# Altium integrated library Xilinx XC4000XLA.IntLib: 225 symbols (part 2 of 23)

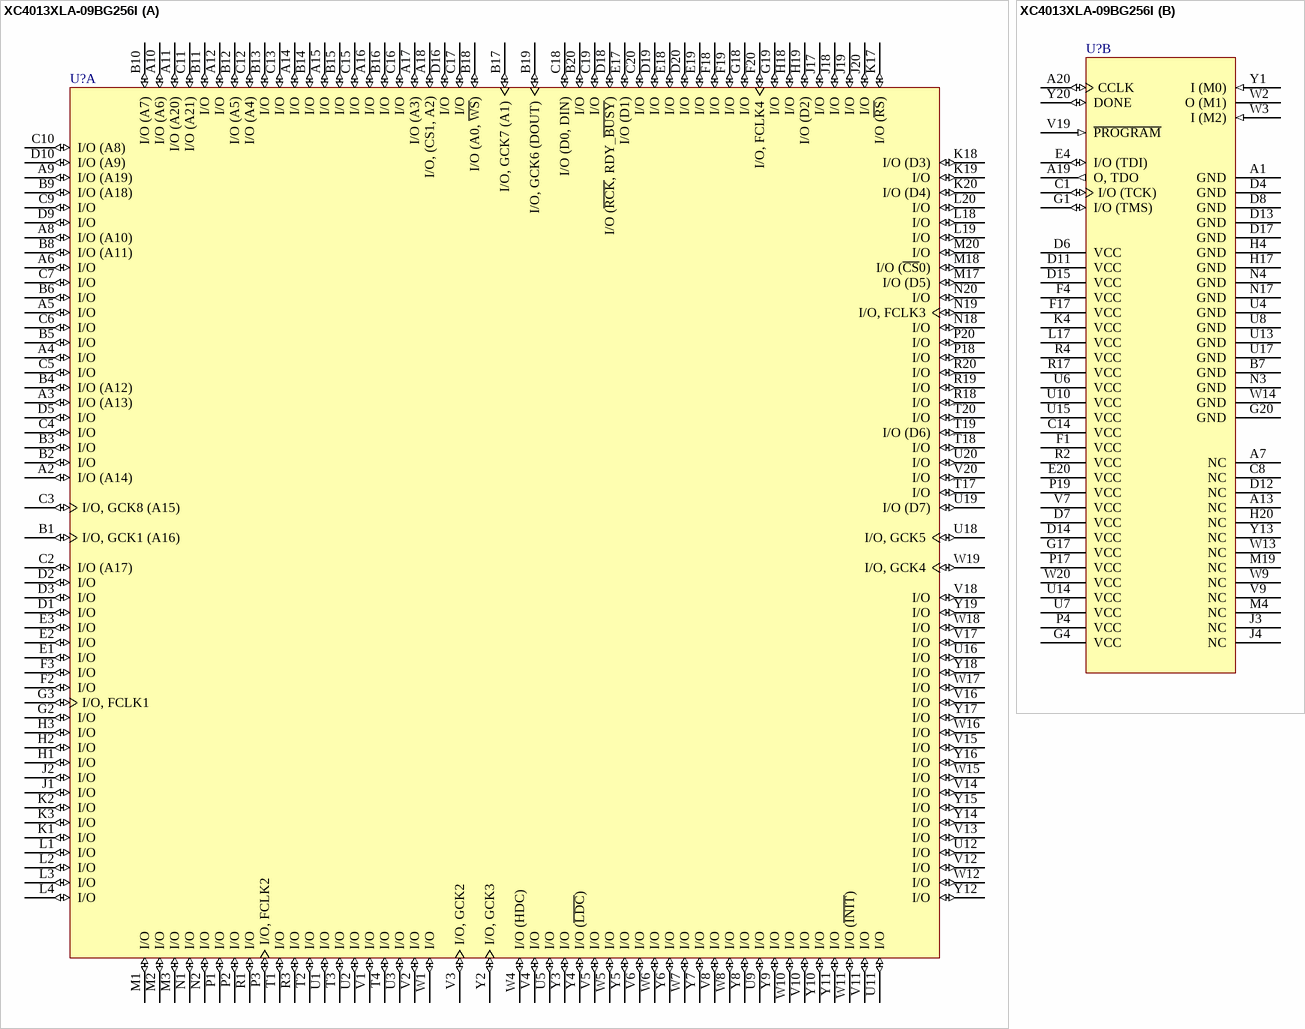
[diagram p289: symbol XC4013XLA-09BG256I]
## XC4013XLA-09BG256I
designator U?
XC4000XLA FPGA, 192 I/Os, 256-Ball BGA, Speed Grade 9, Industrial Grade
footprint BG256 (BGA, 256-Leads, Body 27x27mm, Pitch 1.27mm)
part A pins: A2 I/O (A14) (io), A3 I/O (A13) (io), A4 I/O (io), A5 I/O (io), A6 I/O (io), A8 I/O (A10) (io), A9 I/O (A19) (io), A10 I/O (A6) (io), A11 I/O (A20) (io), A12 I/O (io), A14 I/O (io), A15 I/O (io), A16 I/O (io), A17 I/O (A3) (io), A18 I/O, (CS1, A2) (io), B1 I/O, GCK1 (A16) (io), B2 I/O (io), B3 I/O (io), B4 I/O (A12) (io), B5 I/O (io), B6 I/O (io), B8 I/O (A11) (io), B9 I/O (A18) (io), B10 I/O (A7) (io), B11 I/O (io), B12 I/O (A5) (io), B13 I/O (io), B14 I/O (io), B15 I/O (io), B16 I/O (io), B17 I/O, GCK7 (A1) (io), B18 I/O (A0, ~{WS}) (io), B19 I/O, GCK6 (DOUT) (io), B20 I/O (io), C2 I/O (A17) (io), C3 I/O, GCK8 (A15) (io), C4 I/O (io), C5 I/O (io), C6 I/O (io), C7 I/O (io), C9 I/O (io), C10 I/O (A8) (io), C11 I/O (A21) (io), C12 I/O (A4) (io), C13 I/O (io), C15 I/O (io), C16 I/O (io), C17 I/O (io), C18 I/O (D0, DIN) (io), C19 I/O (io), C20 I/O (io), D1 I/O (io), D2 I/O (io), D3 I/O (io), D5 I/O (io), D9 I/O (io), D10 I/O (A9) (io), D16 I/O (io), D18 I/O (~{RCK}, RDY_~{BUSY}) (io), D19 I/O (io), D20 I/O (io), E1 I/O (io), E2 I/O (io), E3 I/O (io), E17 I/O (D1) (io), E18 I/O (io), E19 I/O (io), F2 I/O (io), F3 I/O (io), F18 I/O (io), F19 I/O (io), F20 I/O, FCLK4 (io), G2 I/O (io), G3 I/O, FCLK1 (io), G18 I/O (io), G19 I/O (io), H1 I/O (io), H2 I/O (io), H3 I/O (io), H18 I/O (io), H19 I/O (D2) (io), J1 I/O (io), J2 I/O (io), J17 I/O (io), J18 I/O (io), J19 I/O (io), J20 I/O (io), K1 I/O (io), K2 I/O (io), K3 I/O (io), K17 I/O (~{RS}) (io), K18 I/O (D3) (io), K19 I/O (io), K20 I/O (D4) (io), L1 I/O (io), L2 I/O (io), L3 I/O (io), L4 I/O (io), L18 I/O (io), L19 I/O (io), L20 I/O (io), M1 I/O (io), M2 I/O (io), M3 I/O (io), M17 I/O (D5) (io), M18 I/O (~{CS}0) (io), M20 I/O (io), N1 I/O (io), N2 I/O (io), N18 I/O (io), N19 I/O, FCLK3 (io), N20 I/O (io), P1 I/O (io), P2 I/O (io), P3 I/O, FCLK2 (io), P18 I/O (io), P20 I/O (io), R1 I/O (io), R3 I/O (io), R18 I/O (io), R19 I/O (io), R20 I/O (io), T1 I/O (io), T2 I/O (io), T3 I/O (io), T4 I/O (io), T17 I/O (io), T18 I/O (io), T19 I/O (D6) (io), T20 I/O (io), U1 I/O (io), U2 I/O (io), U3 I/O (io), U5 I/O (io), U9 I/O (io), U11 I/O (io), U12 I/O (io), U16 I/O (io), U18 I/O, GCK5 (io), U19 I/O (D7) (io), U20 I/O (io), V1 I/O (io), V2 I/O (io), V3 I/O, GCK2 (io), V4 I/O (io), V5 I/O (io), V6 I/O (io), V8 I/O (io), V10 I/O (io), V11 I/O (io), V12 I/O (io), V13 I/O (io), V14 I/O (io), V15 I/O (io), V16 I/O (io), V17 I/O (io), V18 I/O (io), V20 I/O (io), W1 I/O (io), W4 I/O (HDC) (io), W5 I/O (io), W6 I/O (io), W7 I/O (io), W8 I/O (io), W10 I/O (io), W11 I/O (~{INIT}) (io), W12 I/O (io), W15 I/O (io), W16 I/O (io), W17 I/O (io), W18 I/O (io), W19 I/O, GCK4 (io), Y2 I/O, GCK3 (io), Y3 I/O (io), Y4 I/O (~{LDC}) (io), Y5 I/O (io), Y6 I/O (io), Y7 I/O (io), Y8 I/O (io), Y9 I/O (io), Y10 I/O (io), Y11 I/O (io), Y12 I/O (io), Y14 I/O (io), Y15 I/O (io), Y16 I/O (io), Y17 I/O (io), Y18 I/O (io), Y19 I/O (io)
part B pins: A1 GND (power), A7 NC, A13 NC, A19 O, TDO (out), A20 CCLK (io), B7 GND (power), C1 I/O (TCK) (io), C8 NC, C14 VCC (power), D4 GND (power), D6 VCC (power), D7 VCC (power), D8 GND (power), D11 VCC (power), D12 NC, D13 GND (power), D14 VCC (power), D15 VCC (power), D17 GND (power), E4 I/O (TDI) (io), E20 VCC (power), F1 VCC (power), F4 VCC (power), F17 VCC (power), G1 I/O (TMS) (io), G4 VCC (power), G17 VCC (power), G20 GND (power), H4 GND (power), H17 GND (power), H20 NC, J3 NC, J4 NC, K4 VCC (power), L17 VCC (power), M4 NC, M19 NC, N3 GND (power), N4 GND (power), N17 GND (power), P4 VCC (power), P17 VCC (power), P19 VCC (power), R2 VCC (power), R4 VCC (power), R17 VCC (power), U4 GND (power), U6 VCC (power), U7 VCC (power), U8 GND (power), U10 VCC (power), U13 GND (power), U14 VCC (power), U15 VCC (power), U17 GND (power), V7 VCC (power), V9 NC, V19 ~{PROGRAM} (in), W2 O (M1), W3 I (M2) (in), W9 NC, W13 NC, W14 GND (power), W20 VCC (power), Y1 I (M0) (in), Y13 NC, Y20 DONE (io)


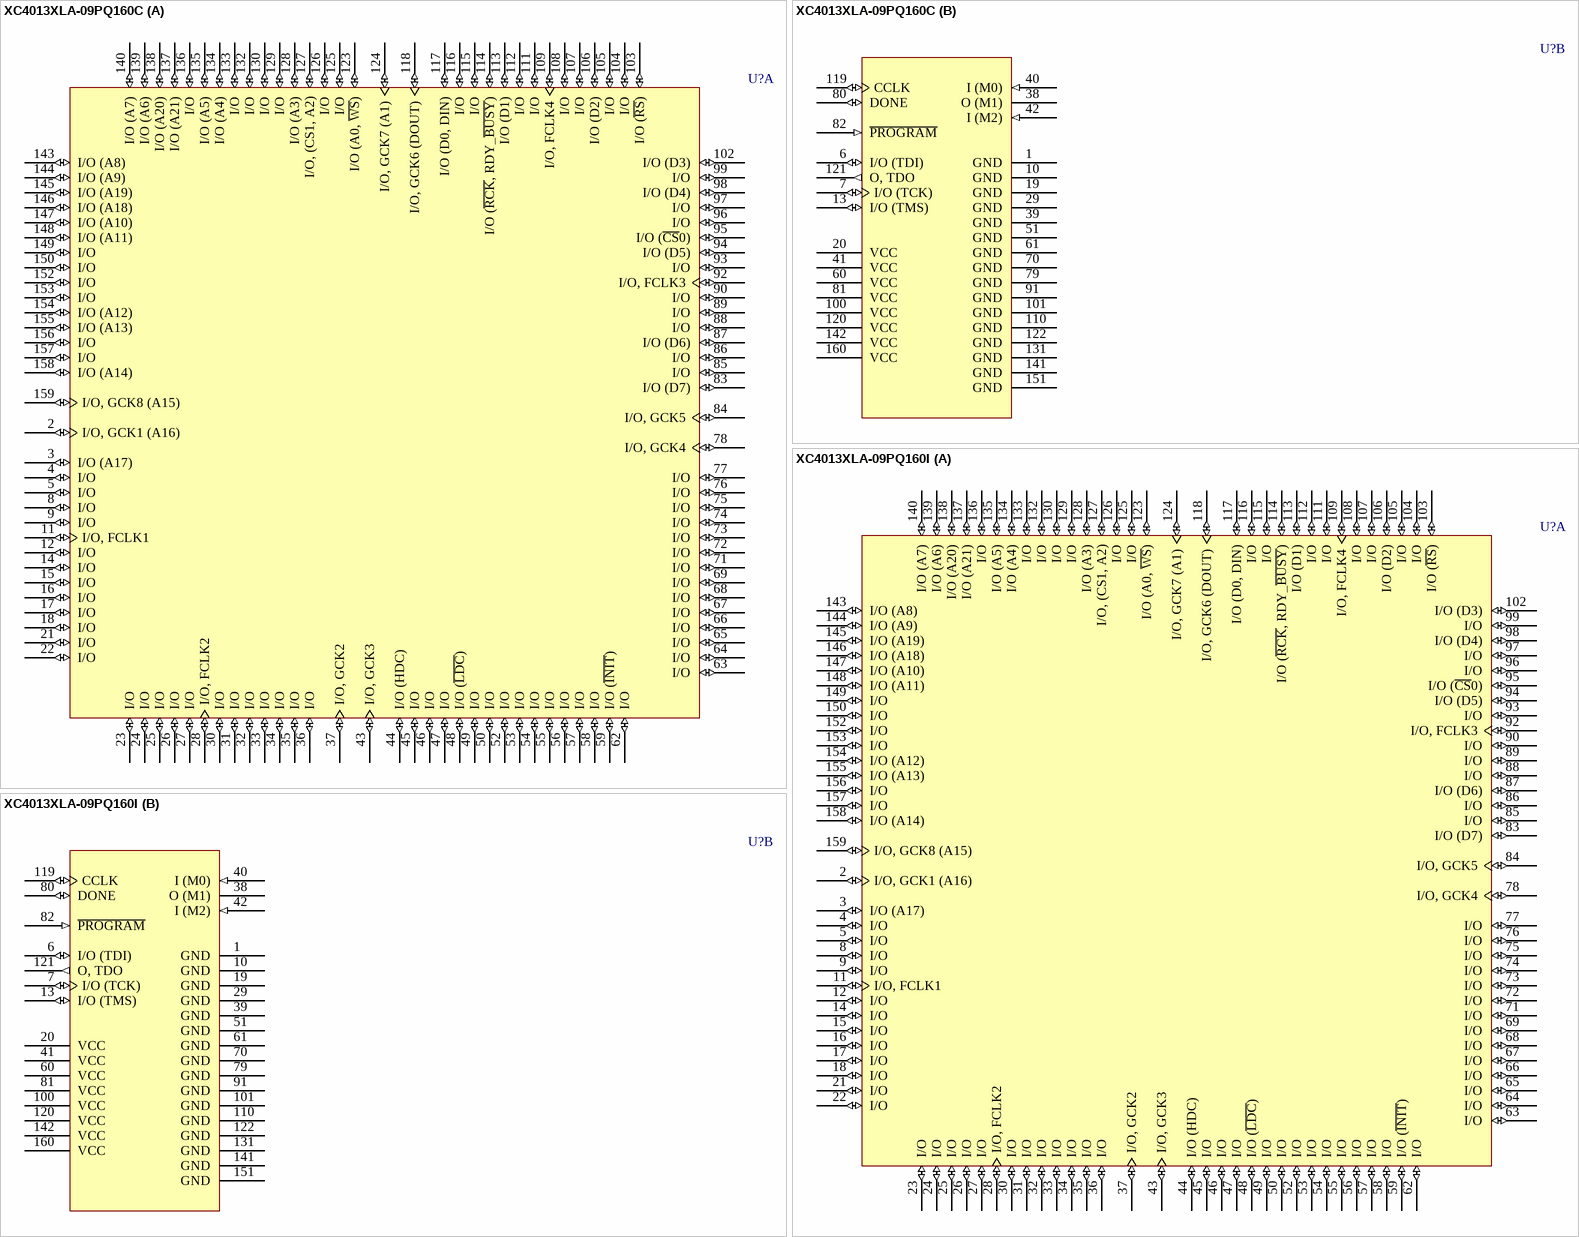
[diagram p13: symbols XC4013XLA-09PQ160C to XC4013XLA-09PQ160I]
## XC4013XLA-09PQ160C
designator U?
XC4000XLA FPGA, 129 I/Os, 160-Pin PQFP, Speed Grade 9, Commercial Grade
footprint PQ160_N (QFP, 160-Leads, Body 28x28mm, Pitch 0.65mm, IPC Medium Density)
footprint PQ160_L (QFP, 160-Leads, Body 28x28mm, Pitch 0.65mm, IPC High Density)
footprint PQ160_M (QFP, 160-Leads, Body 28x28mm, Pitch 0.65mm, IPC Low Density)
part A pins: 2 I/O, GCK1 (A16) (io), 3 I/O (A17) (io), 4 I/O (io), 5 I/O (io), 8 I/O (io), 9 I/O (io), 11 I/O, FCLK1 (io), 12 I/O (io), 14 I/O (io), 15 I/O (io), 16 I/O (io), 17 I/O (io), 18 I/O (io), 21 I/O (io), 22 I/O (io), 23 I/O (io), 24 I/O (io), 25 I/O (io), 26 I/O (io), 27 I/O (io), 28 I/O, FCLK2 (io), 30 I/O (io), 31 I/O (io), 32 I/O (io), 33 I/O (io), 34 I/O (io), 35 I/O (io), 36 I/O (io), 37 I/O, GCK2 (io), 43 I/O, GCK3 (io), 44 I/O (HDC) (io), 45 I/O (io), 46 I/O (io), 47 I/O (io), 48 I/O (~{LDC}) (io), 49 I/O (io), 50 I/O (io), 52 I/O (io), 53 I/O (io), 54 I/O (io), 55 I/O (io), 56 I/O (io), 57 I/O (io), 58 I/O (io), 59 I/O (~{INIT}) (io), 62 I/O (io), 63 I/O (io), 64 I/O (io), 65 I/O (io), 66 I/O (io), 67 I/O (io), 68 I/O (io), 69 I/O (io), 71 I/O (io), 72 I/O (io), 73 I/O (io), 74 I/O (io), 75 I/O (io), 76 I/O (io), 77 I/O (io), 78 I/O, GCK4 (io), 83 I/O (D7) (io), 84 I/O, GCK5 (io), 85 I/O (io), 86 I/O (io), 87 I/O (D6) (io), 88 I/O (io), 89 I/O (io), 90 I/O (io), 92 I/O, FCLK3 (io), 93 I/O (io), 94 I/O (D5) (io), 95 I/O (~{CS}0) (io), 96 I/O (io), 97 I/O (io), 98 I/O (D4) (io), 99 I/O (io), 102 I/O (D3) (io), 103 I/O (~{RS}) (io), 104 I/O (io), 105 I/O (io), 106 I/O (D2) (io), 107 I/O (io), 108 I/O (io), 109 I/O, FCLK4 (io), 111 I/O (io), 112 I/O (io), 113 I/O (D1) (io), 114 I/O (~{RCK}, RDY_~{BUSY}) (io), 115 I/O (io), 116 I/O (io), 117 I/O (D0, DIN) (io), 118 I/O, GCK6 (DOUT) (io), 123 I/O (A0, ~{WS}) (io), 124 I/O, GCK7 (A1) (io), 125 I/O (io), 126 I/O (io), 127 I/O, (CS1, A2) (io), 128 I/O (A3) (io), 129 I/O (io), 130 I/O (io), 132 I/O (io), 133 I/O (io), 134 I/O (A4) (io), 135 I/O (A5) (io), 136 I/O (io), 137 I/O (A21) (io), 138 I/O (A20) (io), 139 I/O (A6) (io), 140 I/O (A7) (io), 143 I/O (A8) (io), 144 I/O (A9) (io), 145 I/O (A19) (io), 146 I/O (A18) (io), 147 I/O (A10) (io), 148 I/O (A11) (io), 149 I/O (io), 150 I/O (io), 152 I/O (io), 153 I/O (io), 154 I/O (A12) (io), 155 I/O (A13) (io), 156 I/O (io), 157 I/O (io), 158 I/O (A14) (io), 159 I/O, GCK8 (A15) (io)
part B pins: 1 GND (power), 6 I/O (TDI) (io), 7 I/O (TCK) (io), 10 GND (power), 13 I/O (TMS) (io), 19 GND (power), 20 VCC (power), 29 GND (power), 38 O (M1), 39 GND (power), 40 I (M0) (in), 41 VCC (power), 42 I (M2) (in), 51 GND (power), 60 VCC (power), 61 GND (power), 70 GND (power), 79 GND (power), 80 DONE (io), 81 VCC (power), 82 ~{PROGRAM} (in), 91 GND (power), 100 VCC (power), 101 GND (power), 110 GND (power), 119 CCLK (io), 120 VCC (power), 121 O, TDO (out), 122 GND (power), 131 GND (power), 141 GND (power), 142 VCC (power), 151 GND (power), 160 VCC (power)

## XC4013XLA-09PQ160I
designator U?
XC4000XLA FPGA, 129 I/Os, 160-Pin PQFP, Speed Grade 9, Industrial Grade
footprint PQ160_N (QFP, 160-Leads, Body 28x28mm, Pitch 0.65mm, IPC Medium Density)
footprint PQ160_L (QFP, 160-Leads, Body 28x28mm, Pitch 0.65mm, IPC High Density)
footprint PQ160_M (QFP, 160-Leads, Body 28x28mm, Pitch 0.65mm, IPC Low Density)
part A pins: 2 I/O, GCK1 (A16) (io), 3 I/O (A17) (io), 4 I/O (io), 5 I/O (io), 8 I/O (io), 9 I/O (io), 11 I/O, FCLK1 (io), 12 I/O (io), 14 I/O (io), 15 I/O (io), 16 I/O (io), 17 I/O (io), 18 I/O (io), 21 I/O (io), 22 I/O (io), 23 I/O (io), 24 I/O (io), 25 I/O (io), 26 I/O (io), 27 I/O (io), 28 I/O, FCLK2 (io), 30 I/O (io), 31 I/O (io), 32 I/O (io), 33 I/O (io), 34 I/O (io), 35 I/O (io), 36 I/O (io), 37 I/O, GCK2 (io), 43 I/O, GCK3 (io), 44 I/O (HDC) (io), 45 I/O (io), 46 I/O (io), 47 I/O (io), 48 I/O (~{LDC}) (io), 49 I/O (io), 50 I/O (io), 52 I/O (io), 53 I/O (io), 54 I/O (io), 55 I/O (io), 56 I/O (io), 57 I/O (io), 58 I/O (io), 59 I/O (~{INIT}) (io), 62 I/O (io), 63 I/O (io), 64 I/O (io), 65 I/O (io), 66 I/O (io), 67 I/O (io), 68 I/O (io), 69 I/O (io), 71 I/O (io), 72 I/O (io), 73 I/O (io), 74 I/O (io), 75 I/O (io), 76 I/O (io), 77 I/O (io), 78 I/O, GCK4 (io), 83 I/O (D7) (io), 84 I/O, GCK5 (io), 85 I/O (io), 86 I/O (io), 87 I/O (D6) (io), 88 I/O (io), 89 I/O (io), 90 I/O (io), 92 I/O, FCLK3 (io), 93 I/O (io), 94 I/O (D5) (io), 95 I/O (~{CS}0) (io), 96 I/O (io), 97 I/O (io), 98 I/O (D4) (io), 99 I/O (io), 102 I/O (D3) (io), 103 I/O (~{RS}) (io), 104 I/O (io), 105 I/O (io), 106 I/O (D2) (io), 107 I/O (io), 108 I/O (io), 109 I/O, FCLK4 (io), 111 I/O (io), 112 I/O (io), 113 I/O (D1) (io), 114 I/O (~{RCK}, RDY_~{BUSY}) (io), 115 I/O (io), 116 I/O (io), 117 I/O (D0, DIN) (io), 118 I/O, GCK6 (DOUT) (io), 123 I/O (A0, ~{WS}) (io), 124 I/O, GCK7 (A1) (io), 125 I/O (io), 126 I/O (io), 127 I/O, (CS1, A2) (io), 128 I/O (A3) (io), 129 I/O (io), 130 I/O (io), 132 I/O (io), 133 I/O (io), 134 I/O (A4) (io), 135 I/O (A5) (io), 136 I/O (io), 137 I/O (A21) (io), 138 I/O (A20) (io), 139 I/O (A6) (io), 140 I/O (A7) (io), 143 I/O (A8) (io), 144 I/O (A9) (io), 145 I/O (A19) (io), 146 I/O (A18) (io), 147 I/O (A10) (io), 148 I/O (A11) (io), 149 I/O (io), 150 I/O (io), 152 I/O (io), 153 I/O (io), 154 I/O (A12) (io), 155 I/O (A13) (io), 156 I/O (io), 157 I/O (io), 158 I/O (A14) (io), 159 I/O, GCK8 (A15) (io)
part B pins: 1 GND (power), 6 I/O (TDI) (io), 7 I/O (TCK) (io), 10 GND (power), 13 I/O (TMS) (io), 19 GND (power), 20 VCC (power), 29 GND (power), 38 O (M1), 39 GND (power), 40 I (M0) (in), 41 VCC (power), 42 I (M2) (in), 51 GND (power), 60 VCC (power), 61 GND (power), 70 GND (power), 79 GND (power), 80 DONE (io), 81 VCC (power), 82 ~{PROGRAM} (in), 91 GND (power), 100 VCC (power), 101 GND (power), 110 GND (power), 119 CCLK (io), 120 VCC (power), 121 O, TDO (out), 122 GND (power), 131 GND (power), 141 GND (power), 142 VCC (power), 151 GND (power), 160 VCC (power)


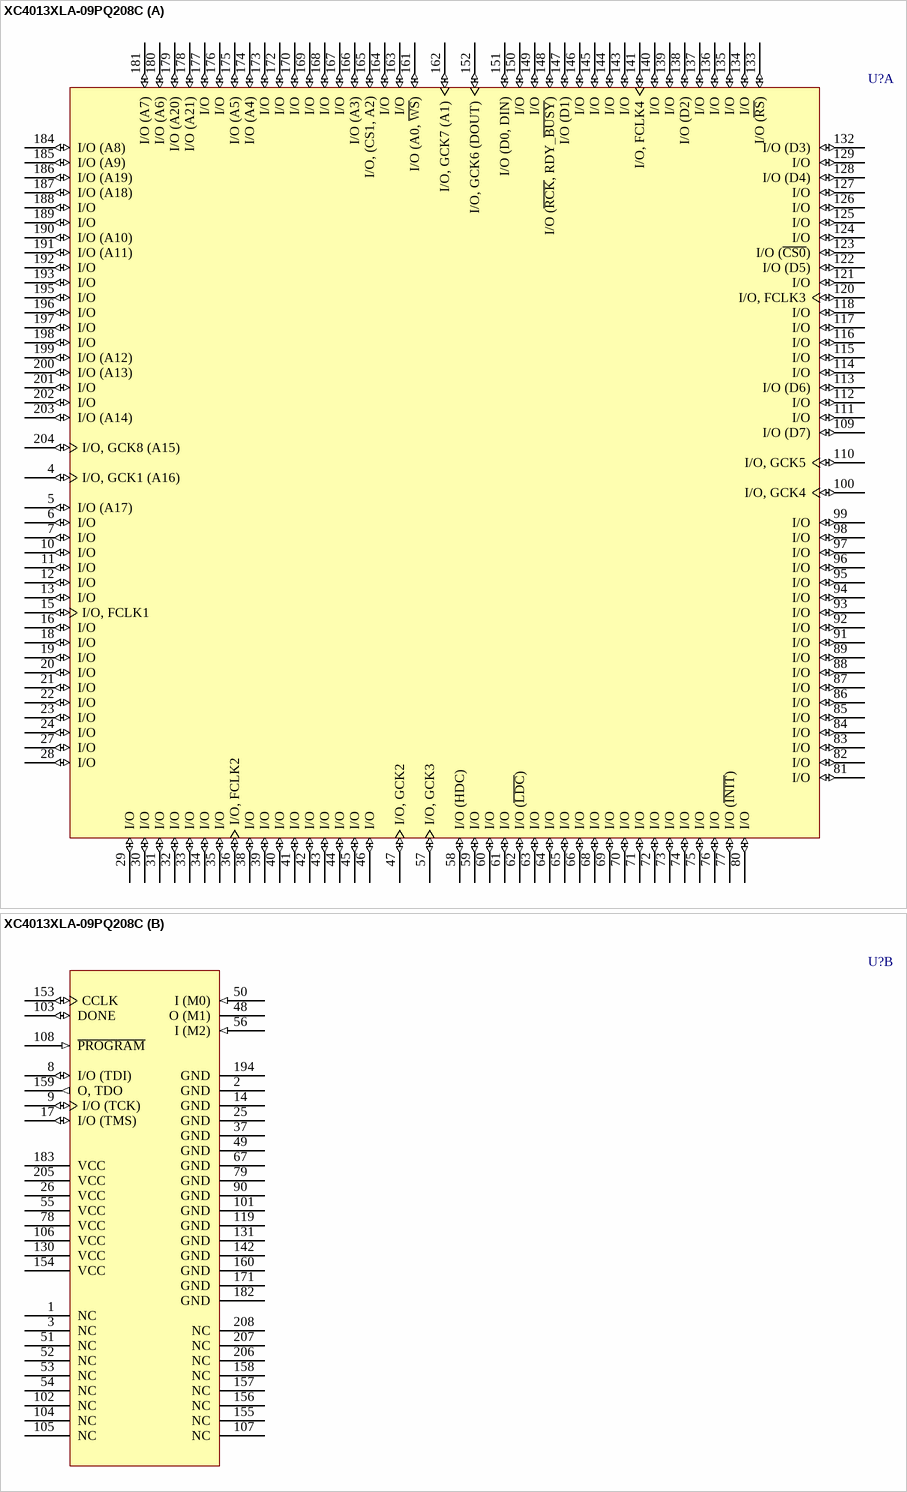
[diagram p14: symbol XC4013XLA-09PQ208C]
## XC4013XLA-09PQ208C
designator U?
XC4000XLA FPGA, 160 I/Os, 208-Pin PQFP, Speed Grade 9, Commercial Grade
footprint PQ208_N (Shrink QFP, 208-Leads, Body 28x28mm, Pitch 0.5mm, IPC Medium Density)
footprint PQ208_L (Shrink QFP, 208-Leads, Body 28x28mm, Pitch 0.5mm, IPC High Density)
footprint PQ208_M (Shrink QFP, 208-Leads, Body 28x28mm, Pitch 0.5mm, IPC Low Density)
part A pins: 4 I/O, GCK1 (A16) (io), 5 I/O (A17) (io), 6 I/O (io), 7 I/O (io), 10 I/O (io), 11 I/O (io), 12 I/O (io), 13 I/O (io), 15 I/O, FCLK1 (io), 16 I/O (io), 18 I/O (io), 19 I/O (io), 20 I/O (io), 21 I/O (io), 22 I/O (io), 23 I/O (io), 24 I/O (io), 27 I/O (io), 28 I/O (io), 29 I/O (io), 30 I/O (io), 31 I/O (io), 32 I/O (io), 33 I/O (io), 34 I/O (io), 35 I/O (io), 36 I/O, FCLK2 (io), 38 I/O (io), 39 I/O (io), 40 I/O (io), 41 I/O (io), 42 I/O (io), 43 I/O (io), 44 I/O (io), 45 I/O (io), 46 I/O (io), 47 I/O, GCK2 (io), 57 I/O, GCK3 (io), 58 I/O (HDC) (io), 59 I/O (io), 60 I/O (io), 61 I/O (io), 62 I/O (~{LDC}) (io), 63 I/O (io), 64 I/O (io), 65 I/O (io), 66 I/O (io), 68 I/O (io), 69 I/O (io), 70 I/O (io), 71 I/O (io), 72 I/O (io), 73 I/O (io), 74 I/O (io), 75 I/O (io), 76 I/O (io), 77 I/O (~{INIT}) (io), 80 I/O (io), 81 I/O (io), 82 I/O (io), 83 I/O (io), 84 I/O (io), 85 I/O (io), 86 I/O (io), 87 I/O (io), 88 I/O (io), 89 I/O (io), 91 I/O (io), 92 I/O (io), 93 I/O (io), 94 I/O (io), 95 I/O (io), 96 I/O (io), 97 I/O (io), 98 I/O (io), 99 I/O (io), 100 I/O, GCK4 (io), 109 I/O (D7) (io), 110 I/O, GCK5 (io), 111 I/O (io), 112 I/O (io), 113 I/O (D6) (io), 114 I/O (io), 115 I/O (io), 116 I/O (io), 117 I/O (io), 118 I/O (io), 120 I/O, FCLK3 (io), 121 I/O (io), 122 I/O (D5) (io), 123 I/O (~{CS0}) (io), 124 I/O (io), 125 I/O (io), 126 I/O (io), 127 I/O (io), 128 I/O (D4) (io), 129 I/O (io), 132 I/O (D3) (io), 133 I/O (~{RS}) (io), 134 I/O (io), 135 I/O (io), 136 I/O (io), 137 I/O (io), 138 I/O (D2) (io), 139 I/O (io), 140 I/O (io), 141 I/O, FCLK4 (io), 143 I/O (io), 144 I/O (io), 145 I/O (io), 146 I/O (io), 147 I/O (D1) (io), 148 I/O (~{RCK}, RDY_~{BUSY}) (io), 149 I/O (io), 150 I/O (io), 151 I/O (D0, DIN) (io), 152 I/O, GCK6 (DOUT) (io), 161 I/O (A0, ~{WS}) (io), 162 I/O, GCK7 (A1) (io), 163 I/O (io), 164 I/O (io), 165 I/O, (CS1, A2) (io), 166 I/O (A3) (io), 167 I/O (io), 168 I/O (io), 169 I/O (io), 170 I/O (io), 172 I/O (io), 173 I/O (io), 174 I/O (A4) (io), 175 I/O (A5) (io), 176 I/O (io), 177 I/O (io), 178 I/O (A21) (io), 179 I/O (A20) (io), 180 I/O (A6) (io), 181 I/O (A7) (io), 184 I/O (A8) (io), 185 I/O (A9) (io), 186 I/O (A19) (io), 187 I/O (A18) (io), 188 I/O (io), 189 I/O (io), 190 I/O (A10) (io), 191 I/O (A11) (io), 192 I/O (io), 193 I/O (io), 195 I/O (io), 196 I/O (io), 197 I/O (io), 198 I/O (io), 199 I/O (A12) (io), 200 I/O (A13) (io), 201 I/O (io), 202 I/O (io), 203 I/O (A14) (io), 204 I/O, GCK8 (A15) (io)
part B pins: 1 NC, 2 GND (power), 3 NC, 8 I/O (TDI) (io), 9 I/O (TCK) (io), 14 GND (power), 17 I/O (TMS) (io), 25 GND (power), 26 VCC (power), 37 GND (power), 48 O (M1), 49 GND (power), 50 I (M0) (in), 51 NC, 52 NC, 53 NC, 54 NC, 55 VCC (power), 56 I (M2) (in), 67 GND (power), 78 VCC (power), 79 GND (power), 90 GND (power), 101 GND (power), 102 NC, 103 DONE (io), 104 NC, 105 NC, 106 VCC (power), 107 NC, 108 ~{PROGRAM} (in), 119 GND (power), 130 VCC (power), 131 GND (power), 142 GND (power), 153 CCLK (io), 154 VCC (power), 155 NC, 156 NC, 157 NC, 158 NC, 159 O, TDO (out), 160 GND (power), 171 GND (power), 182 GND (power), 183 VCC (power), 194 GND (power), 205 VCC (power), 206 NC, 207 NC, 208 NC


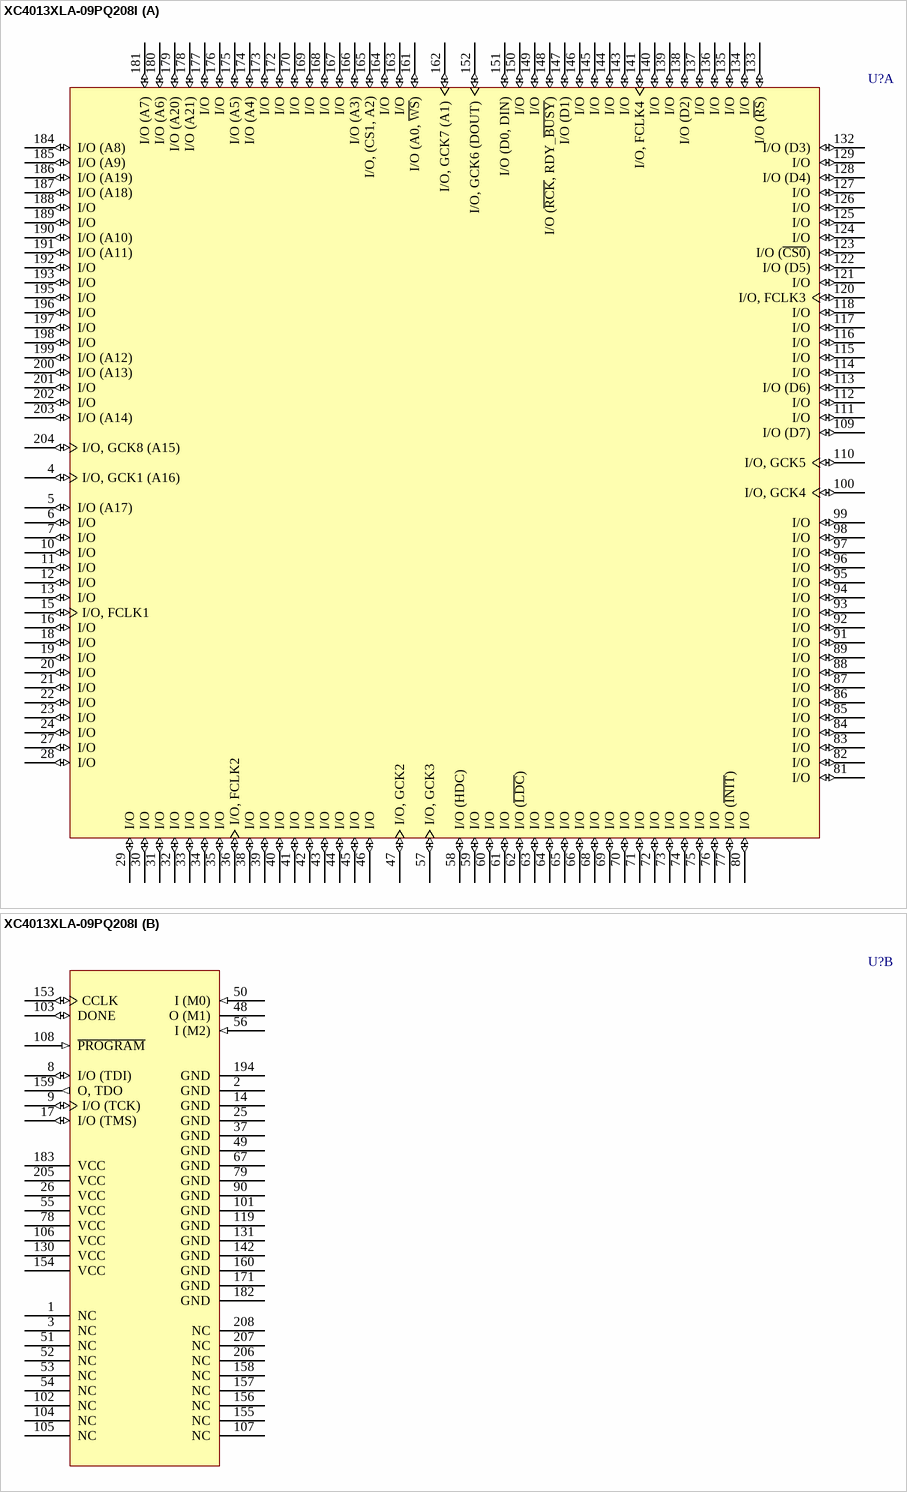
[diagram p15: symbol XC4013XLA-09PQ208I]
## XC4013XLA-09PQ208I
designator U?
XC4000XLA FPGA, 160 I/Os, 208-Pin PQFP, Speed Grade 9, Industrial Grade
footprint PQ208_N (Shrink QFP, 208-Leads, Body 28x28mm, Pitch 0.5mm, IPC Medium Density)
footprint PQ208_L (Shrink QFP, 208-Leads, Body 28x28mm, Pitch 0.5mm, IPC High Density)
footprint PQ208_M (Shrink QFP, 208-Leads, Body 28x28mm, Pitch 0.5mm, IPC Low Density)
part A pins: 4 I/O, GCK1 (A16) (io), 5 I/O (A17) (io), 6 I/O (io), 7 I/O (io), 10 I/O (io), 11 I/O (io), 12 I/O (io), 13 I/O (io), 15 I/O, FCLK1 (io), 16 I/O (io), 18 I/O (io), 19 I/O (io), 20 I/O (io), 21 I/O (io), 22 I/O (io), 23 I/O (io), 24 I/O (io), 27 I/O (io), 28 I/O (io), 29 I/O (io), 30 I/O (io), 31 I/O (io), 32 I/O (io), 33 I/O (io), 34 I/O (io), 35 I/O (io), 36 I/O, FCLK2 (io), 38 I/O (io), 39 I/O (io), 40 I/O (io), 41 I/O (io), 42 I/O (io), 43 I/O (io), 44 I/O (io), 45 I/O (io), 46 I/O (io), 47 I/O, GCK2 (io), 57 I/O, GCK3 (io), 58 I/O (HDC) (io), 59 I/O (io), 60 I/O (io), 61 I/O (io), 62 I/O (~{LDC}) (io), 63 I/O (io), 64 I/O (io), 65 I/O (io), 66 I/O (io), 68 I/O (io), 69 I/O (io), 70 I/O (io), 71 I/O (io), 72 I/O (io), 73 I/O (io), 74 I/O (io), 75 I/O (io), 76 I/O (io), 77 I/O (~{INIT}) (io), 80 I/O (io), 81 I/O (io), 82 I/O (io), 83 I/O (io), 84 I/O (io), 85 I/O (io), 86 I/O (io), 87 I/O (io), 88 I/O (io), 89 I/O (io), 91 I/O (io), 92 I/O (io), 93 I/O (io), 94 I/O (io), 95 I/O (io), 96 I/O (io), 97 I/O (io), 98 I/O (io), 99 I/O (io), 100 I/O, GCK4 (io), 109 I/O (D7) (io), 110 I/O, GCK5 (io), 111 I/O (io), 112 I/O (io), 113 I/O (D6) (io), 114 I/O (io), 115 I/O (io), 116 I/O (io), 117 I/O (io), 118 I/O (io), 120 I/O, FCLK3 (io), 121 I/O (io), 122 I/O (D5) (io), 123 I/O (~{CS0}) (io), 124 I/O (io), 125 I/O (io), 126 I/O (io), 127 I/O (io), 128 I/O (D4) (io), 129 I/O (io), 132 I/O (D3) (io), 133 I/O (~{RS}) (io), 134 I/O (io), 135 I/O (io), 136 I/O (io), 137 I/O (io), 138 I/O (D2) (io), 139 I/O (io), 140 I/O (io), 141 I/O, FCLK4 (io), 143 I/O (io), 144 I/O (io), 145 I/O (io), 146 I/O (io), 147 I/O (D1) (io), 148 I/O (~{RCK}, RDY_~{BUSY}) (io), 149 I/O (io), 150 I/O (io), 151 I/O (D0, DIN) (io), 152 I/O, GCK6 (DOUT) (io), 161 I/O (A0, ~{WS}) (io), 162 I/O, GCK7 (A1) (io), 163 I/O (io), 164 I/O (io), 165 I/O, (CS1, A2) (io), 166 I/O (A3) (io), 167 I/O (io), 168 I/O (io), 169 I/O (io), 170 I/O (io), 172 I/O (io), 173 I/O (io), 174 I/O (A4) (io), 175 I/O (A5) (io), 176 I/O (io), 177 I/O (io), 178 I/O (A21) (io), 179 I/O (A20) (io), 180 I/O (A6) (io), 181 I/O (A7) (io), 184 I/O (A8) (io), 185 I/O (A9) (io), 186 I/O (A19) (io), 187 I/O (A18) (io), 188 I/O (io), 189 I/O (io), 190 I/O (A10) (io), 191 I/O (A11) (io), 192 I/O (io), 193 I/O (io), 195 I/O (io), 196 I/O (io), 197 I/O (io), 198 I/O (io), 199 I/O (A12) (io), 200 I/O (A13) (io), 201 I/O (io), 202 I/O (io), 203 I/O (A14) (io), 204 I/O, GCK8 (A15) (io)
part B pins: 1 NC, 2 GND (power), 3 NC, 8 I/O (TDI) (io), 9 I/O (TCK) (io), 14 GND (power), 17 I/O (TMS) (io), 25 GND (power), 26 VCC (power), 37 GND (power), 48 O (M1), 49 GND (power), 50 I (M0) (in), 51 NC, 52 NC, 53 NC, 54 NC, 55 VCC (power), 56 I (M2) (in), 67 GND (power), 78 VCC (power), 79 GND (power), 90 GND (power), 101 GND (power), 102 NC, 103 DONE (io), 104 NC, 105 NC, 106 VCC (power), 107 NC, 108 ~{PROGRAM} (in), 119 GND (power), 130 VCC (power), 131 GND (power), 142 GND (power), 153 CCLK (io), 154 VCC (power), 155 NC, 156 NC, 157 NC, 158 NC, 159 O, TDO (out), 160 GND (power), 171 GND (power), 182 GND (power), 183 VCC (power), 194 GND (power), 205 VCC (power), 206 NC, 207 NC, 208 NC


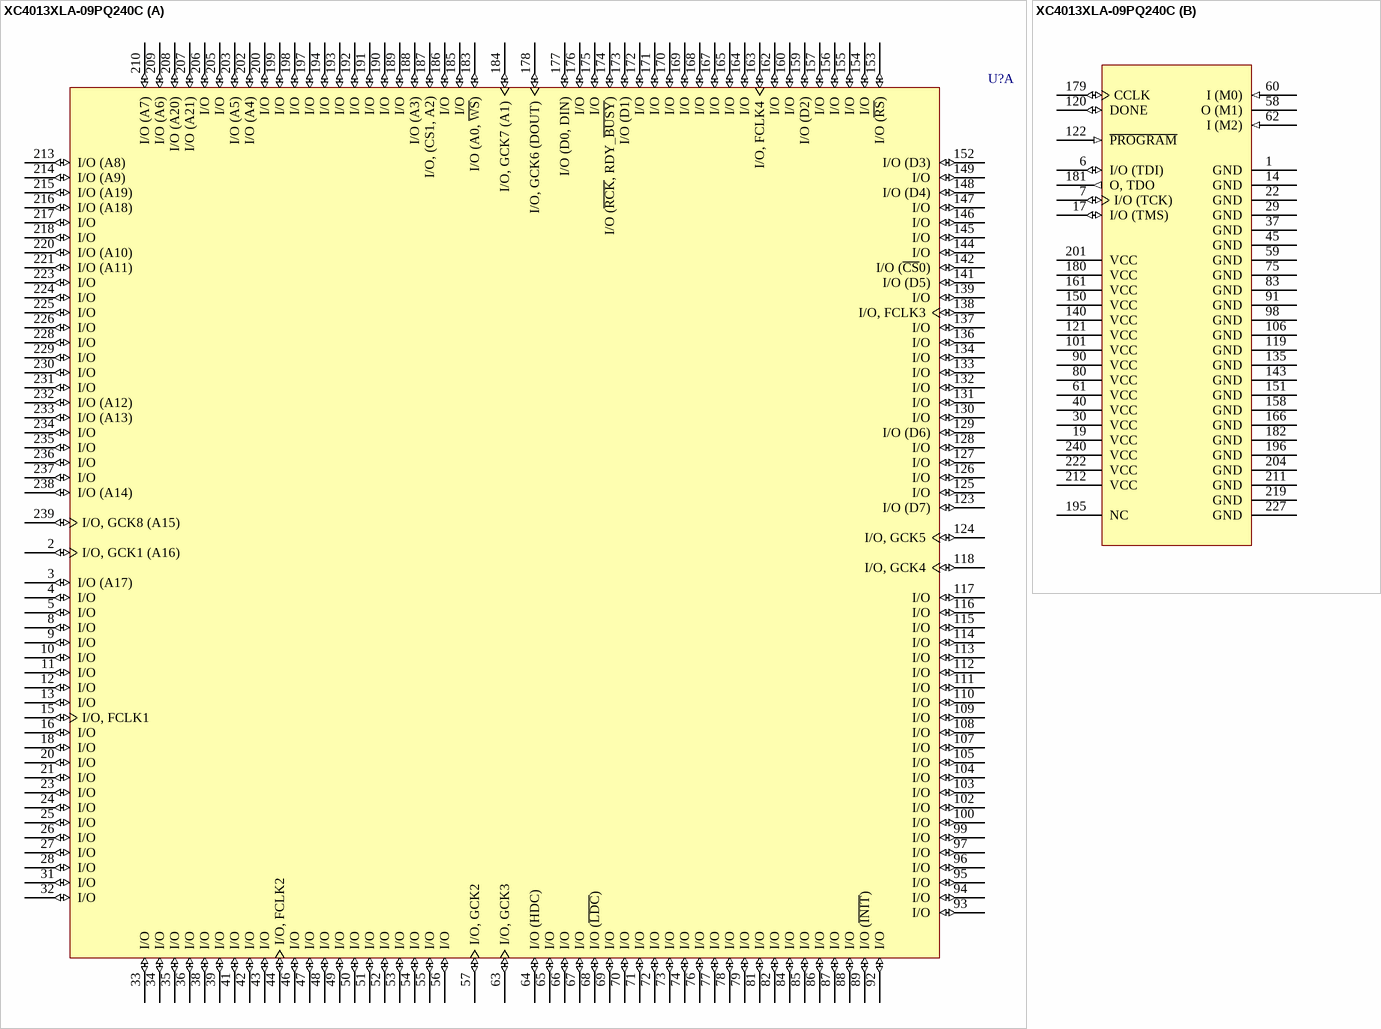
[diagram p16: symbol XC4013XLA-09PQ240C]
## XC4013XLA-09PQ240C
designator U?
XC4000XLA FPGA, 192 I/Os, 240-Pin PQFP, Speed Grade 9, Commercial Grade
footprint PQ240_N (Shrink QFP, 240-Leads, Body 32x32mm, Pitch 0.5mm, IPC Medium Density)
footprint PQ240_L (Shrink QFP, 240-Leads, Body 32x32mm, Pitch 0.5mm, IPC High Density)
footprint PQ240_M (Shrink QFP, 240-Leads, Body 32x32mm, Pitch 0.5mm, IPC Low Density)
part A pins: 2 I/O, GCK1 (A16) (io), 3 I/O (A17) (io), 4 I/O (io), 5 I/O (io), 8 I/O (io), 9 I/O (io), 10 I/O (io), 11 I/O (io), 12 I/O (io), 13 I/O (io), 15 I/O, FCLK1 (io), 16 I/O (io), 18 I/O (io), 20 I/O (io), 21 I/O (io), 23 I/O (io), 24 I/O (io), 25 I/O (io), 26 I/O (io), 27 I/O (io), 28 I/O (io), 31 I/O (io), 32 I/O (io), 33 I/O (io), 34 I/O (io), 35 I/O (io), 36 I/O (io), 38 I/O (io), 39 I/O (io), 41 I/O (io), 42 I/O (io), 43 I/O (io), 44 I/O, FCLK2 (io), 46 I/O (io), 47 I/O (io), 48 I/O (io), 49 I/O (io), 50 I/O (io), 51 I/O (io), 52 I/O (io), 53 I/O (io), 54 I/O (io), 55 I/O (io), 56 I/O (io), 57 I/O, GCK2 (io), 63 I/O, GCK3 (io), 64 I/O (HDC) (io), 65 I/O (io), 66 I/O (io), 67 I/O (io), 68 I/O (~{LDC}) (io), 69 I/O (io), 70 I/O (io), 71 I/O (io), 72 I/O (io), 73 I/O (io), 74 I/O (io), 76 I/O (io), 77 I/O (io), 78 I/O (io), 79 I/O (io), 81 I/O (io), 82 I/O (io), 84 I/O (io), 85 I/O (io), 86 I/O (io), 87 I/O (io), 88 I/O (io), 89 I/O (~{INIT}) (io), 92 I/O (io), 93 I/O (io), 94 I/O (io), 95 I/O (io), 96 I/O (io), 97 I/O (io), 99 I/O (io), 100 I/O (io), 102 I/O (io), 103 I/O (io), 104 I/O (io), 105 I/O (io), 107 I/O (io), 108 I/O (io), 109 I/O (io), 110 I/O (io), 111 I/O (io), 112 I/O (io), 113 I/O (io), 114 I/O (io), 115 I/O (io), 116 I/O (io), 117 I/O (io), 118 I/O, GCK4 (io), 123 I/O (D7) (io), 124 I/O, GCK5 (io), 125 I/O (io), 126 I/O (io), 127 I/O (io), 128 I/O (io), 129 I/O (D6) (io), 130 I/O (io), 131 I/O (io), 132 I/O (io), 133 I/O (io), 134 I/O (io), 136 I/O (io), 137 I/O (io), 138 I/O, FCLK3 (io), 139 I/O (io), 141 I/O (D5) (io), 142 I/O (~{CS}0) (io), 144 I/O (io), 145 I/O (io), 146 I/O (io), 147 I/O (io), 148 I/O (D4) (io), 149 I/O (io), 152 I/O (D3) (io), 153 I/O (~{RS}) (io), 154 I/O (io), 155 I/O (io), 156 I/O (io), 157 I/O (io), 159 I/O (D2) (io), 160 I/O (io), 162 I/O (io), 163 I/O, FCLK4 (io), 164 I/O (io), 165 I/O (io), 167 I/O (io), 168 I/O (io), 169 I/O (io), 170 I/O (io), 171 I/O (io), 172 I/O (io), 173 I/O (D1) (io), 174 I/O (~{RCK}, RDY_~{BUSY}) (io), 175 I/O (io), 176 I/O (io), 177 I/O (D0, DIN) (io), 178 I/O, GCK6 (DOUT) (io), 183 I/O (A0, ~{WS}) (io), 184 I/O, GCK7 (A1) (io), 185 I/O (io), 186 I/O (io), 187 I/O, (CS1, A2) (io), 188 I/O (A3) (io), 189 I/O (io), 190 I/O (io), 191 I/O (io), 192 I/O (io), 193 I/O (io), 194 I/O (io), 197 I/O (io), 198 I/O (io), 199 I/O (io), 200 I/O (io), 202 I/O (A4) (io), 203 I/O (A5) (io), 205 I/O (io), 206 I/O (io), 207 I/O (A21) (io), 208 I/O (A20) (io), 209 I/O (A6) (io), 210 I/O (A7) (io), 213 I/O (A8) (io), 214 I/O (A9) (io), 215 I/O (A19) (io), 216 I/O (A18) (io), 217 I/O (io), 218 I/O (io), 220 I/O (A10) (io), 221 I/O (A11) (io), 223 I/O (io), 224 I/O (io), 225 I/O (io), 226 I/O (io), 228 I/O (io), 229 I/O (io), 230 I/O (io), 231 I/O (io), 232 I/O (A12) (io), 233 I/O (A13) (io), 234 I/O (io), 235 I/O (io), 236 I/O (io), 237 I/O (io), 238 I/O (A14) (io), 239 I/O, GCK8 (A15) (io)
part B pins: 1 GND (power), 6 I/O (TDI) (io), 7 I/O (TCK) (io), 14 GND (power), 17 I/O (TMS) (io), 19 VCC (power), 22 GND (power), 29 GND (power), 30 VCC (power), 37 GND (power), 40 VCC (power), 45 GND (power), 58 O (M1), 59 GND (power), 60 I (M0) (in), 61 VCC (power), 62 I (M2) (in), 75 GND (power), 80 VCC (power), 83 GND (power), 90 VCC (power), 91 GND (power), 98 GND (power), 101 VCC (power), 106 GND (power), 119 GND (power), 120 DONE (io), 121 VCC (power), 122 ~{PROGRAM} (in), 135 GND (power), 140 VCC (power), 143 GND (power), 150 VCC (power), 151 GND (power), 158 GND (power), 161 VCC (power), 166 GND (power), 179 CCLK (io), 180 VCC (power), 181 O, TDO (out), 182 GND (power), 195 NC, 196 GND (power), 201 VCC (power), 204 GND (power), 211 GND (power), 212 VCC (power), 219 GND (power), 222 VCC (power), 227 GND (power), 240 VCC (power)


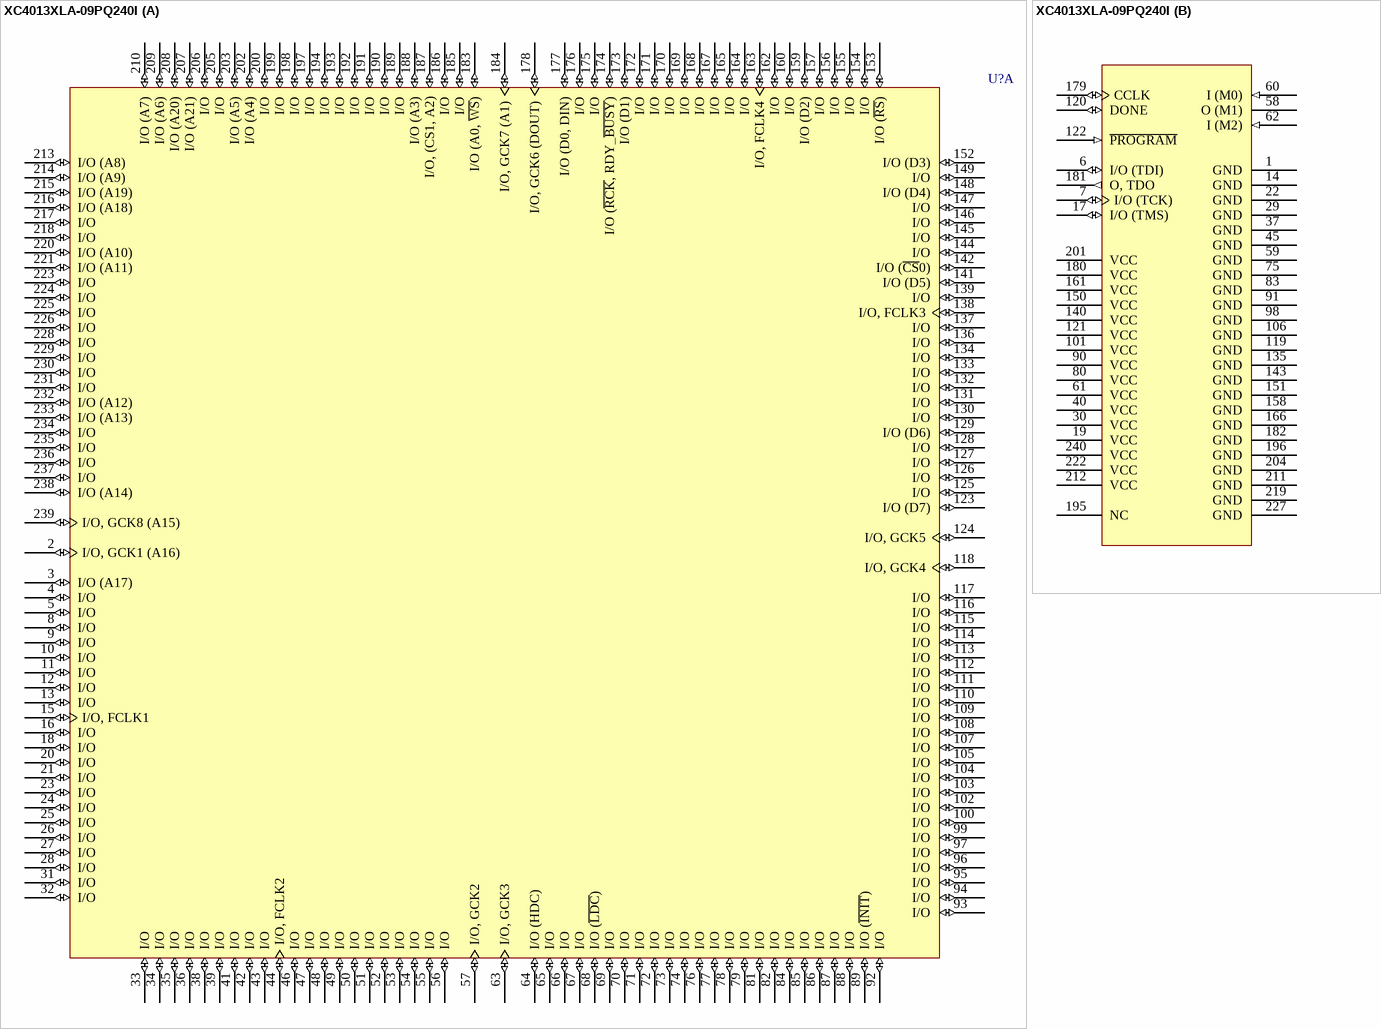
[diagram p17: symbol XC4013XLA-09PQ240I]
## XC4013XLA-09PQ240I
designator U?
XC4000XLA FPGA, 192 I/Os, 240-Pin PQFP, Speed Grade 9, Industrial Grade
footprint PQ240_N (Shrink QFP, 240-Leads, Body 32x32mm, Pitch 0.5mm, IPC Medium Density)
footprint PQ240_L (Shrink QFP, 240-Leads, Body 32x32mm, Pitch 0.5mm, IPC High Density)
footprint PQ240_M (Shrink QFP, 240-Leads, Body 32x32mm, Pitch 0.5mm, IPC Low Density)
part A pins: 2 I/O, GCK1 (A16) (io), 3 I/O (A17) (io), 4 I/O (io), 5 I/O (io), 8 I/O (io), 9 I/O (io), 10 I/O (io), 11 I/O (io), 12 I/O (io), 13 I/O (io), 15 I/O, FCLK1 (io), 16 I/O (io), 18 I/O (io), 20 I/O (io), 21 I/O (io), 23 I/O (io), 24 I/O (io), 25 I/O (io), 26 I/O (io), 27 I/O (io), 28 I/O (io), 31 I/O (io), 32 I/O (io), 33 I/O (io), 34 I/O (io), 35 I/O (io), 36 I/O (io), 38 I/O (io), 39 I/O (io), 41 I/O (io), 42 I/O (io), 43 I/O (io), 44 I/O, FCLK2 (io), 46 I/O (io), 47 I/O (io), 48 I/O (io), 49 I/O (io), 50 I/O (io), 51 I/O (io), 52 I/O (io), 53 I/O (io), 54 I/O (io), 55 I/O (io), 56 I/O (io), 57 I/O, GCK2 (io), 63 I/O, GCK3 (io), 64 I/O (HDC) (io), 65 I/O (io), 66 I/O (io), 67 I/O (io), 68 I/O (~{LDC}) (io), 69 I/O (io), 70 I/O (io), 71 I/O (io), 72 I/O (io), 73 I/O (io), 74 I/O (io), 76 I/O (io), 77 I/O (io), 78 I/O (io), 79 I/O (io), 81 I/O (io), 82 I/O (io), 84 I/O (io), 85 I/O (io), 86 I/O (io), 87 I/O (io), 88 I/O (io), 89 I/O (~{INIT}) (io), 92 I/O (io), 93 I/O (io), 94 I/O (io), 95 I/O (io), 96 I/O (io), 97 I/O (io), 99 I/O (io), 100 I/O (io), 102 I/O (io), 103 I/O (io), 104 I/O (io), 105 I/O (io), 107 I/O (io), 108 I/O (io), 109 I/O (io), 110 I/O (io), 111 I/O (io), 112 I/O (io), 113 I/O (io), 114 I/O (io), 115 I/O (io), 116 I/O (io), 117 I/O (io), 118 I/O, GCK4 (io), 123 I/O (D7) (io), 124 I/O, GCK5 (io), 125 I/O (io), 126 I/O (io), 127 I/O (io), 128 I/O (io), 129 I/O (D6) (io), 130 I/O (io), 131 I/O (io), 132 I/O (io), 133 I/O (io), 134 I/O (io), 136 I/O (io), 137 I/O (io), 138 I/O, FCLK3 (io), 139 I/O (io), 141 I/O (D5) (io), 142 I/O (~{CS}0) (io), 144 I/O (io), 145 I/O (io), 146 I/O (io), 147 I/O (io), 148 I/O (D4) (io), 149 I/O (io), 152 I/O (D3) (io), 153 I/O (~{RS}) (io), 154 I/O (io), 155 I/O (io), 156 I/O (io), 157 I/O (io), 159 I/O (D2) (io), 160 I/O (io), 162 I/O (io), 163 I/O, FCLK4 (io), 164 I/O (io), 165 I/O (io), 167 I/O (io), 168 I/O (io), 169 I/O (io), 170 I/O (io), 171 I/O (io), 172 I/O (io), 173 I/O (D1) (io), 174 I/O (~{RCK}, RDY_~{BUSY}) (io), 175 I/O (io), 176 I/O (io), 177 I/O (D0, DIN) (io), 178 I/O, GCK6 (DOUT) (io), 183 I/O (A0, ~{WS}) (io), 184 I/O, GCK7 (A1) (io), 185 I/O (io), 186 I/O (io), 187 I/O, (CS1, A2) (io), 188 I/O (A3) (io), 189 I/O (io), 190 I/O (io), 191 I/O (io), 192 I/O (io), 193 I/O (io), 194 I/O (io), 197 I/O (io), 198 I/O (io), 199 I/O (io), 200 I/O (io), 202 I/O (A4) (io), 203 I/O (A5) (io), 205 I/O (io), 206 I/O (io), 207 I/O (A21) (io), 208 I/O (A20) (io), 209 I/O (A6) (io), 210 I/O (A7) (io), 213 I/O (A8) (io), 214 I/O (A9) (io), 215 I/O (A19) (io), 216 I/O (A18) (io), 217 I/O (io), 218 I/O (io), 220 I/O (A10) (io), 221 I/O (A11) (io), 223 I/O (io), 224 I/O (io), 225 I/O (io), 226 I/O (io), 228 I/O (io), 229 I/O (io), 230 I/O (io), 231 I/O (io), 232 I/O (A12) (io), 233 I/O (A13) (io), 234 I/O (io), 235 I/O (io), 236 I/O (io), 237 I/O (io), 238 I/O (A14) (io), 239 I/O, GCK8 (A15) (io)
part B pins: 1 GND (power), 6 I/O (TDI) (io), 7 I/O (TCK) (io), 14 GND (power), 17 I/O (TMS) (io), 19 VCC (power), 22 GND (power), 29 GND (power), 30 VCC (power), 37 GND (power), 40 VCC (power), 45 GND (power), 58 O (M1), 59 GND (power), 60 I (M0) (in), 61 VCC (power), 62 I (M2) (in), 75 GND (power), 80 VCC (power), 83 GND (power), 90 VCC (power), 91 GND (power), 98 GND (power), 101 VCC (power), 106 GND (power), 119 GND (power), 120 DONE (io), 121 VCC (power), 122 ~{PROGRAM} (in), 135 GND (power), 140 VCC (power), 143 GND (power), 150 VCC (power), 151 GND (power), 158 GND (power), 161 VCC (power), 166 GND (power), 179 CCLK (io), 180 VCC (power), 181 O, TDO (out), 182 GND (power), 195 NC, 196 GND (power), 201 VCC (power), 204 GND (power), 211 GND (power), 212 VCC (power), 219 GND (power), 222 VCC (power), 227 GND (power), 240 VCC (power)


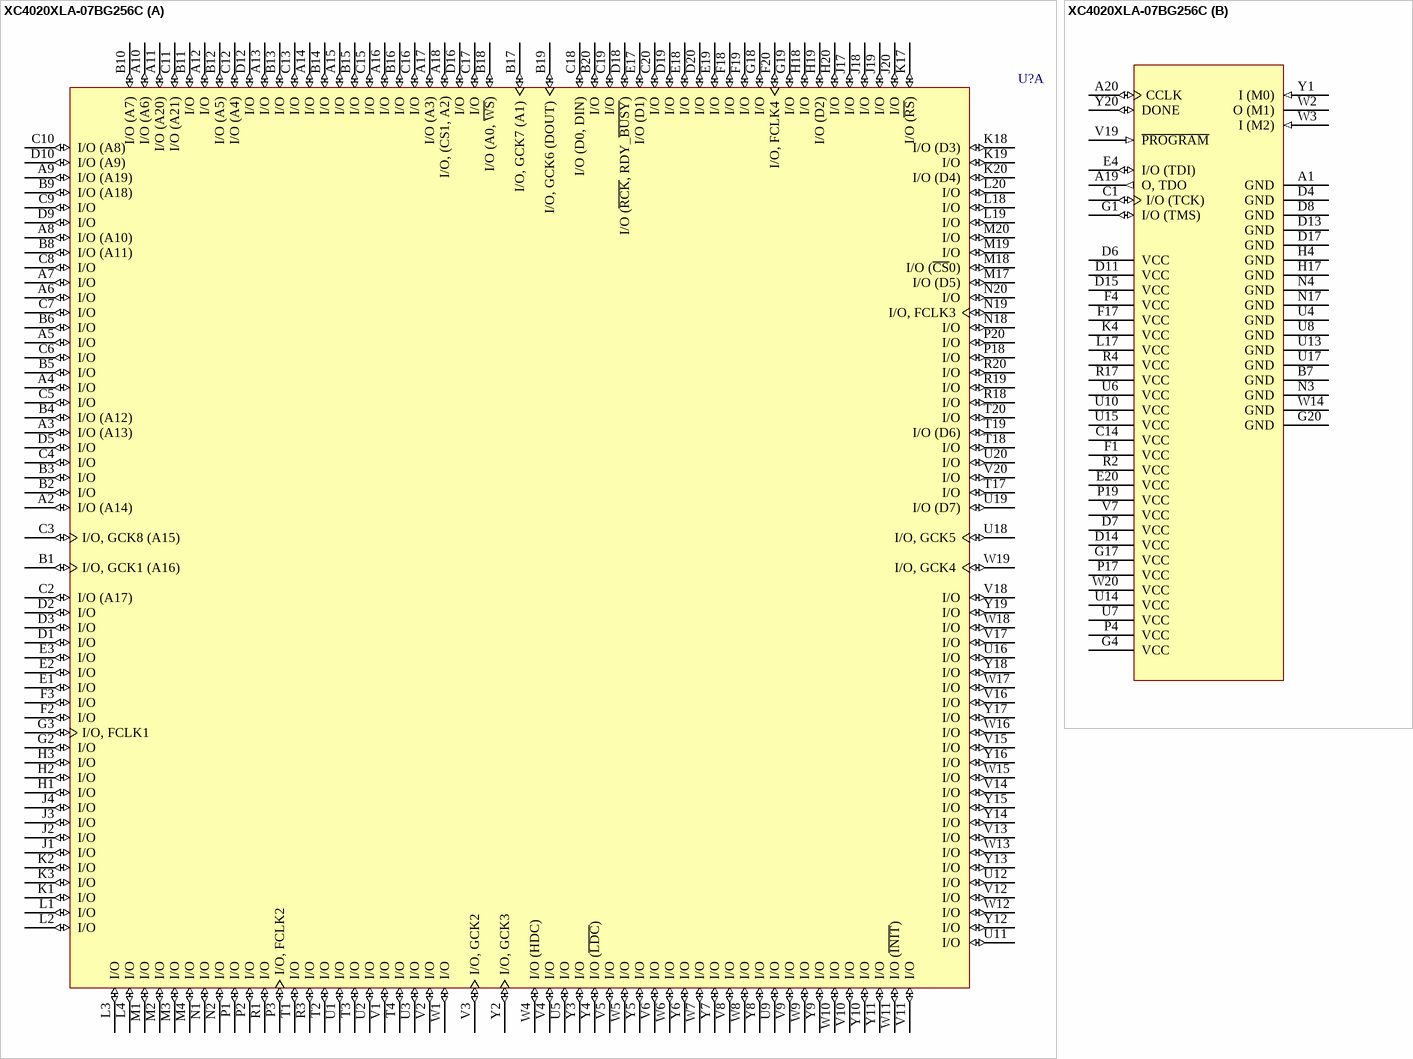
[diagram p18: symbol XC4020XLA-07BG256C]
## XC4020XLA-07BG256C
designator U?
XC4000XLA FPGA, 205 I/Os, 256-Ball BGA, Speed Grade 7, Commercial Grade
footprint BG256 (BGA, 256-Leads, Body 27x27mm, Pitch 1.27mm)
part A pins: A2 I/O (A14) (io), A3 I/O (A13) (io), A4 I/O (io), A5 I/O (io), A6 I/O (io), A7 I/O (io), A8 I/O (A10) (io), A9 I/O (A19) (io), A10 I/O (A6) (io), A11 I/O (A20) (io), A12 I/O (io), A13 I/O (io), A14 I/O (io), A15 I/O (io), A16 I/O (io), A17 I/O (A3) (io), A18 I/O, (CS1, A2) (io), B1 I/O, GCK1 (A16) (io), B2 I/O (io), B3 I/O (io), B4 I/O (A12) (io), B5 I/O (io), B6 I/O (io), B8 I/O (A11) (io), B9 I/O (A18) (io), B10 I/O (A7) (io), B11 I/O (io), B12 I/O (A5) (io), B13 I/O (io), B14 I/O (io), B15 I/O (io), B16 I/O (io), B17 I/O, GCK7 (A1) (io), B18 I/O (A0, ~{WS}) (io), B19 I/O, GCK6 (DOUT) (io), B20 I/O (io), C2 I/O (A17) (io), C3 I/O, GCK8 (A15) (io), C4 I/O (io), C5 I/O (io), C6 I/O (io), C7 I/O (io), C8 I/O (io), C9 I/O (io), C10 I/O (A8) (io), C11 I/O (A21) (io), C12 I/O (A4) (io), C13 I/O (io), C15 I/O (io), C16 I/O (io), C17 I/O (io), C18 I/O (D0, DIN) (io), C19 I/O (io), C20 I/O (io), D1 I/O (io), D2 I/O (io), D3 I/O (io), D5 I/O (io), D9 I/O (io), D10 I/O (A9) (io), D12 I/O (io), D16 I/O (io), D18 I/O (~{RCK}, RDY_~{BUSY}) (io), D19 I/O (io), D20 I/O (io), E1 I/O (io), E2 I/O (io), E3 I/O (io), E17 I/O (D1) (io), E18 I/O (io), E19 I/O (io), F2 I/O (io), F3 I/O (io), F18 I/O (io), F19 I/O (io), F20 I/O, FCLK4 (io), G2 I/O (io), G3 I/O, FCLK1 (io), G18 I/O (io), G19 I/O (io), H1 I/O (io), H2 I/O (io), H3 I/O (io), H18 I/O (io), H19 I/O (D2) (io), H20 I/O (io), J1 I/O (io), J2 I/O (io), J3 I/O (io), J4 I/O (io), J17 I/O (io), J18 I/O (io), J19 I/O (io), J20 I/O (io), K1 I/O (io), K2 I/O (io), K3 I/O (io), K17 I/O (~{RS}) (io), K18 I/O (D3) (io), K19 I/O (io), K20 I/O (D4) (io), L1 I/O (io), L2 I/O (io), L3 I/O (io), L4 I/O (io), L18 I/O (io), L19 I/O (io), L20 I/O (io), M1 I/O (io), M2 I/O (io), M3 I/O (io), M4 I/O (io), M17 I/O (D5) (io), M18 I/O (~{CS}0) (io), M19 I/O (io), M20 I/O (io), N1 I/O (io), N2 I/O (io), N18 I/O (io), N19 I/O, FCLK3 (io), N20 I/O (io), P1 I/O (io), P2 I/O (io), P3 I/O, FCLK2 (io), P18 I/O (io), P20 I/O (io), R1 I/O (io), R3 I/O (io), R18 I/O (io), R19 I/O (io), R20 I/O (io), T1 I/O (io), T2 I/O (io), T3 I/O (io), T4 I/O (io), T17 I/O (io), T18 I/O (io), T19 I/O (D6) (io), T20 I/O (io), U1 I/O (io), U2 I/O (io), U3 I/O (io), U5 I/O (io), U9 I/O (io), U11 I/O (io), U12 I/O (io), U16 I/O (io), U18 I/O, GCK5 (io), U19 I/O (D7) (io), U20 I/O (io), V1 I/O (io), V2 I/O (io), V3 I/O, GCK2 (io), V4 I/O (io), V5 I/O (io), V6 I/O (io), V8 I/O (io), V9 I/O (io), V10 I/O (io), V11 I/O (io), V12 I/O (io), V13 I/O (io), V14 I/O (io), V15 I/O (io), V16 I/O (io), V17 I/O (io), V18 I/O (io), V20 I/O (io), W1 I/O (io), W4 I/O (HDC) (io), W5 I/O (io), W6 I/O (io), W7 I/O (io), W8 I/O (io), W9 I/O (io), W10 I/O (io), W11 I/O (~{INIT}) (io), W12 I/O (io), W13 I/O (io), W15 I/O (io), W16 I/O (io), W17 I/O (io), W18 I/O (io), W19 I/O, GCK4 (io), Y2 I/O, GCK3 (io), Y3 I/O (io), Y4 I/O (~{LDC}) (io), Y5 I/O (io), Y6 I/O (io), Y7 I/O (io), Y8 I/O (io), Y9 I/O (io), Y10 I/O (io), Y11 I/O (io), Y12 I/O (io), Y13 I/O (io), Y14 I/O (io), Y15 I/O (io), Y16 I/O (io), Y17 I/O (io), Y18 I/O (io), Y19 I/O (io)
part B pins: A1 GND (power), A19 O, TDO (out), A20 CCLK (io), B7 GND (power), C1 I/O (TCK) (io), C14 VCC (power), D4 GND (power), D6 VCC (power), D7 VCC (power), D8 GND (power), D11 VCC (power), D13 GND (power), D14 VCC (power), D15 VCC (power), D17 GND (power), E4 I/O (TDI) (io), E20 VCC (power), F1 VCC (power), F4 VCC (power), F17 VCC (power), G1 I/O (TMS) (io), G4 VCC (power), G17 VCC (power), G20 GND (power), H4 GND (power), H17 GND (power), K4 VCC (power), L17 VCC (power), N3 GND (power), N4 GND (power), N17 GND (power), P4 VCC (power), P17 VCC (power), P19 VCC (power), R2 VCC (power), R4 VCC (power), R17 VCC (power), U4 GND (power), U6 VCC (power), U7 VCC (power), U8 GND (power), U10 VCC (power), U13 GND (power), U14 VCC (power), U15 VCC (power), U17 GND (power), V7 VCC (power), V19 ~{PROGRAM} (in), W2 O (M1), W3 I (M2) (in), W14 GND (power), W20 VCC (power), Y1 I (M0) (in), Y20 DONE (io)


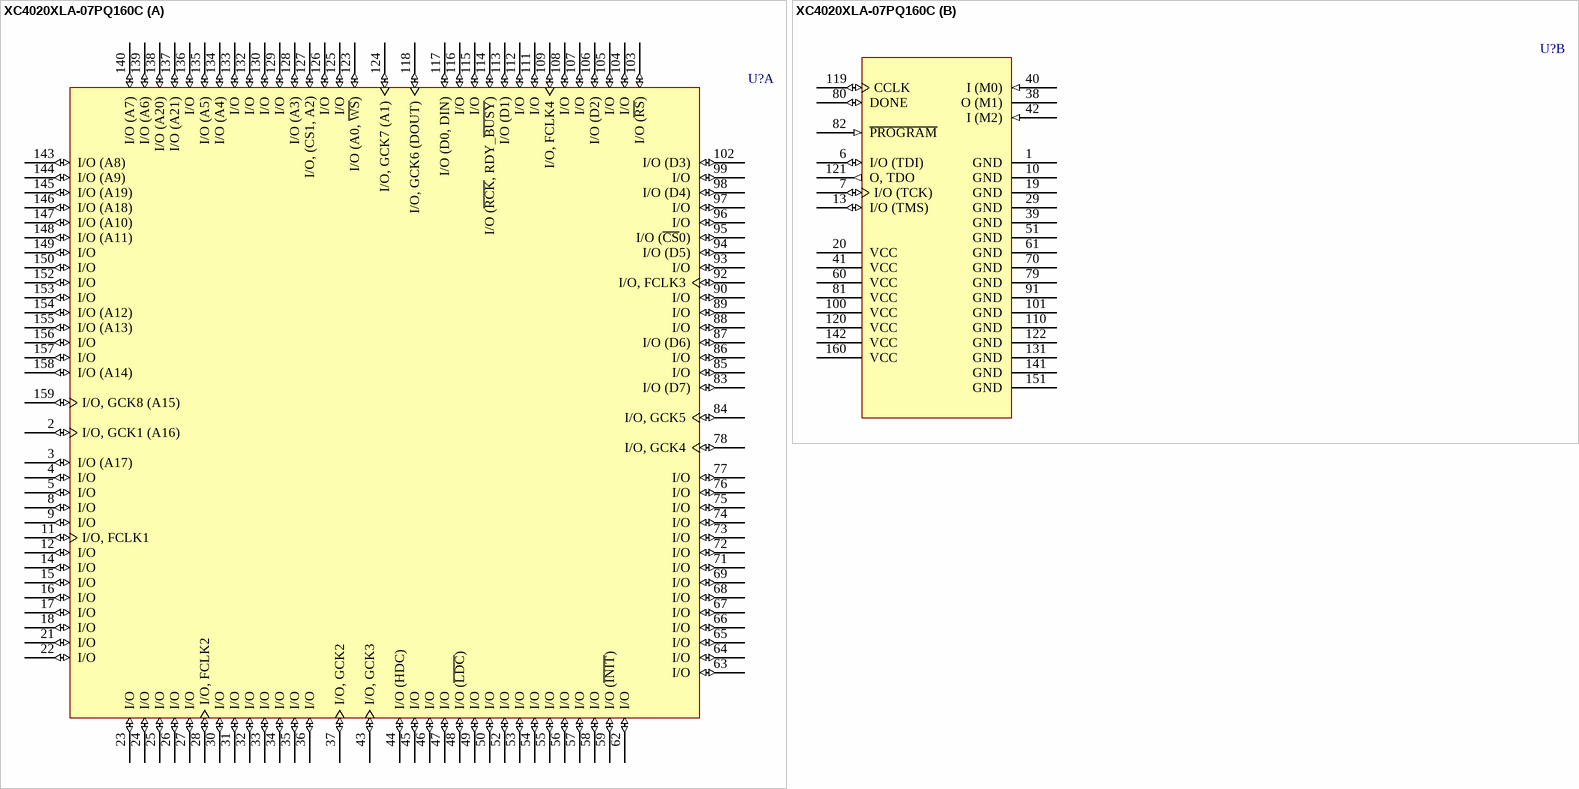
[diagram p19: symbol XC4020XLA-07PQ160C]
## XC4020XLA-07PQ160C
designator U?
XC4000XLA FPGA, 129 I/Os, 160-Pin PQFP, Speed Grade 7, Commercial Grade
footprint PQ160_N (QFP, 160-Leads, Body 28x28mm, Pitch 0.65mm, IPC Medium Density)
footprint PQ160_L (QFP, 160-Leads, Body 28x28mm, Pitch 0.65mm, IPC High Density)
footprint PQ160_M (QFP, 160-Leads, Body 28x28mm, Pitch 0.65mm, IPC Low Density)
part A pins: 2 I/O, GCK1 (A16) (io), 3 I/O (A17) (io), 4 I/O (io), 5 I/O (io), 8 I/O (io), 9 I/O (io), 11 I/O, FCLK1 (io), 12 I/O (io), 14 I/O (io), 15 I/O (io), 16 I/O (io), 17 I/O (io), 18 I/O (io), 21 I/O (io), 22 I/O (io), 23 I/O (io), 24 I/O (io), 25 I/O (io), 26 I/O (io), 27 I/O (io), 28 I/O, FCLK2 (io), 30 I/O (io), 31 I/O (io), 32 I/O (io), 33 I/O (io), 34 I/O (io), 35 I/O (io), 36 I/O (io), 37 I/O, GCK2 (io), 43 I/O, GCK3 (io), 44 I/O (HDC) (io), 45 I/O (io), 46 I/O (io), 47 I/O (io), 48 I/O (~{LDC}) (io), 49 I/O (io), 50 I/O (io), 52 I/O (io), 53 I/O (io), 54 I/O (io), 55 I/O (io), 56 I/O (io), 57 I/O (io), 58 I/O (io), 59 I/O (~{INIT}) (io), 62 I/O (io), 63 I/O (io), 64 I/O (io), 65 I/O (io), 66 I/O (io), 67 I/O (io), 68 I/O (io), 69 I/O (io), 71 I/O (io), 72 I/O (io), 73 I/O (io), 74 I/O (io), 75 I/O (io), 76 I/O (io), 77 I/O (io), 78 I/O, GCK4 (io), 83 I/O (D7) (io), 84 I/O, GCK5 (io), 85 I/O (io), 86 I/O (io), 87 I/O (D6) (io), 88 I/O (io), 89 I/O (io), 90 I/O (io), 92 I/O, FCLK3 (io), 93 I/O (io), 94 I/O (D5) (io), 95 I/O (~{CS}0) (io), 96 I/O (io), 97 I/O (io), 98 I/O (D4) (io), 99 I/O (io), 102 I/O (D3) (io), 103 I/O (~{RS}) (io), 104 I/O (io), 105 I/O (io), 106 I/O (D2) (io), 107 I/O (io), 108 I/O (io), 109 I/O, FCLK4 (io), 111 I/O (io), 112 I/O (io), 113 I/O (D1) (io), 114 I/O (~{RCK}, RDY_~{BUSY}) (io), 115 I/O (io), 116 I/O (io), 117 I/O (D0, DIN) (io), 118 I/O, GCK6 (DOUT) (io), 123 I/O (A0, ~{WS}) (io), 124 I/O, GCK7 (A1) (io), 125 I/O (io), 126 I/O (io), 127 I/O, (CS1, A2) (io), 128 I/O (A3) (io), 129 I/O (io), 130 I/O (io), 132 I/O (io), 133 I/O (io), 134 I/O (A4) (io), 135 I/O (A5) (io), 136 I/O (io), 137 I/O (A21) (io), 138 I/O (A20) (io), 139 I/O (A6) (io), 140 I/O (A7) (io), 143 I/O (A8) (io), 144 I/O (A9) (io), 145 I/O (A19) (io), 146 I/O (A18) (io), 147 I/O (A10) (io), 148 I/O (A11) (io), 149 I/O (io), 150 I/O (io), 152 I/O (io), 153 I/O (io), 154 I/O (A12) (io), 155 I/O (A13) (io), 156 I/O (io), 157 I/O (io), 158 I/O (A14) (io), 159 I/O, GCK8 (A15) (io)
part B pins: 1 GND (power), 6 I/O (TDI) (io), 7 I/O (TCK) (io), 10 GND (power), 13 I/O (TMS) (io), 19 GND (power), 20 VCC (power), 29 GND (power), 38 O (M1), 39 GND (power), 40 I (M0) (in), 41 VCC (power), 42 I (M2) (in), 51 GND (power), 60 VCC (power), 61 GND (power), 70 GND (power), 79 GND (power), 80 DONE (io), 81 VCC (power), 82 ~{PROGRAM} (in), 91 GND (power), 100 VCC (power), 101 GND (power), 110 GND (power), 119 CCLK (io), 120 VCC (power), 121 O, TDO (out), 122 GND (power), 131 GND (power), 141 GND (power), 142 VCC (power), 151 GND (power), 160 VCC (power)


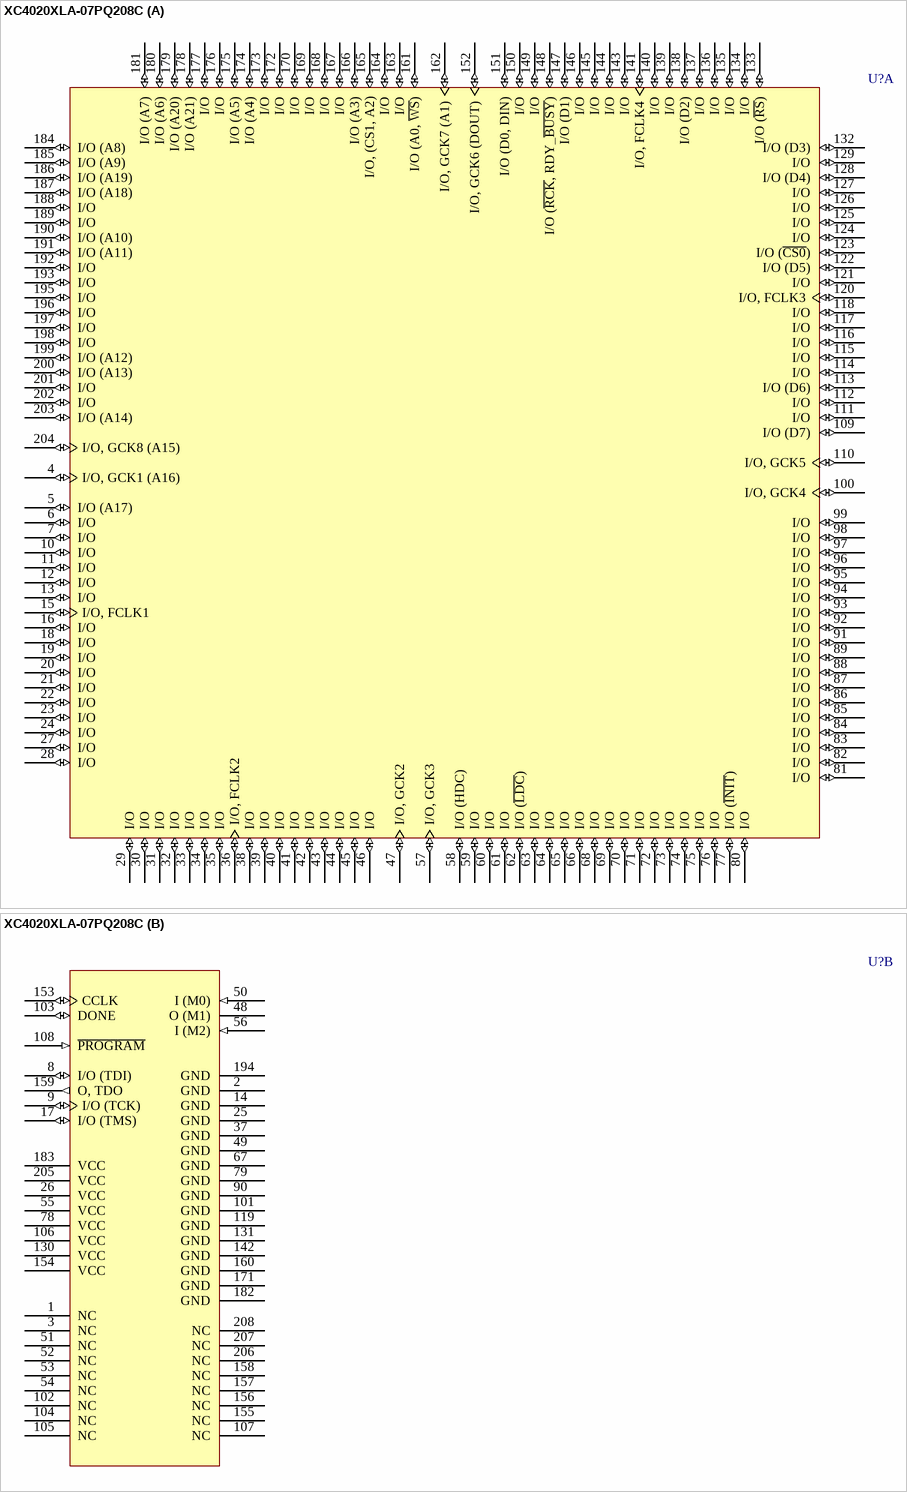
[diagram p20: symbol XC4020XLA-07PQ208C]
## XC4020XLA-07PQ208C
designator U?
XC4000XLA FPGA, 160 I/Os, 208-Pin PQFP, Speed Grade 7, Commercial Grade
footprint PQ208_N (Shrink QFP, 208-Leads, Body 28x28mm, Pitch 0.5mm, IPC Medium Density)
footprint PQ208_L (Shrink QFP, 208-Leads, Body 28x28mm, Pitch 0.5mm, IPC High Density)
footprint PQ208_M (Shrink QFP, 208-Leads, Body 28x28mm, Pitch 0.5mm, IPC Low Density)
part A pins: 4 I/O, GCK1 (A16) (io), 5 I/O (A17) (io), 6 I/O (io), 7 I/O (io), 10 I/O (io), 11 I/O (io), 12 I/O (io), 13 I/O (io), 15 I/O, FCLK1 (io), 16 I/O (io), 18 I/O (io), 19 I/O (io), 20 I/O (io), 21 I/O (io), 22 I/O (io), 23 I/O (io), 24 I/O (io), 27 I/O (io), 28 I/O (io), 29 I/O (io), 30 I/O (io), 31 I/O (io), 32 I/O (io), 33 I/O (io), 34 I/O (io), 35 I/O (io), 36 I/O, FCLK2 (io), 38 I/O (io), 39 I/O (io), 40 I/O (io), 41 I/O (io), 42 I/O (io), 43 I/O (io), 44 I/O (io), 45 I/O (io), 46 I/O (io), 47 I/O, GCK2 (io), 57 I/O, GCK3 (io), 58 I/O (HDC) (io), 59 I/O (io), 60 I/O (io), 61 I/O (io), 62 I/O (~{LDC}) (io), 63 I/O (io), 64 I/O (io), 65 I/O (io), 66 I/O (io), 68 I/O (io), 69 I/O (io), 70 I/O (io), 71 I/O (io), 72 I/O (io), 73 I/O (io), 74 I/O (io), 75 I/O (io), 76 I/O (io), 77 I/O (~{INIT}) (io), 80 I/O (io), 81 I/O (io), 82 I/O (io), 83 I/O (io), 84 I/O (io), 85 I/O (io), 86 I/O (io), 87 I/O (io), 88 I/O (io), 89 I/O (io), 91 I/O (io), 92 I/O (io), 93 I/O (io), 94 I/O (io), 95 I/O (io), 96 I/O (io), 97 I/O (io), 98 I/O (io), 99 I/O (io), 100 I/O, GCK4 (io), 109 I/O (D7) (io), 110 I/O, GCK5 (io), 111 I/O (io), 112 I/O (io), 113 I/O (D6) (io), 114 I/O (io), 115 I/O (io), 116 I/O (io), 117 I/O (io), 118 I/O (io), 120 I/O, FCLK3 (io), 121 I/O (io), 122 I/O (D5) (io), 123 I/O (~{CS0}) (io), 124 I/O (io), 125 I/O (io), 126 I/O (io), 127 I/O (io), 128 I/O (D4) (io), 129 I/O (io), 132 I/O (D3) (io), 133 I/O (~{RS}) (io), 134 I/O (io), 135 I/O (io), 136 I/O (io), 137 I/O (io), 138 I/O (D2) (io), 139 I/O (io), 140 I/O (io), 141 I/O, FCLK4 (io), 143 I/O (io), 144 I/O (io), 145 I/O (io), 146 I/O (io), 147 I/O (D1) (io), 148 I/O (~{RCK}, RDY_~{BUSY}) (io), 149 I/O (io), 150 I/O (io), 151 I/O (D0, DIN) (io), 152 I/O, GCK6 (DOUT) (io), 161 I/O (A0, ~{WS}) (io), 162 I/O, GCK7 (A1) (io), 163 I/O (io), 164 I/O (io), 165 I/O, (CS1, A2) (io), 166 I/O (A3) (io), 167 I/O (io), 168 I/O (io), 169 I/O (io), 170 I/O (io), 172 I/O (io), 173 I/O (io), 174 I/O (A4) (io), 175 I/O (A5) (io), 176 I/O (io), 177 I/O (io), 178 I/O (A21) (io), 179 I/O (A20) (io), 180 I/O (A6) (io), 181 I/O (A7) (io), 184 I/O (A8) (io), 185 I/O (A9) (io), 186 I/O (A19) (io), 187 I/O (A18) (io), 188 I/O (io), 189 I/O (io), 190 I/O (A10) (io), 191 I/O (A11) (io), 192 I/O (io), 193 I/O (io), 195 I/O (io), 196 I/O (io), 197 I/O (io), 198 I/O (io), 199 I/O (A12) (io), 200 I/O (A13) (io), 201 I/O (io), 202 I/O (io), 203 I/O (A14) (io), 204 I/O, GCK8 (A15) (io)
part B pins: 1 NC, 2 GND (power), 3 NC, 8 I/O (TDI) (io), 9 I/O (TCK) (io), 14 GND (power), 17 I/O (TMS) (io), 25 GND (power), 26 VCC (power), 37 GND (power), 48 O (M1), 49 GND (power), 50 I (M0) (in), 51 NC, 52 NC, 53 NC, 54 NC, 55 VCC (power), 56 I (M2) (in), 67 GND (power), 78 VCC (power), 79 GND (power), 90 GND (power), 101 GND (power), 102 NC, 103 DONE (io), 104 NC, 105 NC, 106 VCC (power), 107 NC, 108 ~{PROGRAM} (in), 119 GND (power), 130 VCC (power), 131 GND (power), 142 GND (power), 153 CCLK (io), 154 VCC (power), 155 NC, 156 NC, 157 NC, 158 NC, 159 O, TDO (out), 160 GND (power), 171 GND (power), 182 GND (power), 183 VCC (power), 194 GND (power), 205 VCC (power), 206 NC, 207 NC, 208 NC


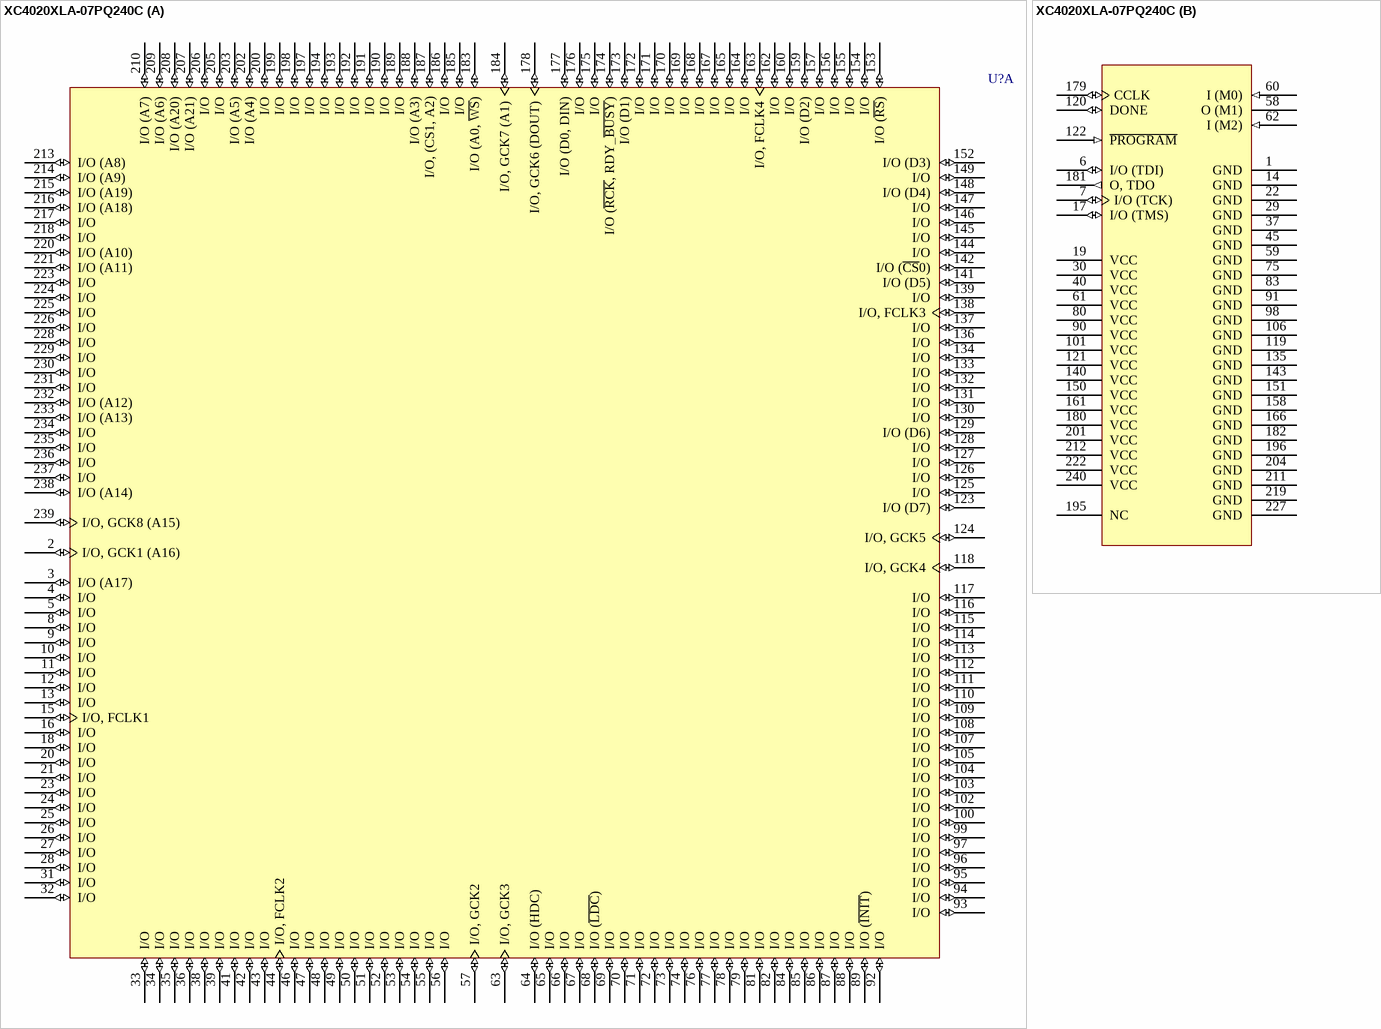
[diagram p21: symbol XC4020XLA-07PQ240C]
## XC4020XLA-07PQ240C
designator U?
XC4000XLA FPGA, 193 I/Os, 240-Pin PQFP, Speed Grade 7, Commercial Grade
footprint PQ240_N (Shrink QFP, 240-Leads, Body 32x32mm, Pitch 0.5mm, IPC Medium Density)
footprint PQ240_L (Shrink QFP, 240-Leads, Body 32x32mm, Pitch 0.5mm, IPC High Density)
footprint PQ240_M (Shrink QFP, 240-Leads, Body 32x32mm, Pitch 0.5mm, IPC Low Density)
part A pins: 2 I/O, GCK1 (A16) (io), 3 I/O (A17) (io), 4 I/O (io), 5 I/O (io), 8 I/O (io), 9 I/O (io), 10 I/O (io), 11 I/O (io), 12 I/O (io), 13 I/O (io), 15 I/O, FCLK1 (io), 16 I/O (io), 18 I/O (io), 20 I/O (io), 21 I/O (io), 23 I/O (io), 24 I/O (io), 25 I/O (io), 26 I/O (io), 27 I/O (io), 28 I/O (io), 31 I/O (io), 32 I/O (io), 33 I/O (io), 34 I/O (io), 35 I/O (io), 36 I/O (io), 38 I/O (io), 39 I/O (io), 41 I/O (io), 42 I/O (io), 43 I/O (io), 44 I/O, FCLK2 (io), 46 I/O (io), 47 I/O (io), 48 I/O (io), 49 I/O (io), 50 I/O (io), 51 I/O (io), 52 I/O (io), 53 I/O (io), 54 I/O (io), 55 I/O (io), 56 I/O (io), 57 I/O, GCK2 (io), 63 I/O, GCK3 (io), 64 I/O (HDC) (io), 65 I/O (io), 66 I/O (io), 67 I/O (io), 68 I/O (~{LDC}) (io), 69 I/O (io), 70 I/O (io), 71 I/O (io), 72 I/O (io), 73 I/O (io), 74 I/O (io), 76 I/O (io), 77 I/O (io), 78 I/O (io), 79 I/O (io), 81 I/O (io), 82 I/O (io), 84 I/O (io), 85 I/O (io), 86 I/O (io), 87 I/O (io), 88 I/O (io), 89 I/O (~{INIT}) (io), 92 I/O (io), 93 I/O (io), 94 I/O (io), 95 I/O (io), 96 I/O (io), 97 I/O (io), 99 I/O (io), 100 I/O (io), 102 I/O (io), 103 I/O (io), 104 I/O (io), 105 I/O (io), 107 I/O (io), 108 I/O (io), 109 I/O (io), 110 I/O (io), 111 I/O (io), 112 I/O (io), 113 I/O (io), 114 I/O (io), 115 I/O (io), 116 I/O (io), 117 I/O (io), 118 I/O, GCK4 (io), 123 I/O (D7) (io), 124 I/O, GCK5 (io), 125 I/O (io), 126 I/O (io), 127 I/O (io), 128 I/O (io), 129 I/O (D6) (io), 130 I/O (io), 131 I/O (io), 132 I/O (io), 133 I/O (io), 134 I/O (io), 136 I/O (io), 137 I/O (io), 138 I/O, FCLK3 (io), 139 I/O (io), 141 I/O (D5) (io), 142 I/O (~{CS}0) (io), 144 I/O (io), 145 I/O (io), 146 I/O (io), 147 I/O (io), 148 I/O (D4) (io), 149 I/O (io), 152 I/O (D3) (io), 153 I/O (~{RS}) (io), 154 I/O (io), 155 I/O (io), 156 I/O (io), 157 I/O (io), 159 I/O (D2) (io), 160 I/O (io), 162 I/O (io), 163 I/O, FCLK4 (io), 164 I/O (io), 165 I/O (io), 167 I/O (io), 168 I/O (io), 169 I/O (io), 170 I/O (io), 171 I/O (io), 172 I/O (io), 173 I/O (D1) (io), 174 I/O (~{RCK}, RDY_~{BUSY}) (io), 175 I/O (io), 176 I/O (io), 177 I/O (D0, DIN) (io), 178 I/O, GCK6 (DOUT) (io), 183 I/O (A0, ~{WS}) (io), 184 I/O, GCK7 (A1) (io), 185 I/O (io), 186 I/O (io), 187 I/O, (CS1, A2) (io), 188 I/O (A3) (io), 189 I/O (io), 190 I/O (io), 191 I/O (io), 192 I/O (io), 193 I/O (io), 194 I/O (io), 197 I/O (io), 198 I/O (io), 199 I/O (io), 200 I/O (io), 202 I/O (A4) (io), 203 I/O (A5) (io), 205 I/O (io), 206 I/O (io), 207 I/O (A21) (io), 208 I/O (A20) (io), 209 I/O (A6) (io), 210 I/O (A7) (io), 213 I/O (A8) (io), 214 I/O (A9) (io), 215 I/O (A19) (io), 216 I/O (A18) (io), 217 I/O (io), 218 I/O (io), 220 I/O (A10) (io), 221 I/O (A11) (io), 223 I/O (io), 224 I/O (io), 225 I/O (io), 226 I/O (io), 228 I/O (io), 229 I/O (io), 230 I/O (io), 231 I/O (io), 232 I/O (A12) (io), 233 I/O (A13) (io), 234 I/O (io), 235 I/O (io), 236 I/O (io), 237 I/O (io), 238 I/O (A14) (io), 239 I/O, GCK8 (A15) (io)
part B pins: 1 GND (power), 6 I/O (TDI) (io), 7 I/O (TCK) (io), 14 GND (power), 17 I/O (TMS) (io), 19 VCC (power), 22 GND (power), 29 GND (power), 30 VCC (power), 37 GND (power), 40 VCC (power), 45 GND (power), 58 O (M1), 59 GND (power), 60 I (M0) (in), 61 VCC (power), 62 I (M2) (in), 75 GND (power), 80 VCC (power), 83 GND (power), 90 VCC (power), 91 GND (power), 98 GND (power), 101 VCC (power), 106 GND (power), 119 GND (power), 120 DONE (io), 121 VCC (power), 122 ~{PROGRAM} (in), 135 GND (power), 140 VCC (power), 143 GND (power), 150 VCC (power), 151 GND (power), 158 GND (power), 161 VCC (power), 166 GND (power), 179 CCLK (io), 180 VCC (power), 181 O, TDO (out), 182 GND (power), 195 NC, 196 GND (power), 201 VCC (power), 204 GND (power), 211 GND (power), 212 VCC (power), 219 GND (power), 222 VCC (power), 227 GND (power), 240 VCC (power)


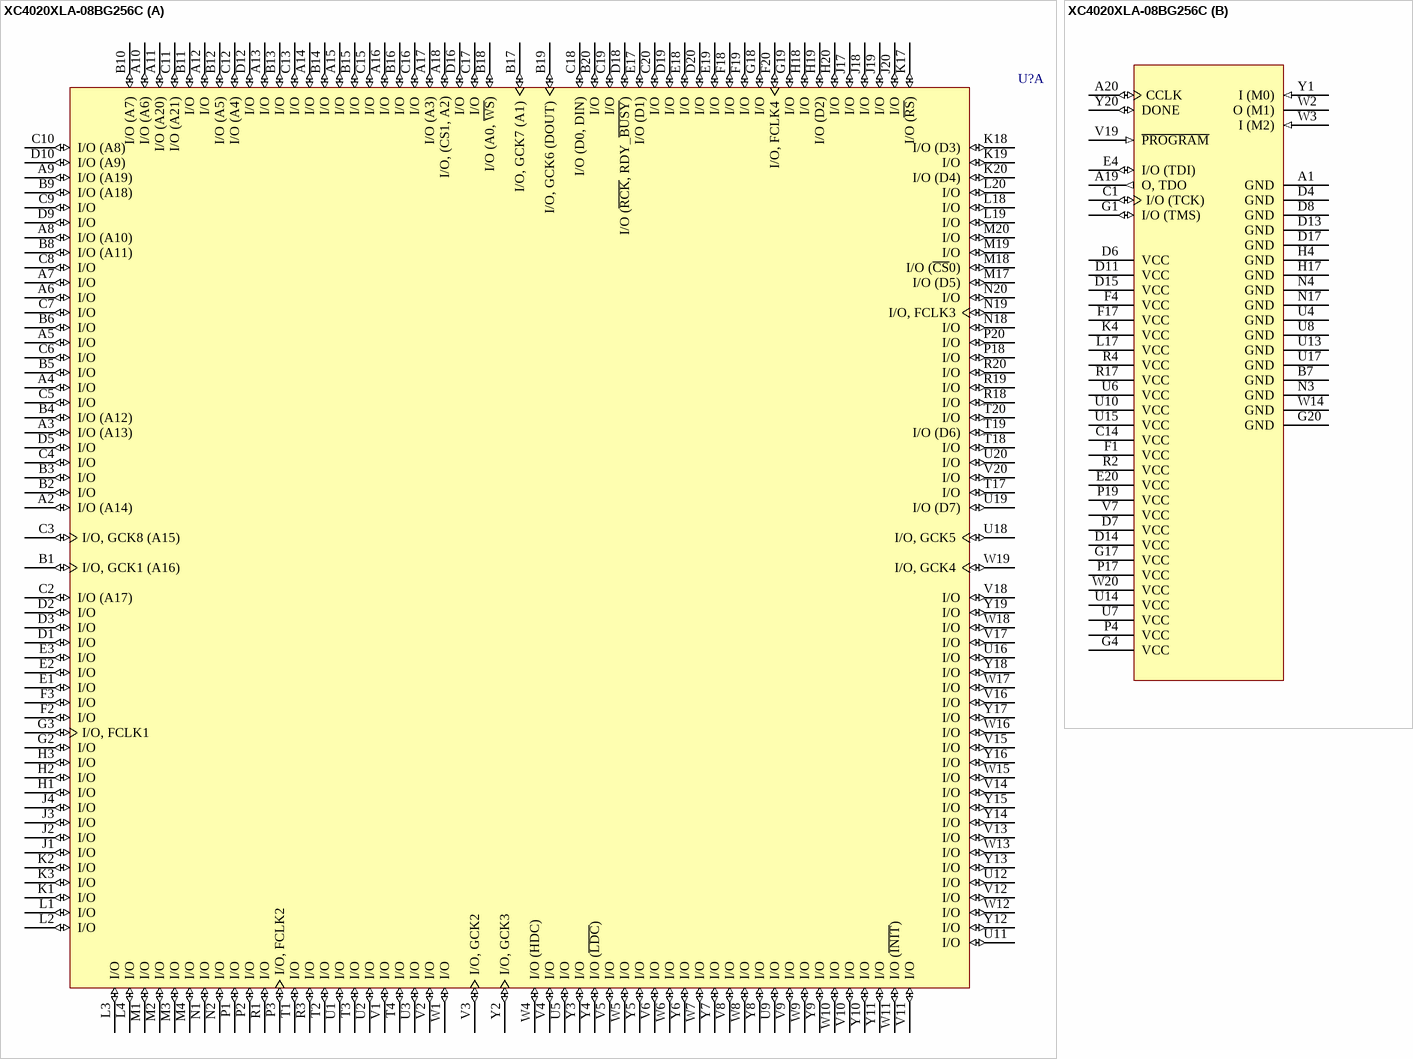
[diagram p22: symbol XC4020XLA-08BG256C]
## XC4020XLA-08BG256C
designator U?
XC4000XLA FPGA, 205 I/Os, 256-Ball BGA, Speed Grade 8, Commercial Grade
footprint BG256 (BGA, 256-Leads, Body 27x27mm, Pitch 1.27mm)
part A pins: A2 I/O (A14) (io), A3 I/O (A13) (io), A4 I/O (io), A5 I/O (io), A6 I/O (io), A7 I/O (io), A8 I/O (A10) (io), A9 I/O (A19) (io), A10 I/O (A6) (io), A11 I/O (A20) (io), A12 I/O (io), A13 I/O (io), A14 I/O (io), A15 I/O (io), A16 I/O (io), A17 I/O (A3) (io), A18 I/O, (CS1, A2) (io), B1 I/O, GCK1 (A16) (io), B2 I/O (io), B3 I/O (io), B4 I/O (A12) (io), B5 I/O (io), B6 I/O (io), B8 I/O (A11) (io), B9 I/O (A18) (io), B10 I/O (A7) (io), B11 I/O (io), B12 I/O (A5) (io), B13 I/O (io), B14 I/O (io), B15 I/O (io), B16 I/O (io), B17 I/O, GCK7 (A1) (io), B18 I/O (A0, ~{WS}) (io), B19 I/O, GCK6 (DOUT) (io), B20 I/O (io), C2 I/O (A17) (io), C3 I/O, GCK8 (A15) (io), C4 I/O (io), C5 I/O (io), C6 I/O (io), C7 I/O (io), C8 I/O (io), C9 I/O (io), C10 I/O (A8) (io), C11 I/O (A21) (io), C12 I/O (A4) (io), C13 I/O (io), C15 I/O (io), C16 I/O (io), C17 I/O (io), C18 I/O (D0, DIN) (io), C19 I/O (io), C20 I/O (io), D1 I/O (io), D2 I/O (io), D3 I/O (io), D5 I/O (io), D9 I/O (io), D10 I/O (A9) (io), D12 I/O (io), D16 I/O (io), D18 I/O (~{RCK}, RDY_~{BUSY}) (io), D19 I/O (io), D20 I/O (io), E1 I/O (io), E2 I/O (io), E3 I/O (io), E17 I/O (D1) (io), E18 I/O (io), E19 I/O (io), F2 I/O (io), F3 I/O (io), F18 I/O (io), F19 I/O (io), F20 I/O, FCLK4 (io), G2 I/O (io), G3 I/O, FCLK1 (io), G18 I/O (io), G19 I/O (io), H1 I/O (io), H2 I/O (io), H3 I/O (io), H18 I/O (io), H19 I/O (D2) (io), H20 I/O (io), J1 I/O (io), J2 I/O (io), J3 I/O (io), J4 I/O (io), J17 I/O (io), J18 I/O (io), J19 I/O (io), J20 I/O (io), K1 I/O (io), K2 I/O (io), K3 I/O (io), K17 I/O (~{RS}) (io), K18 I/O (D3) (io), K19 I/O (io), K20 I/O (D4) (io), L1 I/O (io), L2 I/O (io), L3 I/O (io), L4 I/O (io), L18 I/O (io), L19 I/O (io), L20 I/O (io), M1 I/O (io), M2 I/O (io), M3 I/O (io), M4 I/O (io), M17 I/O (D5) (io), M18 I/O (~{CS}0) (io), M19 I/O (io), M20 I/O (io), N1 I/O (io), N2 I/O (io), N18 I/O (io), N19 I/O, FCLK3 (io), N20 I/O (io), P1 I/O (io), P2 I/O (io), P3 I/O, FCLK2 (io), P18 I/O (io), P20 I/O (io), R1 I/O (io), R3 I/O (io), R18 I/O (io), R19 I/O (io), R20 I/O (io), T1 I/O (io), T2 I/O (io), T3 I/O (io), T4 I/O (io), T17 I/O (io), T18 I/O (io), T19 I/O (D6) (io), T20 I/O (io), U1 I/O (io), U2 I/O (io), U3 I/O (io), U5 I/O (io), U9 I/O (io), U11 I/O (io), U12 I/O (io), U16 I/O (io), U18 I/O, GCK5 (io), U19 I/O (D7) (io), U20 I/O (io), V1 I/O (io), V2 I/O (io), V3 I/O, GCK2 (io), V4 I/O (io), V5 I/O (io), V6 I/O (io), V8 I/O (io), V9 I/O (io), V10 I/O (io), V11 I/O (io), V12 I/O (io), V13 I/O (io), V14 I/O (io), V15 I/O (io), V16 I/O (io), V17 I/O (io), V18 I/O (io), V20 I/O (io), W1 I/O (io), W4 I/O (HDC) (io), W5 I/O (io), W6 I/O (io), W7 I/O (io), W8 I/O (io), W9 I/O (io), W10 I/O (io), W11 I/O (~{INIT}) (io), W12 I/O (io), W13 I/O (io), W15 I/O (io), W16 I/O (io), W17 I/O (io), W18 I/O (io), W19 I/O, GCK4 (io), Y2 I/O, GCK3 (io), Y3 I/O (io), Y4 I/O (~{LDC}) (io), Y5 I/O (io), Y6 I/O (io), Y7 I/O (io), Y8 I/O (io), Y9 I/O (io), Y10 I/O (io), Y11 I/O (io), Y12 I/O (io), Y13 I/O (io), Y14 I/O (io), Y15 I/O (io), Y16 I/O (io), Y17 I/O (io), Y18 I/O (io), Y19 I/O (io)
part B pins: A1 GND (power), A19 O, TDO (out), A20 CCLK (io), B7 GND (power), C1 I/O (TCK) (io), C14 VCC (power), D4 GND (power), D6 VCC (power), D7 VCC (power), D8 GND (power), D11 VCC (power), D13 GND (power), D14 VCC (power), D15 VCC (power), D17 GND (power), E4 I/O (TDI) (io), E20 VCC (power), F1 VCC (power), F4 VCC (power), F17 VCC (power), G1 I/O (TMS) (io), G4 VCC (power), G17 VCC (power), G20 GND (power), H4 GND (power), H17 GND (power), K4 VCC (power), L17 VCC (power), N3 GND (power), N4 GND (power), N17 GND (power), P4 VCC (power), P17 VCC (power), P19 VCC (power), R2 VCC (power), R4 VCC (power), R17 VCC (power), U4 GND (power), U6 VCC (power), U7 VCC (power), U8 GND (power), U10 VCC (power), U13 GND (power), U14 VCC (power), U15 VCC (power), U17 GND (power), V7 VCC (power), V19 ~{PROGRAM} (in), W2 O (M1), W3 I (M2) (in), W14 GND (power), W20 VCC (power), Y1 I (M0) (in), Y20 DONE (io)


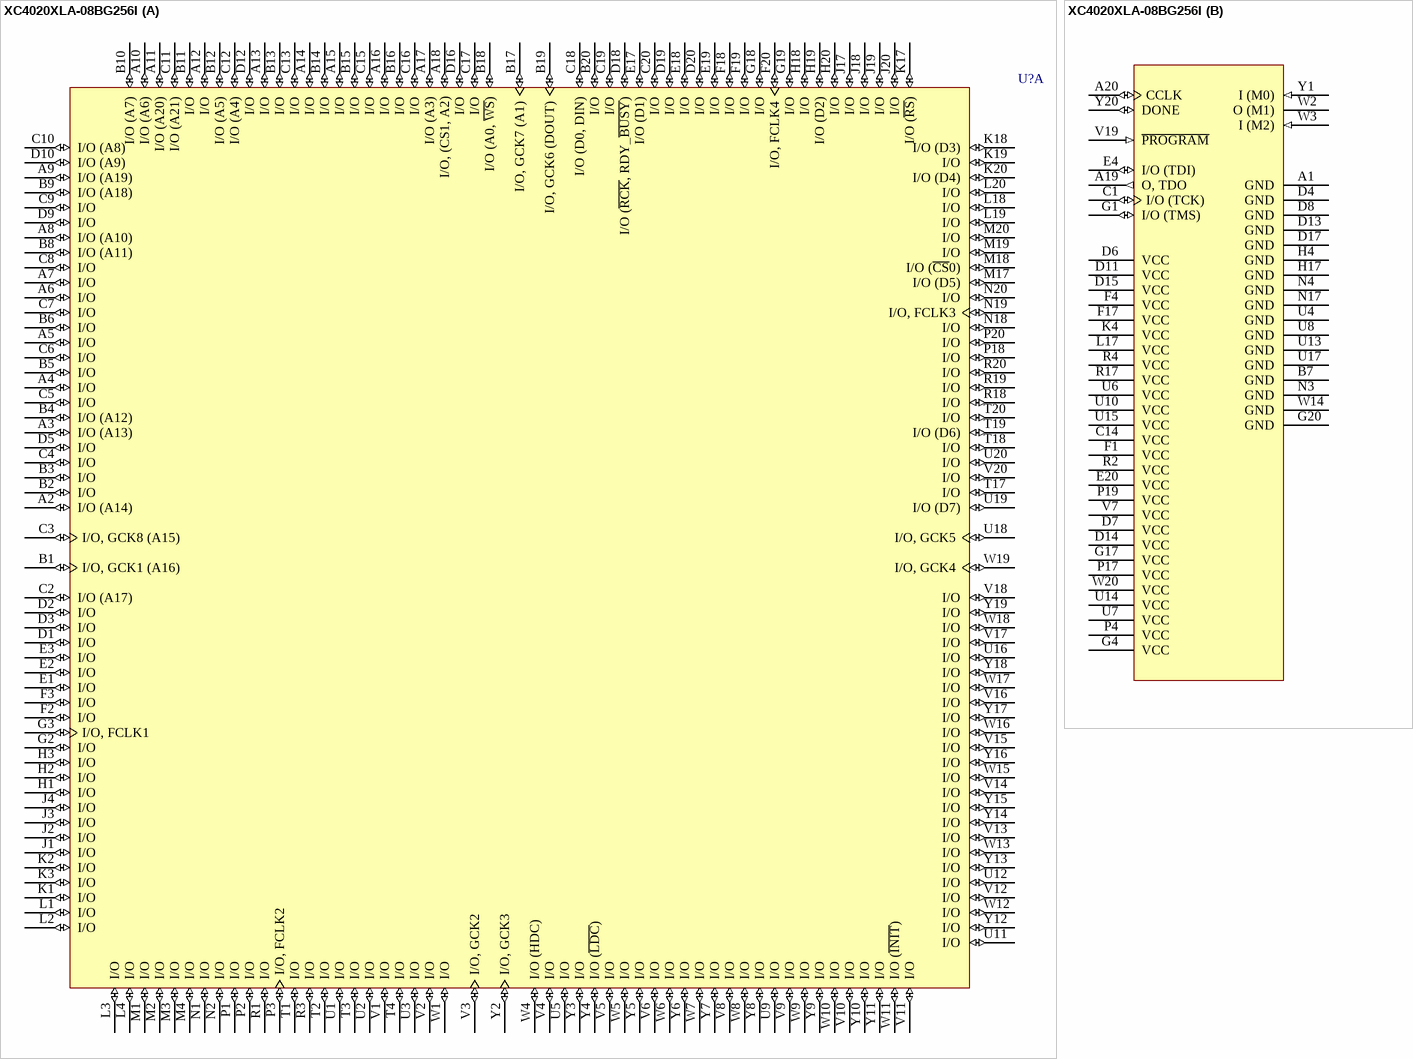
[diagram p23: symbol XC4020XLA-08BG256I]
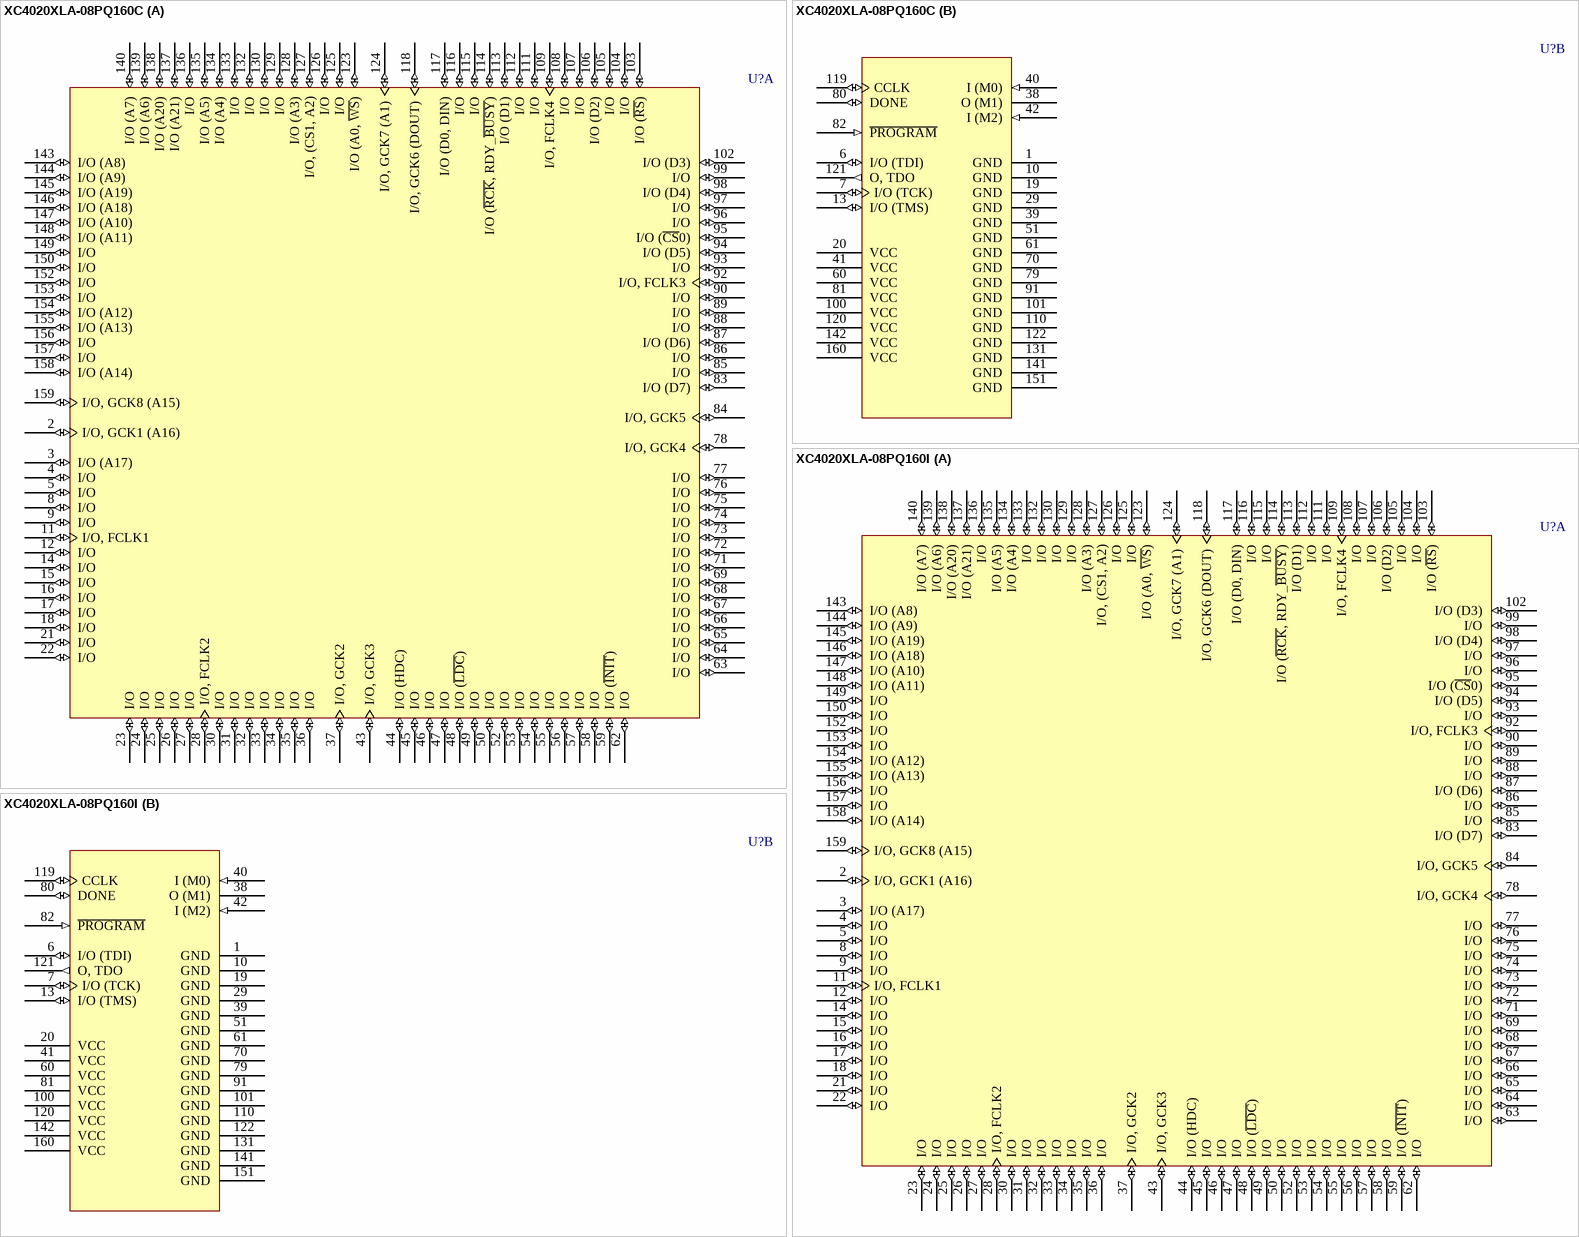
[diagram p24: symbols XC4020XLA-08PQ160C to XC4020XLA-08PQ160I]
## XC4020XLA-08BG256I
designator U?
XC4000XLA FPGA, 205 I/Os, 256-Ball BGA, Speed Grade 8, Industrial Grade
footprint BG256 (BGA, 256-Leads, Body 27x27mm, Pitch 1.27mm)
part A pins: A2 I/O (A14) (io), A3 I/O (A13) (io), A4 I/O (io), A5 I/O (io), A6 I/O (io), A7 I/O (io), A8 I/O (A10) (io), A9 I/O (A19) (io), A10 I/O (A6) (io), A11 I/O (A20) (io), A12 I/O (io), A13 I/O (io), A14 I/O (io), A15 I/O (io), A16 I/O (io), A17 I/O (A3) (io), A18 I/O, (CS1, A2) (io), B1 I/O, GCK1 (A16) (io), B2 I/O (io), B3 I/O (io), B4 I/O (A12) (io), B5 I/O (io), B6 I/O (io), B8 I/O (A11) (io), B9 I/O (A18) (io), B10 I/O (A7) (io), B11 I/O (io), B12 I/O (A5) (io), B13 I/O (io), B14 I/O (io), B15 I/O (io), B16 I/O (io), B17 I/O, GCK7 (A1) (io), B18 I/O (A0, ~{WS}) (io), B19 I/O, GCK6 (DOUT) (io), B20 I/O (io), C2 I/O (A17) (io), C3 I/O, GCK8 (A15) (io), C4 I/O (io), C5 I/O (io), C6 I/O (io), C7 I/O (io), C8 I/O (io), C9 I/O (io), C10 I/O (A8) (io), C11 I/O (A21) (io), C12 I/O (A4) (io), C13 I/O (io), C15 I/O (io), C16 I/O (io), C17 I/O (io), C18 I/O (D0, DIN) (io), C19 I/O (io), C20 I/O (io), D1 I/O (io), D2 I/O (io), D3 I/O (io), D5 I/O (io), D9 I/O (io), D10 I/O (A9) (io), D12 I/O (io), D16 I/O (io), D18 I/O (~{RCK}, RDY_~{BUSY}) (io), D19 I/O (io), D20 I/O (io), E1 I/O (io), E2 I/O (io), E3 I/O (io), E17 I/O (D1) (io), E18 I/O (io), E19 I/O (io), F2 I/O (io), F3 I/O (io), F18 I/O (io), F19 I/O (io), F20 I/O, FCLK4 (io), G2 I/O (io), G3 I/O, FCLK1 (io), G18 I/O (io), G19 I/O (io), H1 I/O (io), H2 I/O (io), H3 I/O (io), H18 I/O (io), H19 I/O (D2) (io), H20 I/O (io), J1 I/O (io), J2 I/O (io), J3 I/O (io), J4 I/O (io), J17 I/O (io), J18 I/O (io), J19 I/O (io), J20 I/O (io), K1 I/O (io), K2 I/O (io), K3 I/O (io), K17 I/O (~{RS}) (io), K18 I/O (D3) (io), K19 I/O (io), K20 I/O (D4) (io), L1 I/O (io), L2 I/O (io), L3 I/O (io), L4 I/O (io), L18 I/O (io), L19 I/O (io), L20 I/O (io), M1 I/O (io), M2 I/O (io), M3 I/O (io), M4 I/O (io), M17 I/O (D5) (io), M18 I/O (~{CS}0) (io), M19 I/O (io), M20 I/O (io), N1 I/O (io), N2 I/O (io), N18 I/O (io), N19 I/O, FCLK3 (io), N20 I/O (io), P1 I/O (io), P2 I/O (io), P3 I/O, FCLK2 (io), P18 I/O (io), P20 I/O (io), R1 I/O (io), R3 I/O (io), R18 I/O (io), R19 I/O (io), R20 I/O (io), T1 I/O (io), T2 I/O (io), T3 I/O (io), T4 I/O (io), T17 I/O (io), T18 I/O (io), T19 I/O (D6) (io), T20 I/O (io), U1 I/O (io), U2 I/O (io), U3 I/O (io), U5 I/O (io), U9 I/O (io), U11 I/O (io), U12 I/O (io), U16 I/O (io), U18 I/O, GCK5 (io), U19 I/O (D7) (io), U20 I/O (io), V1 I/O (io), V2 I/O (io), V3 I/O, GCK2 (io), V4 I/O (io), V5 I/O (io), V6 I/O (io), V8 I/O (io), V9 I/O (io), V10 I/O (io), V11 I/O (io), V12 I/O (io), V13 I/O (io), V14 I/O (io), V15 I/O (io), V16 I/O (io), V17 I/O (io), V18 I/O (io), V20 I/O (io), W1 I/O (io), W4 I/O (HDC) (io), W5 I/O (io), W6 I/O (io), W7 I/O (io), W8 I/O (io), W9 I/O (io), W10 I/O (io), W11 I/O (~{INIT}) (io), W12 I/O (io), W13 I/O (io), W15 I/O (io), W16 I/O (io), W17 I/O (io), W18 I/O (io), W19 I/O, GCK4 (io), Y2 I/O, GCK3 (io), Y3 I/O (io), Y4 I/O (~{LDC}) (io), Y5 I/O (io), Y6 I/O (io), Y7 I/O (io), Y8 I/O (io), Y9 I/O (io), Y10 I/O (io), Y11 I/O (io), Y12 I/O (io), Y13 I/O (io), Y14 I/O (io), Y15 I/O (io), Y16 I/O (io), Y17 I/O (io), Y18 I/O (io), Y19 I/O (io)
part B pins: A1 GND (power), A19 O, TDO (out), A20 CCLK (io), B7 GND (power), C1 I/O (TCK) (io), C14 VCC (power), D4 GND (power), D6 VCC (power), D7 VCC (power), D8 GND (power), D11 VCC (power), D13 GND (power), D14 VCC (power), D15 VCC (power), D17 GND (power), E4 I/O (TDI) (io), E20 VCC (power), F1 VCC (power), F4 VCC (power), F17 VCC (power), G1 I/O (TMS) (io), G4 VCC (power), G17 VCC (power), G20 GND (power), H4 GND (power), H17 GND (power), K4 VCC (power), L17 VCC (power), N3 GND (power), N4 GND (power), N17 GND (power), P4 VCC (power), P17 VCC (power), P19 VCC (power), R2 VCC (power), R4 VCC (power), R17 VCC (power), U4 GND (power), U6 VCC (power), U7 VCC (power), U8 GND (power), U10 VCC (power), U13 GND (power), U14 VCC (power), U15 VCC (power), U17 GND (power), V7 VCC (power), V19 ~{PROGRAM} (in), W2 O (M1), W3 I (M2) (in), W14 GND (power), W20 VCC (power), Y1 I (M0) (in), Y20 DONE (io)

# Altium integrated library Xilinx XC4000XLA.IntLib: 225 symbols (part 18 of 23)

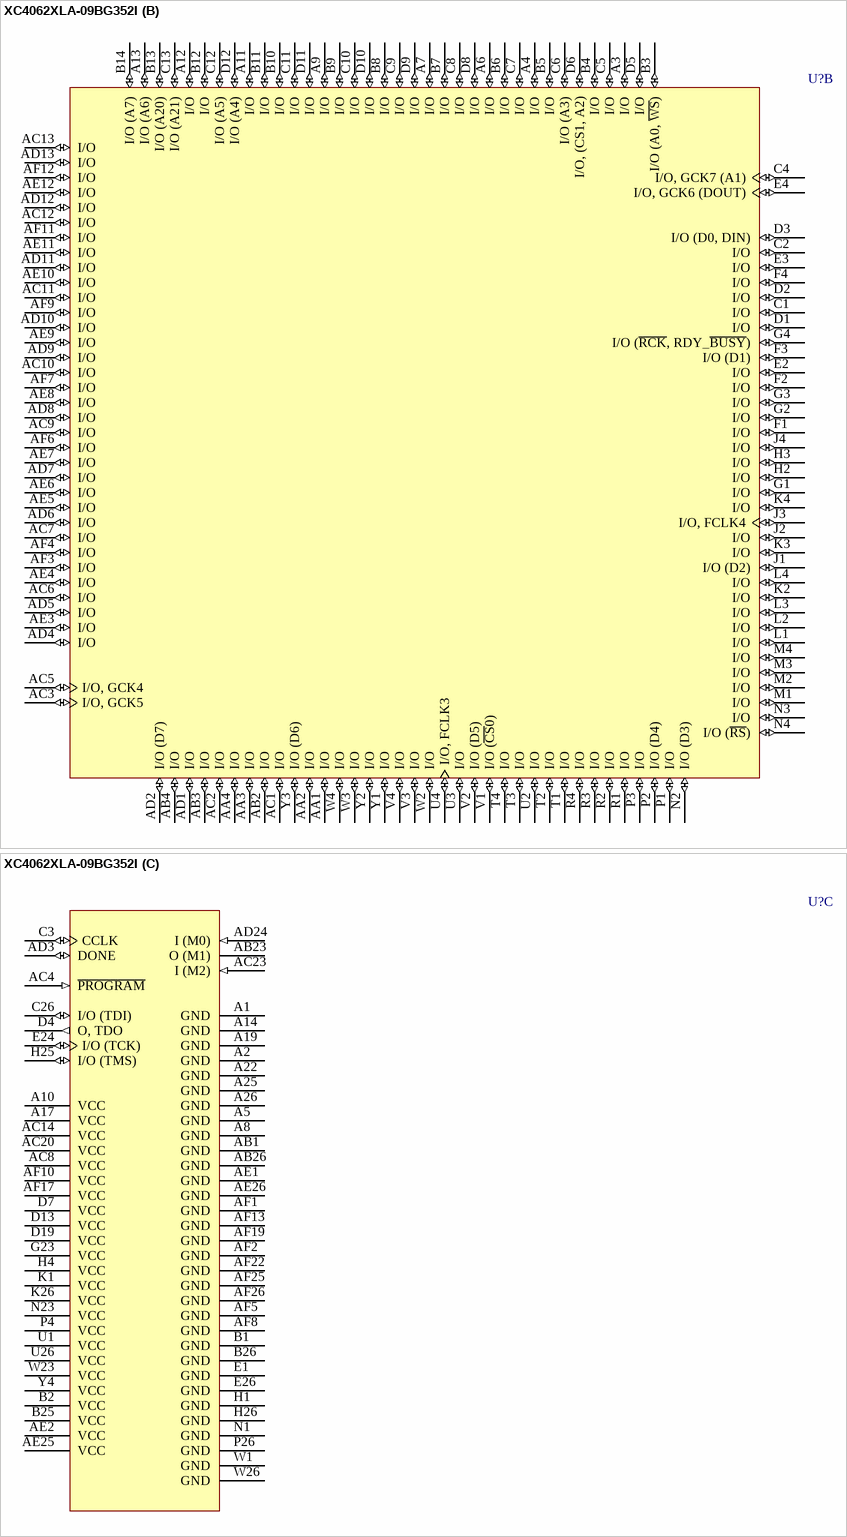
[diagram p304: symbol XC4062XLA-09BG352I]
## XC4062XLA-09BG352I
designator U?
XC4000XLA FPGA, 289 I/Os, 352-Ball BGA, Speed Grade 9, Industrial Grade
footprint BG352 (BGA, 352-Leads, Body 35x35mm, Pitch 1.27mm)
part A pins: A15 I/O (A19) (io), A16 I/O (A10) (io), A18 I/O (io), A20 I/O (io), A21 I/O (io), A23 I/O (io), A24 I/O (io), AA23 I/O (io), AA24 I/O (io), AA25 I/O (io), AA26 I/O (io), AB24 I/O (io), AB25 I/O (io), AC15 I/O (io), AC16 I/O (io), AC17 I/O (io), AC18 I/O (io), AC19 I/O (io), AC21 I/O (io), AC22 I/O (io), AC24 I/O, GCK2 (io), AC25 I/O (io), AC26 I/O (io), AD14 I/O (io), AD15 I/O (io), AD16 I/O (io), AD17 I/O (io), AD18 I/O (io), AD19 I/O (io), AD20 I/O (io), AD21 I/O (io), AD22 I/O (io), AD23 I/O (HDC) (io), AD25 I/O (io), AD26 I/O (io), AE13 I/O (io), AE14 I/O (io), AE15 I/O (io), AE16 I/O (io), AE17 I/O (io), AE18 I/O (io), AE19 I/O (io), AE20 I/O (io), AE21 I/O (io), AE22 I/O (io), AE23 I/O (~{LDC}) (io), AE24 I/O, GCK3 (io), AF14 I/O (~{INIT}) (io), AF15 I/O (io), AF16 I/O (io), AF18 I/O (io), AF20 I/O (io), AF21 I/O (io), AF23 I/O (io), AF24 I/O (io), B15 I/O (A18) (io), B16 I/O (A11) (io), B17 I/O (io), B18 I/O (io), B19 I/O (io), B20 I/O (io), B21 I/O (io), B22 I/O (A12) (io), B23 I/O (io), B24 I/O (io), C14 I/O (A9) (io), C15 I/O (io), C16 I/O (io), C17 I/O (io), C18 I/O (io), C19 I/O (io), C20 I/O (io), C21 I/O (A13) (io), C22 I/O (io), C23 I/O (io), C24 I/O, GCK8 (A15) (io), C25 I/O (A17) (io), D14 I/O (A8) (io), D15 I/O (io), D16 I/O (io), D17 I/O (io), D18 I/O (io), D20 I/O (io), D21 I/O (io), D22 I/O (A14) (io), D23 I/O, GCK1 (A16) (io), D24 I/O (io), D25 I/O (io), D26 I/O (io), E23 I/O (io), E25 I/O (io), F23 I/O (io), F24 I/O (io), F25 I/O (io), F26 I/O (io), G24 I/O (io), G25 I/O (io), G26 I/O (io), H23 I/O (io), H24 I/O (io), J23 I/O, FCLK1 (io), J24 I/O (io), J25 I/O (io), J26 I/O (io), K23 I/O (io), K24 I/O (io), K25 I/O (io), L23 I/O (io), L24 I/O (io), L25 I/O (io), L26 I/O (io), M23 I/O (io), M24 I/O (io), M25 I/O (io), M26 I/O (io), N24 I/O (io), N25 I/O (io), N26 I/O (io), P23 I/O (io), P24 I/O (io), P25 I/O (io), R23 I/O (io), R24 I/O (io), R25 I/O (io), R26 I/O (io), T23 I/O (io), T24 I/O (io), T25 I/O (io), T26 I/O (io), U23 I/O, FCLK2 (io), U24 I/O (io), U25 I/O (io), V23 I/O (io), V24 I/O (io), V25 I/O (io), V26 I/O (io), W24 I/O (io), W25 I/O (io), Y23 I/O (io), Y24 I/O (io), Y25 I/O (io), Y26 I/O (io)
part B pins: A3 I/O (io), A4 I/O (io), A6 I/O (io), A7 I/O (io), A9 I/O (io), A11 I/O (io), A12 I/O (io), A13 I/O (A6) (io), AA1 I/O (io), AA2 I/O (io), AA3 I/O (io), AA4 I/O (io), AB2 I/O (io), AB3 I/O (io), AB4 I/O (io), AC1 I/O (io), AC2 I/O (io), AC3 I/O, GCK5 (io), AC5 I/O, GCK4 (io), AC6 I/O (io), AC7 I/O (io), AC9 I/O (io), AC10 I/O (io), AC11 I/O (io), AC12 I/O (io), AC13 I/O (io), AD1 I/O (io), AD2 I/O (D7) (io), AD4 I/O (io), AD5 I/O (io), AD6 I/O (io), AD7 I/O (io), AD8 I/O (io), AD9 I/O (io), AD10 I/O (io), AD11 I/O (io), AD12 I/O (io), AD13 I/O (io), AE3 I/O (io), AE4 I/O (io), AE5 I/O (io), AE6 I/O (io), AE7 I/O (io), AE8 I/O (io), AE9 I/O (io), AE10 I/O (io), AE11 I/O (io), AE12 I/O (io), AF3 I/O (io), AF4 I/O (io), AF6 I/O (io), AF7 I/O (io), AF9 I/O (io), AF11 I/O (io), AF12 I/O (io), B3 I/O (A0, ~{WS}) (io), B4 I/O (io), B5 I/O (io), B6 I/O (io), B7 I/O (io), B8 I/O (io), B9 I/O (io), B10 I/O (io), B11 I/O (io), B12 I/O (io), B13 I/O (A20) (io), B14 I/O (A7) (io), C1 I/O (io), C2 I/O (io), C4 I/O, GCK7 (A1) (io), C5 I/O (io), C6 I/O (A3) (io), C7 I/O (io), C8 I/O (io), C9 I/O (io), C10 I/O (io), C11 I/O (io), C12 I/O (A5) (io), C13 I/O (A21) (io), D1 I/O (io), D2 I/O (io), D3 I/O (D0, DIN) (io), D5 I/O (io), D6 I/O, (CS1, A2) (io), D8 I/O (io), D9 I/O (io), D10 I/O (io), D11 I/O (io), D12 I/O (A4) (io), E2 I/O (io), E3 I/O (io), E4 I/O, GCK6 (DOUT) (io), F1 I/O (io), F2 I/O (io), F3 I/O (D1) (io), F4 I/O (io), G1 I/O (io), G2 I/O (io), G3 I/O (io), G4 I/O (~{RCK}, RDY_~{BUSY}) (io), H2 I/O (io), H3 I/O (io), J1 I/O (D2) (io), J2 I/O (io), J3 I/O, FCLK4 (io), J4 I/O (io), K2 I/O (io), K3 I/O (io), K4 I/O (io), L1 I/O (io), L2 I/O (io), L3 I/O (io), L4 I/O (io), M1 I/O (io), M2 I/O (io), M3 I/O (io), M4 I/O (io), N2 I/O (D3) (io), N3 I/O (io), N4 I/O (~{RS}) (io), P1 I/O (io), P2 I/O (D4) (io), P3 I/O (io), R1 I/O (io), R2 I/O (io), R3 I/O (io), R4 I/O (io), T1 I/O (io), T2 I/O (io), T3 I/O (io), T4 I/O (io), U2 I/O (io), U3 I/O (io), U4 I/O, FCLK3 (io), V1 I/O (~{CS}0) (io), V2 I/O (D5) (io), V3 I/O (io), V4 I/O (io), W2 I/O (io), W3 I/O (io), W4 I/O (io), Y1 I/O (io), Y2 I/O (io), Y3 I/O (D6) (io)
part C pins: A1 GND (power), A2 GND (power), A5 GND (power), A8 GND (power), A10 VCC (power), A14 GND (power), A17 VCC (power), A19 GND (power), A22 GND (power), A25 GND (power), A26 GND (power), AB1 GND (power), AB23 O (M1), AB26 GND (power), AC4 ~{PROGRAM} (in), AC8 VCC (power), AC14 VCC (power), AC20 VCC (power), AC23 I (M2) (in), AD3 DONE (io), AD24 I (M0) (in), AE1 GND (power), AE2 VCC (power), AE25 VCC (power), AE26 GND (power), AF1 GND (power), AF2 GND (power), AF5 GND (power), AF8 GND (power), AF10 VCC (power), AF13 GND (power), AF17 VCC (power), AF19 GND (power), AF22 GND (power), AF25 GND (power), AF26 GND (power), B1 GND (power), B2 VCC (power), B25 VCC (power), B26 GND (power), C3 CCLK (io), C26 I/O (TDI) (io), D4 O, TDO (out), D7 VCC (power), D13 VCC (power), D19 VCC (power), E1 GND (power), E24 I/O (TCK) (io), E26 GND (power), G23 VCC (power), H1 GND (power), H4 VCC (power), H25 I/O (TMS) (io), H26 GND (power), K1 VCC (power), K26 VCC (power), N1 GND (power), N23 VCC (power), P4 VCC (power), P26 GND (power), U1 VCC (power), U26 VCC (power), W1 GND (power), W23 VCC (power), W26 GND (power), Y4 VCC (power)




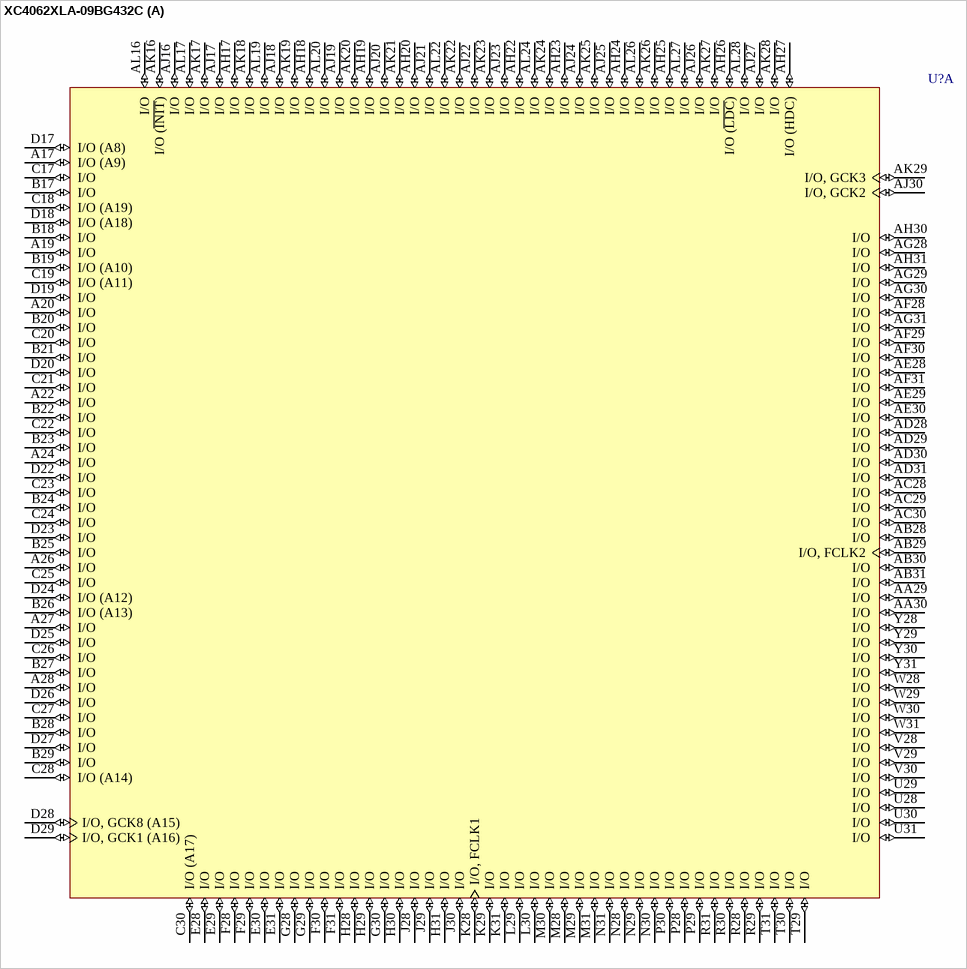
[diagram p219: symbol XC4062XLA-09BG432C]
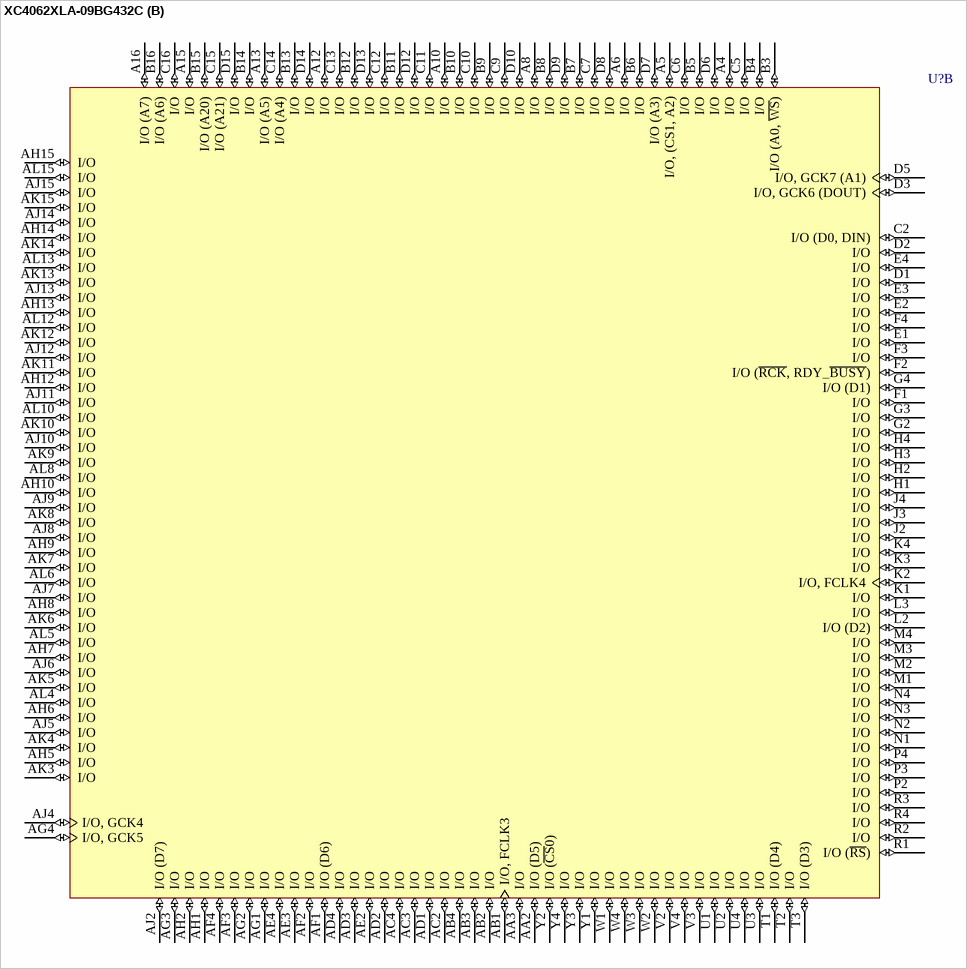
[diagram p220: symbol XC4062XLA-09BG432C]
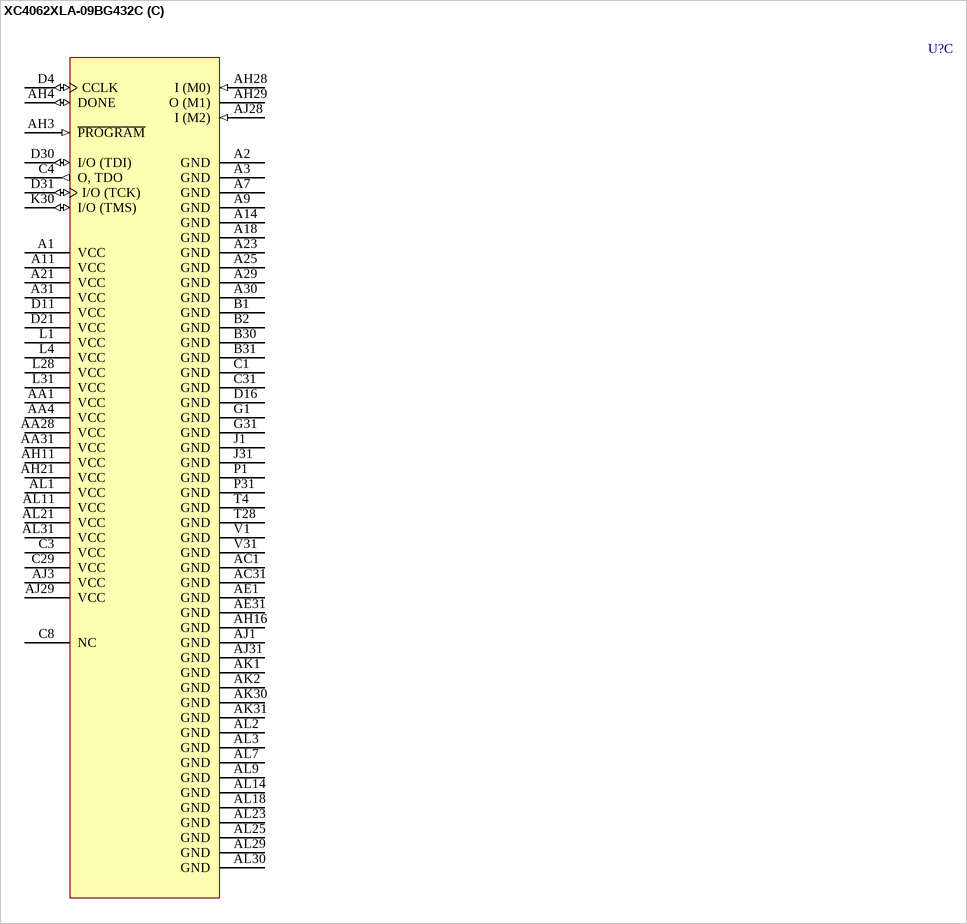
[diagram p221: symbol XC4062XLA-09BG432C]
## XC4062XLA-09BG432C
designator U?
XC4000XLA FPGA, 352 I/Os, 432-Ball BGA, Speed Grade 9, Commercial Grade
footprint BG432 (BGA, 432-Leads, Body 40x40mm, Pitch 1.27mm)
part A pins: A17 I/O (A9) (io), A19 I/O (io), A20 I/O (io), A22 I/O (io), A24 I/O (io), A26 I/O (io), A27 I/O (io), A28 I/O (io), AA29 I/O (io), AA30 I/O (io), AB28 I/O (io), AB29 I/O, FCLK2 (io), AB30 I/O (io), AB31 I/O (io), AC28 I/O (io), AC29 I/O (io), AC30 I/O (io), AD28 I/O (io), AD29 I/O (io), AD30 I/O (io), AD31 I/O (io), AE28 I/O (io), AE29 I/O (io), AE30 I/O (io), AF28 I/O (io), AF29 I/O (io), AF30 I/O (io), AF31 I/O (io), AG28 I/O (io), AG29 I/O (io), AG30 I/O (io), AG31 I/O (io), AH17 I/O (io), AH18 I/O (io), AH19 I/O (io), AH20 I/O (io), AH22 I/O (io), AH23 I/O (io), AH24 I/O (io), AH25 I/O (io), AH26 I/O (~{LDC}) (io), AH27 I/O (HDC) (io), AH30 I/O (io), AH31 I/O (io), AJ16 I/O (io), AJ17 I/O (io), AJ18 I/O (io), AJ19 I/O (io), AJ20 I/O (io), AJ21 I/O (io), AJ22 I/O (io), AJ23 I/O (io), AJ24 I/O (io), AJ25 I/O (io), AJ26 I/O (io), AJ27 I/O (io), AJ30 I/O, GCK2 (io), AK16 I/O (~{INIT}) (io), AK17 I/O (io), AK18 I/O (io), AK19 I/O (io), AK20 I/O (io), AK21 I/O (io), AK22 I/O (io), AK23 I/O (io), AK24 I/O (io), AK25 I/O (io), AK26 I/O (io), AK27 I/O (io), AK28 I/O (io), AK29 I/O, GCK3 (io), AL16 I/O (io), AL17 I/O (io), AL19 I/O (io), AL20 I/O (io), AL22 I/O (io), AL24 I/O (io), AL26 I/O (io), AL27 I/O (io), AL28 I/O (io), B17 I/O (io), B18 I/O (io), B19 I/O (A10) (io), B20 I/O (io), B21 I/O (io), B22 I/O (io), B23 I/O (io), B24 I/O (io), B25 I/O (io), B26 I/O (A13) (io), B27 I/O (io), B28 I/O (io), B29 I/O (io), C17 I/O (io), C18 I/O (A19) (io), C19 I/O (A11) (io), C20 I/O (io), C21 I/O (io), C22 I/O (io), C23 I/O (io), C24 I/O (io), C25 I/O (io), C26 I/O (io), C27 I/O (io), C28 I/O (A14) (io), C30 I/O (A17) (io), D17 I/O (A8) (io), D18 I/O (A18) (io), D19 I/O (io), D20 I/O (io), D22 I/O (io), D23 I/O (io), D24 I/O (A12) (io), D25 I/O (io), D26 I/O (io), D27 I/O (io), D28 I/O, GCK8 (A15) (io), D29 I/O, GCK1 (A16) (io), E28 I/O (io), E29 I/O (io), E30 I/O (io), E31 I/O (io), F28 I/O (io), F29 I/O (io), F30 I/O (io), F31 I/O (io), G28 I/O (io), G29 I/O (io), G30 I/O (io), H28 I/O (io), H29 I/O (io), H30 I/O (io), H31 I/O (io), J28 I/O (io), J29 I/O (io), J30 I/O (io), K28 I/O, FCLK1 (io), K29 I/O (io), K31 I/O (io), L29 I/O (io), L30 I/O (io), M28 I/O (io), M29 I/O (io), M30 I/O (io), M31 I/O (io), N28 I/O (io), N29 I/O (io), N30 I/O (io), N31 I/O (io), P28 I/O (io), P29 I/O (io), P30 I/O (io), R28 I/O (io), R29 I/O (io), R30 I/O (io), R31 I/O (io), T29 I/O (io), T30 I/O (io), T31 I/O (io), U28 I/O (io), U29 I/O (io), U30 I/O (io), U31 I/O (io), V28 I/O (io), V29 I/O (io), V30 I/O (io), W28 I/O (io), W29 I/O (io), W30 I/O (io), W31 I/O (io), Y28 I/O (io), Y29 I/O (io), Y30 I/O (io), Y31 I/O (io)
part B pins: A4 I/O (io), A5 I/O, (CS1, A2) (io), A6 I/O (io), A8 I/O (io), A10 I/O (io), A12 I/O (io), A13 I/O (A5) (io), A15 I/O (io), A16 I/O (A7) (io), AA2 I/O (D5) (io), AA3 I/O (io), AB1 I/O, FCLK3 (io), AB2 I/O (io), AB3 I/O (io), AB4 I/O (io), AC2 I/O (io), AC3 I/O (io), AC4 I/O (io), AD1 I/O (io), AD2 I/O (io), AD3 I/O (io), AD4 I/O (io), AE2 I/O (io), AE3 I/O (io), AE4 I/O (io), AF1 I/O (D6) (io), AF2 I/O (io), AF3 I/O (io), AF4 I/O (io), AG1 I/O (io), AG2 I/O (io), AG3 I/O (io), AG4 I/O, GCK5 (io), AH1 I/O (io), AH2 I/O (io), AH5 I/O (io), AH6 I/O (io), AH7 I/O (io), AH8 I/O (io), AH9 I/O (io), AH10 I/O (io), AH12 I/O (io), AH13 I/O (io), AH14 I/O (io), AH15 I/O (io), AJ2 I/O (D7) (io), AJ4 I/O, GCK4 (io), AJ5 I/O (io), AJ6 I/O (io), AJ7 I/O (io), AJ8 I/O (io), AJ9 I/O (io), AJ10 I/O (io), AJ11 I/O (io), AJ12 I/O (io), AJ13 I/O (io), AJ14 I/O (io), AJ15 I/O (io), AK3 I/O (io), AK4 I/O (io), AK5 I/O (io), AK6 I/O (io), AK7 I/O (io), AK8 I/O (io), AK9 I/O (io), AK10 I/O (io), AK11 I/O (io), AK12 I/O (io), AK13 I/O (io), AK14 I/O (io), AK15 I/O (io), AL4 I/O (io), AL5 I/O (io), AL6 I/O (io), AL8 I/O (io), AL10 I/O (io), AL12 I/O (io), AL13 I/O (io), AL15 I/O (io), B3 I/O (A0, ~{WS}) (io), B4 I/O (io), B5 I/O (io), B6 I/O (io), B7 I/O (io), B8 I/O (io), B9 I/O (io), B10 I/O (io), B11 I/O (io), B12 I/O (io), B13 I/O (io), B14 I/O (io), B15 I/O (A20) (io), B16 I/O (A6) (io), C2 I/O (D0, DIN) (io), C5 I/O (io), C6 I/O (io), C7 I/O (io), C9 I/O (io), C10 I/O (io), C11 I/O (io), C12 I/O (io), C13 I/O (io), C14 I/O (A4) (io), C15 I/O (A21) (io), C16 I/O (io), D1 I/O (io), D2 I/O (io), D3 I/O, GCK6 (DOUT) (io), D5 I/O, GCK7 (A1) (io), D6 I/O (io), D7 I/O (A3) (io), D8 I/O (io), D9 I/O (io), D10 I/O (io), D12 I/O (io), D13 I/O (io), D14 I/O (io), D15 I/O (io), E1 I/O (io), E2 I/O (io), E3 I/O (io), E4 I/O (io), F1 I/O (io), F2 I/O (~{RCK}, RDY_~{BUSY}) (io), F3 I/O (io), F4 I/O (io), G2 I/O (io), G3 I/O (io), G4 I/O (D1) (io), H1 I/O (io), H2 I/O (io), H3 I/O (io), H4 I/O (io), J2 I/O (io), J3 I/O (io), J4 I/O (io), K1 I/O (io), K2 I/O, FCLK4 (io), K3 I/O (io), K4 I/O (io), L2 I/O (D2) (io), L3 I/O (io), M1 I/O (io), M2 I/O (io), M3 I/O (io), M4 I/O (io), N1 I/O (io), N2 I/O (io), N3 I/O (io), N4 I/O (io), P2 I/O (io), P3 I/O (io), P4 I/O (io), R1 I/O (~{RS}) (io), R2 I/O (io), R3 I/O (io), R4 I/O (io), T1 I/O (D4) (io), T2 I/O (io), T3 I/O (D3) (io), U1 I/O (io), U2 I/O (io), U3 I/O (io), U4 I/O (io), V2 I/O (io), V3 I/O (io), V4 I/O (io), W1 I/O (io), W2 I/O (io), W3 I/O (io), W4 I/O (io), Y1 I/O (io), Y2 I/O (~{CS}0) (io), Y3 I/O (io), Y4 I/O (io)
part C pins: A1 VCC (power), A2 GND (power), A3 GND (power), A7 GND (power), A9 GND (power), A11 VCC (power), A14 GND (power), A18 GND (power), A21 VCC (power), A23 GND (power), A25 GND (power), A29 GND (power), A30 GND (power), A31 VCC (power), AA1 VCC (power), AA4 VCC (power), AA28 VCC (power), AA31 VCC (power), AC1 GND (power), AC31 GND (power), AE1 GND (power), AE31 GND (power), AH3 ~{PROGRAM} (in), AH4 DONE (io), AH11 VCC (power), AH16 GND (power), AH21 VCC (power), AH28 I (M0) (in), AH29 O (M1), AJ1 GND (power), AJ3 VCC (power), AJ28 I (M2) (in), AJ29 VCC (power), AJ31 GND (power), AK1 GND (power), AK2 GND (power), AK30 GND (power), AK31 GND (power), AL1 VCC (power), AL2 GND (power), AL3 GND (power), AL7 GND (power), AL9 GND (power), AL11 VCC (power), AL14 GND (power), AL18 GND (power), AL21 VCC (power), AL23 GND (power), AL25 GND (power), AL29 GND (power), AL30 GND (power), AL31 VCC (power), B1 GND (power), B2 GND (power), B30 GND (power), B31 GND (power), C1 GND (power), C3 VCC (power), C4 O, TDO (out), C8 NC, C29 VCC (power), C31 GND (power), D4 CCLK (io), D11 VCC (power), D16 GND (power), D21 VCC (power), D30 I/O (TDI) (io), D31 I/O (TCK) (io), G1 GND (power), G31 GND (power), J1 GND (power), J31 GND (power), K30 I/O (TMS) (io), L1 VCC (power), L4 VCC (power), L28 VCC (power), L31 VCC (power), P1 GND (power), P31 GND (power), T4 GND (power), T28 GND (power), V1 GND (power), V31 GND (power)




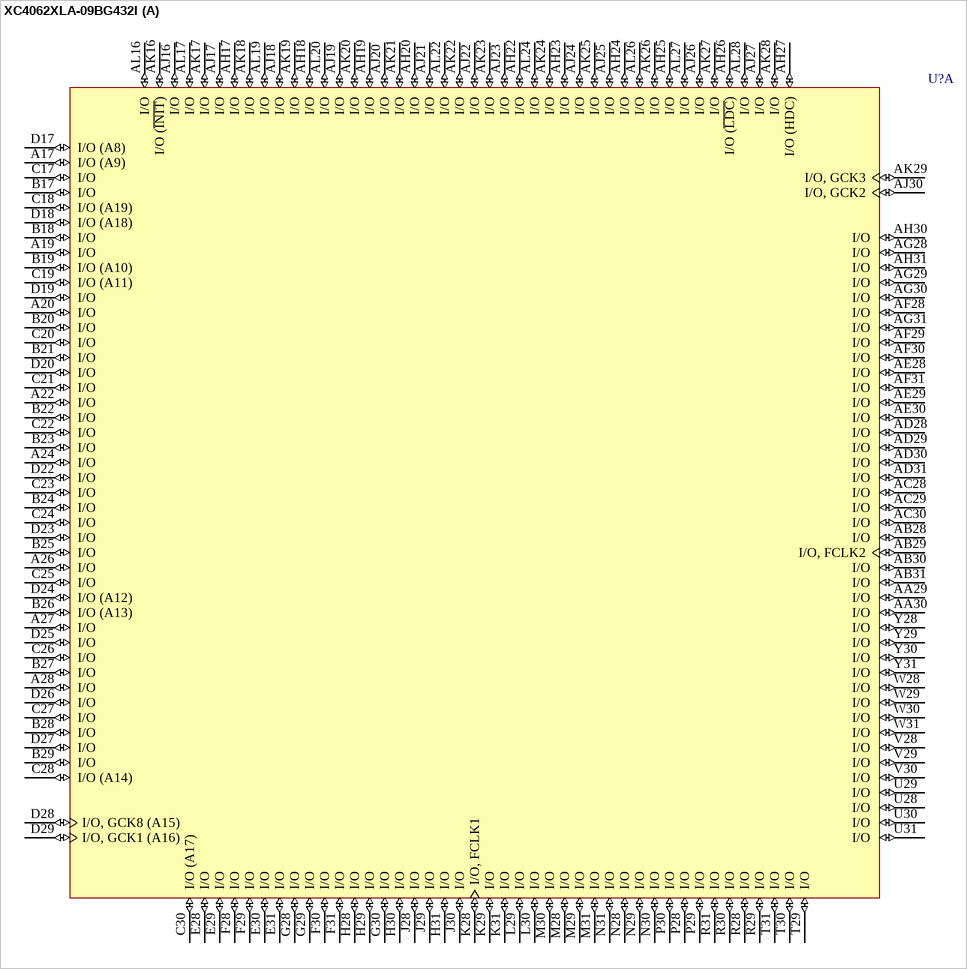
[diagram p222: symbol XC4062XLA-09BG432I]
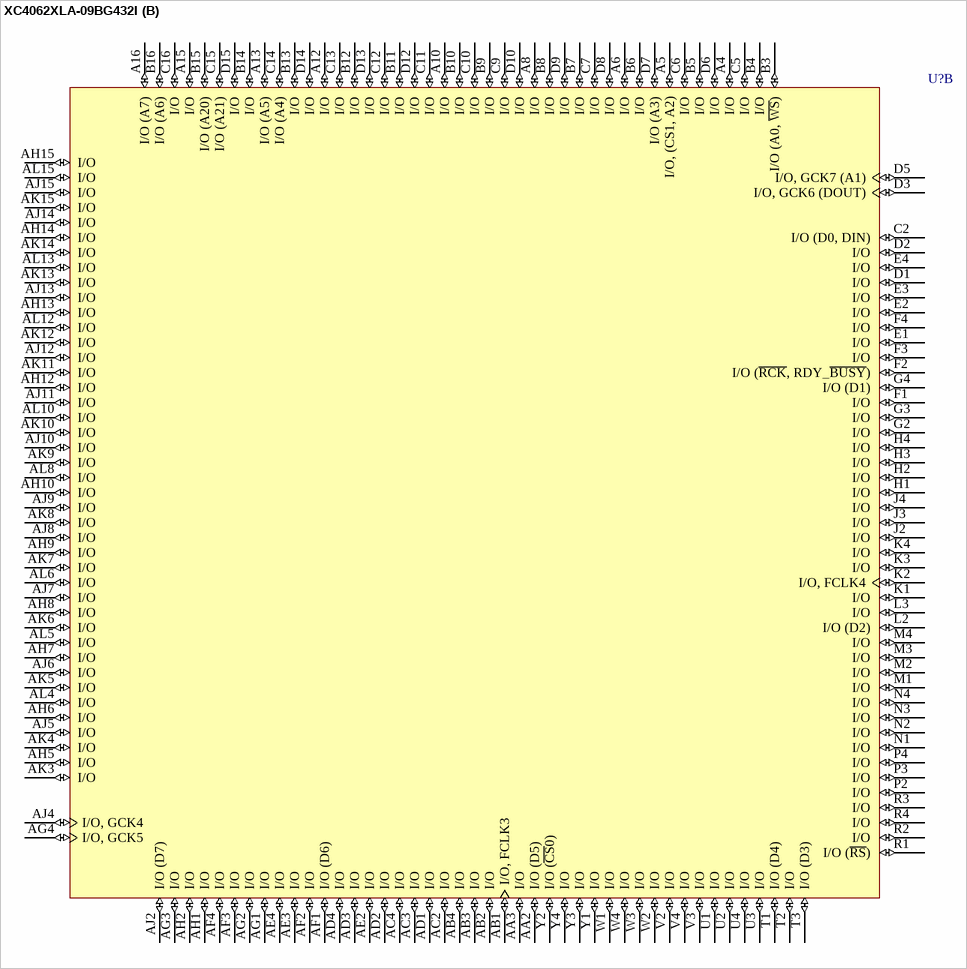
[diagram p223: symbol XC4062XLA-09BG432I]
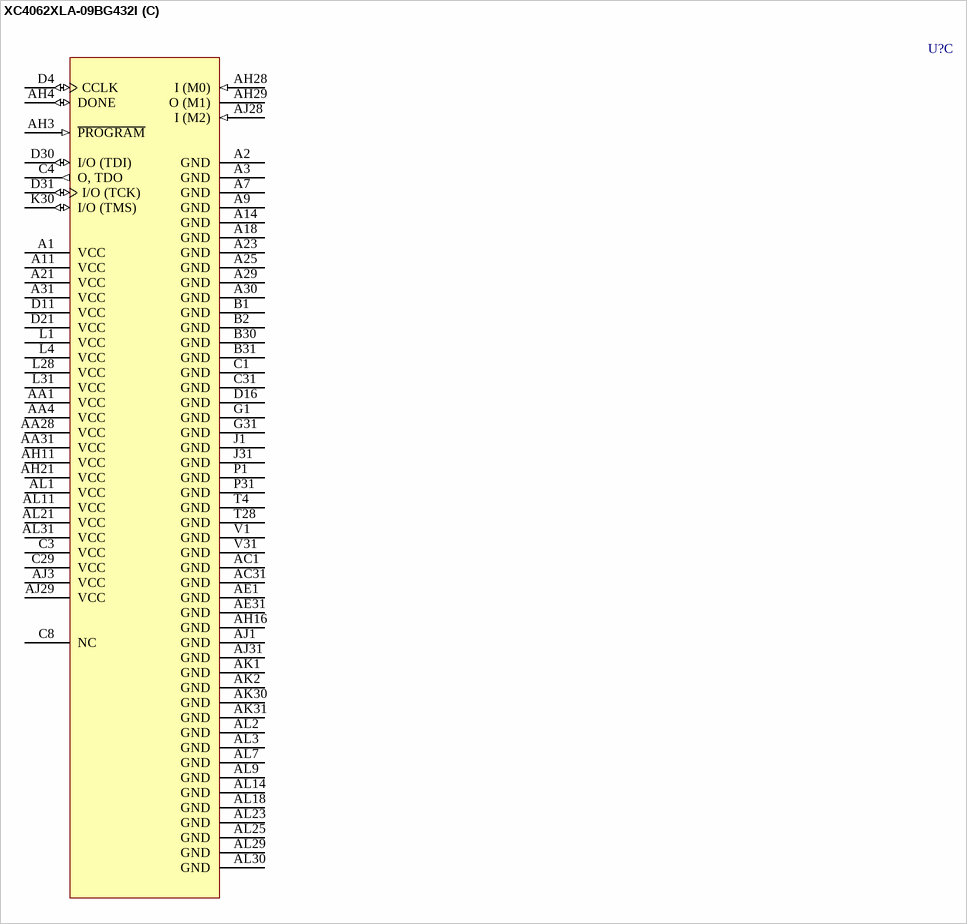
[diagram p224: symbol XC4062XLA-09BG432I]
## XC4062XLA-09BG432I
designator U?
XC4000XLA FPGA, 352 I/Os, 432-Ball BGA, Speed Grade 9, Industrial Grade
footprint BG432 (BGA, 432-Leads, Body 40x40mm, Pitch 1.27mm)
part A pins: A17 I/O (A9) (io), A19 I/O (io), A20 I/O (io), A22 I/O (io), A24 I/O (io), A26 I/O (io), A27 I/O (io), A28 I/O (io), AA29 I/O (io), AA30 I/O (io), AB28 I/O (io), AB29 I/O, FCLK2 (io), AB30 I/O (io), AB31 I/O (io), AC28 I/O (io), AC29 I/O (io), AC30 I/O (io), AD28 I/O (io), AD29 I/O (io), AD30 I/O (io), AD31 I/O (io), AE28 I/O (io), AE29 I/O (io), AE30 I/O (io), AF28 I/O (io), AF29 I/O (io), AF30 I/O (io), AF31 I/O (io), AG28 I/O (io), AG29 I/O (io), AG30 I/O (io), AG31 I/O (io), AH17 I/O (io), AH18 I/O (io), AH19 I/O (io), AH20 I/O (io), AH22 I/O (io), AH23 I/O (io), AH24 I/O (io), AH25 I/O (io), AH26 I/O (~{LDC}) (io), AH27 I/O (HDC) (io), AH30 I/O (io), AH31 I/O (io), AJ16 I/O (io), AJ17 I/O (io), AJ18 I/O (io), AJ19 I/O (io), AJ20 I/O (io), AJ21 I/O (io), AJ22 I/O (io), AJ23 I/O (io), AJ24 I/O (io), AJ25 I/O (io), AJ26 I/O (io), AJ27 I/O (io), AJ30 I/O, GCK2 (io), AK16 I/O (~{INIT}) (io), AK17 I/O (io), AK18 I/O (io), AK19 I/O (io), AK20 I/O (io), AK21 I/O (io), AK22 I/O (io), AK23 I/O (io), AK24 I/O (io), AK25 I/O (io), AK26 I/O (io), AK27 I/O (io), AK28 I/O (io), AK29 I/O, GCK3 (io), AL16 I/O (io), AL17 I/O (io), AL19 I/O (io), AL20 I/O (io), AL22 I/O (io), AL24 I/O (io), AL26 I/O (io), AL27 I/O (io), AL28 I/O (io), B17 I/O (io), B18 I/O (io), B19 I/O (A10) (io), B20 I/O (io), B21 I/O (io), B22 I/O (io), B23 I/O (io), B24 I/O (io), B25 I/O (io), B26 I/O (A13) (io), B27 I/O (io), B28 I/O (io), B29 I/O (io), C17 I/O (io), C18 I/O (A19) (io), C19 I/O (A11) (io), C20 I/O (io), C21 I/O (io), C22 I/O (io), C23 I/O (io), C24 I/O (io), C25 I/O (io), C26 I/O (io), C27 I/O (io), C28 I/O (A14) (io), C30 I/O (A17) (io), D17 I/O (A8) (io), D18 I/O (A18) (io), D19 I/O (io), D20 I/O (io), D22 I/O (io), D23 I/O (io), D24 I/O (A12) (io), D25 I/O (io), D26 I/O (io), D27 I/O (io), D28 I/O, GCK8 (A15) (io), D29 I/O, GCK1 (A16) (io), E28 I/O (io), E29 I/O (io), E30 I/O (io), E31 I/O (io), F28 I/O (io), F29 I/O (io), F30 I/O (io), F31 I/O (io), G28 I/O (io), G29 I/O (io), G30 I/O (io), H28 I/O (io), H29 I/O (io), H30 I/O (io), H31 I/O (io), J28 I/O (io), J29 I/O (io), J30 I/O (io), K28 I/O, FCLK1 (io), K29 I/O (io), K31 I/O (io), L29 I/O (io), L30 I/O (io), M28 I/O (io), M29 I/O (io), M30 I/O (io), M31 I/O (io), N28 I/O (io), N29 I/O (io), N30 I/O (io), N31 I/O (io), P28 I/O (io), P29 I/O (io), P30 I/O (io), R28 I/O (io), R29 I/O (io), R30 I/O (io), R31 I/O (io), T29 I/O (io), T30 I/O (io), T31 I/O (io), U28 I/O (io), U29 I/O (io), U30 I/O (io), U31 I/O (io), V28 I/O (io), V29 I/O (io), V30 I/O (io), W28 I/O (io), W29 I/O (io), W30 I/O (io), W31 I/O (io), Y28 I/O (io), Y29 I/O (io), Y30 I/O (io), Y31 I/O (io)
part B pins: A4 I/O (io), A5 I/O, (CS1, A2) (io), A6 I/O (io), A8 I/O (io), A10 I/O (io), A12 I/O (io), A13 I/O (A5) (io), A15 I/O (io), A16 I/O (A7) (io), AA2 I/O (D5) (io), AA3 I/O (io), AB1 I/O, FCLK3 (io), AB2 I/O (io), AB3 I/O (io), AB4 I/O (io), AC2 I/O (io), AC3 I/O (io), AC4 I/O (io), AD1 I/O (io), AD2 I/O (io), AD3 I/O (io), AD4 I/O (io), AE2 I/O (io), AE3 I/O (io), AE4 I/O (io), AF1 I/O (D6) (io), AF2 I/O (io), AF3 I/O (io), AF4 I/O (io), AG1 I/O (io), AG2 I/O (io), AG3 I/O (io), AG4 I/O, GCK5 (io), AH1 I/O (io), AH2 I/O (io), AH5 I/O (io), AH6 I/O (io), AH7 I/O (io), AH8 I/O (io), AH9 I/O (io), AH10 I/O (io), AH12 I/O (io), AH13 I/O (io), AH14 I/O (io), AH15 I/O (io), AJ2 I/O (D7) (io), AJ4 I/O, GCK4 (io), AJ5 I/O (io), AJ6 I/O (io), AJ7 I/O (io), AJ8 I/O (io), AJ9 I/O (io), AJ10 I/O (io), AJ11 I/O (io), AJ12 I/O (io), AJ13 I/O (io), AJ14 I/O (io), AJ15 I/O (io), AK3 I/O (io), AK4 I/O (io), AK5 I/O (io), AK6 I/O (io), AK7 I/O (io), AK8 I/O (io), AK9 I/O (io), AK10 I/O (io), AK11 I/O (io), AK12 I/O (io), AK13 I/O (io), AK14 I/O (io), AK15 I/O (io), AL4 I/O (io), AL5 I/O (io), AL6 I/O (io), AL8 I/O (io), AL10 I/O (io), AL12 I/O (io), AL13 I/O (io), AL15 I/O (io), B3 I/O (A0, ~{WS}) (io), B4 I/O (io), B5 I/O (io), B6 I/O (io), B7 I/O (io), B8 I/O (io), B9 I/O (io), B10 I/O (io), B11 I/O (io), B12 I/O (io), B13 I/O (io), B14 I/O (io), B15 I/O (A20) (io), B16 I/O (A6) (io), C2 I/O (D0, DIN) (io), C5 I/O (io), C6 I/O (io), C7 I/O (io), C9 I/O (io), C10 I/O (io), C11 I/O (io), C12 I/O (io), C13 I/O (io), C14 I/O (A4) (io), C15 I/O (A21) (io), C16 I/O (io), D1 I/O (io), D2 I/O (io), D3 I/O, GCK6 (DOUT) (io), D5 I/O, GCK7 (A1) (io), D6 I/O (io), D7 I/O (A3) (io), D8 I/O (io), D9 I/O (io), D10 I/O (io), D12 I/O (io), D13 I/O (io), D14 I/O (io), D15 I/O (io), E1 I/O (io), E2 I/O (io), E3 I/O (io), E4 I/O (io), F1 I/O (io), F2 I/O (~{RCK}, RDY_~{BUSY}) (io), F3 I/O (io), F4 I/O (io), G2 I/O (io), G3 I/O (io), G4 I/O (D1) (io), H1 I/O (io), H2 I/O (io), H3 I/O (io), H4 I/O (io), J2 I/O (io), J3 I/O (io), J4 I/O (io), K1 I/O (io), K2 I/O, FCLK4 (io), K3 I/O (io), K4 I/O (io), L2 I/O (D2) (io), L3 I/O (io), M1 I/O (io), M2 I/O (io), M3 I/O (io), M4 I/O (io), N1 I/O (io), N2 I/O (io), N3 I/O (io), N4 I/O (io), P2 I/O (io), P3 I/O (io), P4 I/O (io), R1 I/O (~{RS}) (io), R2 I/O (io), R3 I/O (io), R4 I/O (io), T1 I/O (D4) (io), T2 I/O (io), T3 I/O (D3) (io), U1 I/O (io), U2 I/O (io), U3 I/O (io), U4 I/O (io), V2 I/O (io), V3 I/O (io), V4 I/O (io), W1 I/O (io), W2 I/O (io), W3 I/O (io), W4 I/O (io), Y1 I/O (io), Y2 I/O (~{CS}0) (io), Y3 I/O (io), Y4 I/O (io)
part C pins: A1 VCC (power), A2 GND (power), A3 GND (power), A7 GND (power), A9 GND (power), A11 VCC (power), A14 GND (power), A18 GND (power), A21 VCC (power), A23 GND (power), A25 GND (power), A29 GND (power), A30 GND (power), A31 VCC (power), AA1 VCC (power), AA4 VCC (power), AA28 VCC (power), AA31 VCC (power), AC1 GND (power), AC31 GND (power), AE1 GND (power), AE31 GND (power), AH3 ~{PROGRAM} (in), AH4 DONE (io), AH11 VCC (power), AH16 GND (power), AH21 VCC (power), AH28 I (M0) (in), AH29 O (M1), AJ1 GND (power), AJ3 VCC (power), AJ28 I (M2) (in), AJ29 VCC (power), AJ31 GND (power), AK1 GND (power), AK2 GND (power), AK30 GND (power), AK31 GND (power), AL1 VCC (power), AL2 GND (power), AL3 GND (power), AL7 GND (power), AL9 GND (power), AL11 VCC (power), AL14 GND (power), AL18 GND (power), AL21 VCC (power), AL23 GND (power), AL25 GND (power), AL29 GND (power), AL30 GND (power), AL31 VCC (power), B1 GND (power), B2 GND (power), B30 GND (power), B31 GND (power), C1 GND (power), C3 VCC (power), C4 O, TDO (out), C8 NC, C29 VCC (power), C31 GND (power), D4 CCLK (io), D11 VCC (power), D16 GND (power), D21 VCC (power), D30 I/O (TDI) (io), D31 I/O (TCK) (io), G1 GND (power), G31 GND (power), J1 GND (power), J31 GND (power), K30 I/O (TMS) (io), L1 VCC (power), L4 VCC (power), L28 VCC (power), L31 VCC (power), P1 GND (power), P31 GND (power), T4 GND (power), T28 GND (power), V1 GND (power), V31 GND (power)



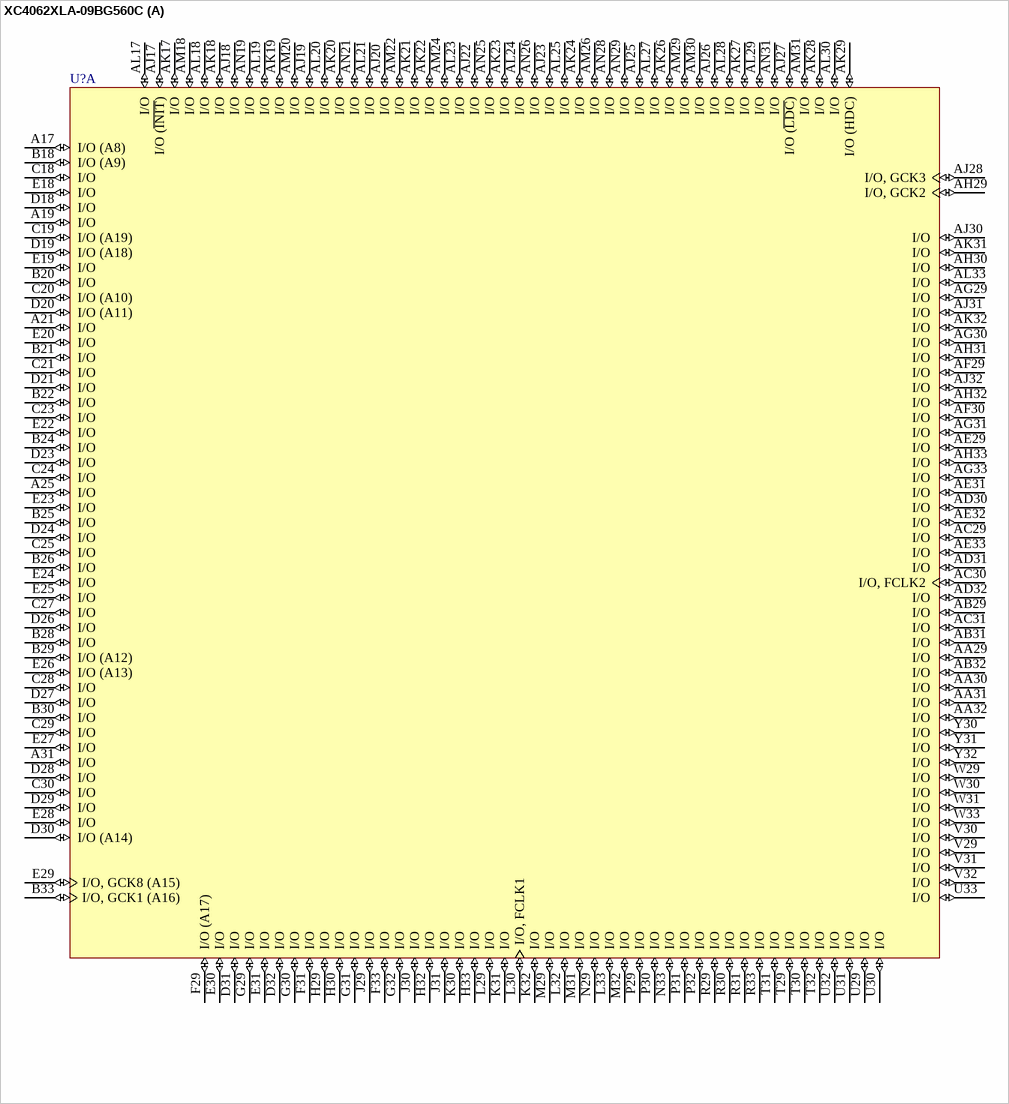
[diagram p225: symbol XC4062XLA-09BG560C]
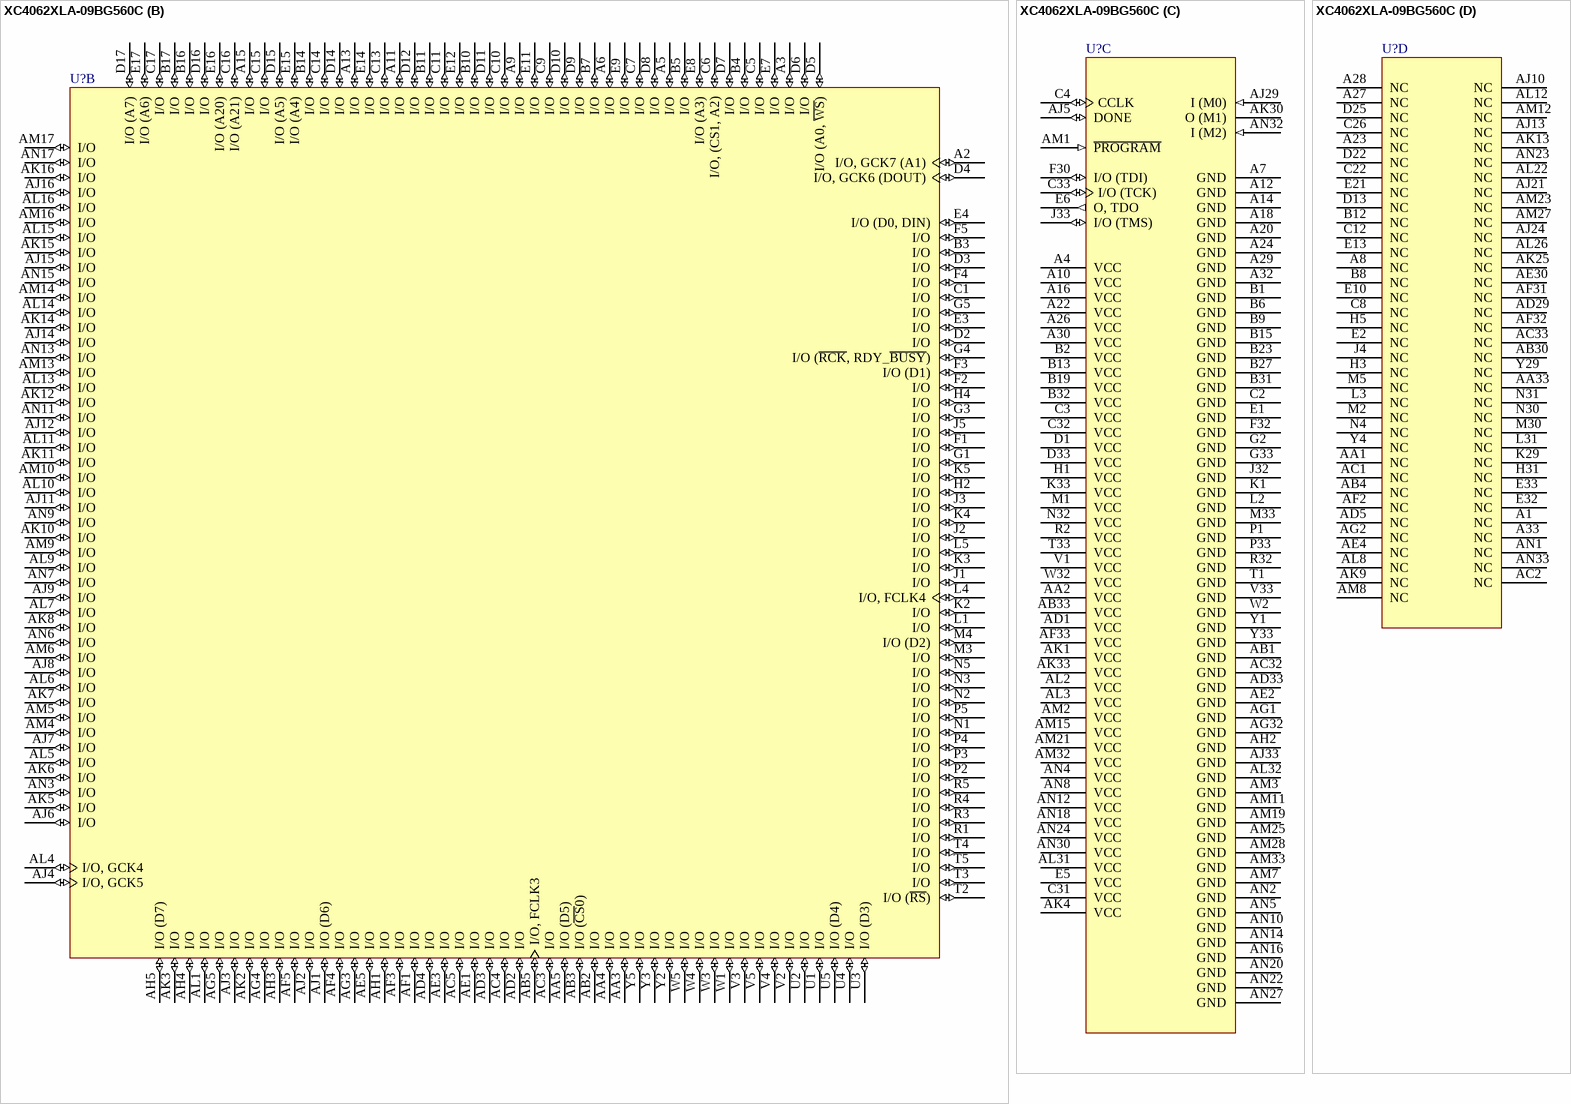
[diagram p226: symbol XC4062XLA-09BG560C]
## XC4062XLA-09BG560C
designator U?
XC4000XLA FPGA, 384 I/Os, 560-Ball BGA, Speed Grade 9, Commercial Grade
footprint BG560 (BGA, 560-Leads, Body 42.5x42.5mm, Pitch 1.27mm)
part A pins: A17 I/O (A8) (io), A19 I/O (io), A21 I/O (io), A25 I/O (io), A31 I/O (io), AA29 I/O (io), AA30 I/O (io), AA31 I/O (io), AA32 I/O (io), AB29 I/O (io), AB31 I/O (io), AB32 I/O (io), AC29 I/O (io), AC30 I/O, FCLK2 (io), AC31 I/O (io), AD30 I/O (io), AD31 I/O (io), AD32 I/O (io), AE29 I/O (io), AE31 I/O (io), AE32 I/O (io), AE33 I/O (io), AF29 I/O (io), AF30 I/O (io), AG29 I/O (io), AG30 I/O (io), AG31 I/O (io), AG33 I/O (io), AH29 I/O, GCK2 (io), AH30 I/O (io), AH31 I/O (io), AH32 I/O (io), AH33 I/O (io), AJ17 I/O (~{INIT}) (io), AJ18 I/O (io), AJ19 I/O (io), AJ20 I/O (io), AJ22 I/O (io), AJ23 I/O (io), AJ25 I/O (io), AJ26 I/O (io), AJ27 I/O (~{LDC}) (io), AJ28 I/O, GCK3 (io), AJ30 I/O (io), AJ31 I/O (io), AJ32 I/O (io), AK17 I/O (io), AK18 I/O (io), AK19 I/O (io), AK20 I/O (io), AK21 I/O (io), AK22 I/O (io), AK23 I/O (io), AK24 I/O (io), AK26 I/O (io), AK27 I/O (io), AK28 I/O (io), AK29 I/O (HDC) (io), AK31 I/O (io), AK32 I/O (io), AL17 I/O (io), AL18 I/O (io), AL19 I/O (io), AL20 I/O (io), AL21 I/O (io), AL23 I/O (io), AL24 I/O (io), AL25 I/O (io), AL27 I/O (io), AL28 I/O (io), AL29 I/O (io), AL30 I/O (io), AL33 I/O (io), AM18 I/O (io), AM20 I/O (io), AM22 I/O (io), AM24 I/O (io), AM26 I/O (io), AM29 I/O (io), AM30 I/O (io), AM31 I/O (io), AN19 I/O (io), AN21 I/O (io), AN25 I/O (io), AN26 I/O (io), AN28 I/O (io), AN29 I/O (io), AN31 I/O (io), B18 I/O (A9) (io), B20 I/O (io), B21 I/O (io), B22 I/O (io), B24 I/O (io), B25 I/O (io), B26 I/O (io), B28 I/O (io), B29 I/O (A12) (io), B30 I/O (io), B33 I/O, GCK1 (A16) (io), C18 I/O (io), C19 I/O (A19) (io), C20 I/O (A10) (io), C21 I/O (io), C23 I/O (io), C24 I/O (io), C25 I/O (io), C27 I/O (io), C28 I/O (io), C29 I/O (io), C30 I/O (io), D18 I/O (io), D19 I/O (A18) (io), D20 I/O (A11) (io), D21 I/O (io), D23 I/O (io), D24 I/O (io), D26 I/O (io), D27 I/O (io), D28 I/O (io), D29 I/O (io), D30 I/O (A14) (io), D31 I/O (io), D32 I/O (io), E18 I/O (io), E19 I/O (io), E20 I/O (io), E22 I/O (io), E23 I/O (io), E24 I/O (io), E25 I/O (io), E26 I/O (A13) (io), E27 I/O (io), E28 I/O (io), E29 I/O, GCK8 (A15) (io), E30 I/O (io), E31 I/O (io), F29 I/O (A17) (io), F31 I/O (io), F33 I/O (io), G29 I/O (io), G30 I/O (io), G31 I/O (io), G32 I/O (io), H29 I/O (io), H30 I/O (io), H32 I/O (io), H33 I/O (io), J29 I/O (io), J30 I/O (io), J31 I/O (io), K30 I/O (io), K31 I/O (io), K32 I/O (io), L29 I/O (io), L30 I/O, FCLK1 (io), L32 I/O (io), L33 I/O (io), M29 I/O (io), M31 I/O (io), M32 I/O (io), N29 I/O (io), N33 I/O (io), P29 I/O (io), P30 I/O (io), P31 I/O (io), P32 I/O (io), R29 I/O (io), R30 I/O (io), R31 I/O (io), R33 I/O (io), T29 I/O (io), T30 I/O (io), T31 I/O (io), T32 I/O (io), U29 I/O (io), U30 I/O (io), U31 I/O (io), U32 I/O (io), U33 I/O (io), V29 I/O (io), V30 I/O (io), V31 I/O (io), V32 I/O (io), W29 I/O (io), W30 I/O (io), W31 I/O (io), W33 I/O (io), Y30 I/O (io), Y31 I/O (io), Y32 I/O (io)
part B pins: A2 I/O, GCK7 (A1) (io), A3 I/O (io), A5 I/O (io), A6 I/O (io), A9 I/O (io), A11 I/O (io), A13 I/O (io), A15 I/O (io), AA3 I/O (io), AA4 I/O (io), AA5 I/O (D5) (io), AB2 I/O (io), AB3 I/O (~{CS}0) (io), AB5 I/O, FCLK3 (io), AC3 I/O (io), AC4 I/O (io), AC5 I/O (io), AD2 I/O (io), AD3 I/O (io), AD4 I/O (io), AE1 I/O (io), AE3 I/O (io), AE5 I/O (io), AF1 I/O (io), AF3 I/O (io), AF4 I/O (io), AF5 I/O (io), AG3 I/O (io), AG4 I/O (io), AG5 I/O (io), AH1 I/O (io), AH3 I/O (io), AH4 I/O (io), AH5 I/O (D7) (io), AJ1 I/O (D6) (io), AJ2 I/O (io), AJ3 I/O (io), AJ4 I/O, GCK5 (io), AJ6 I/O (io), AJ7 I/O (io), AJ8 I/O (io), AJ9 I/O (io), AJ11 I/O (io), AJ12 I/O (io), AJ14 I/O (io), AJ15 I/O (io), AJ16 I/O (io), AK2 I/O (io), AK3 I/O (io), AK5 I/O (io), AK6 I/O (io), AK7 I/O (io), AK8 I/O (io), AK10 I/O (io), AK11 I/O (io), AK12 I/O (io), AK14 I/O (io), AK15 I/O (io), AK16 I/O (io), AL1 I/O (io), AL4 I/O, GCK4 (io), AL5 I/O (io), AL6 I/O (io), AL7 I/O (io), AL9 I/O (io), AL10 I/O (io), AL11 I/O (io), AL13 I/O (io), AL14 I/O (io), AL15 I/O (io), AL16 I/O (io), AM4 I/O (io), AM5 I/O (io), AM6 I/O (io), AM9 I/O (io), AM10 I/O (io), AM13 I/O (io), AM14 I/O (io), AM16 I/O (io), AM17 I/O (io), AN3 I/O (io), AN6 I/O (io), AN7 I/O (io), AN9 I/O (io), AN11 I/O (io), AN13 I/O (io), AN15 I/O (io), AN17 I/O (io), B3 I/O (io), B4 I/O (io), B5 I/O (io), B7 I/O (io), B10 I/O (io), B11 I/O (io), B14 I/O (io), B16 I/O (io), B17 I/O (io), C1 I/O (io), C5 I/O (io), C6 I/O, (CS1, A2) (io), C7 I/O (io), C9 I/O (io), C10 I/O (io), C11 I/O (io), C13 I/O (io), C14 I/O (io), C15 I/O (io), C16 I/O (A21) (io), C17 I/O (io), D2 I/O (io), D3 I/O (io), D4 I/O, GCK6 (DOUT) (io), D5 I/O (A0, ~{WS}) (io), D6 I/O (io), D7 I/O (io), D8 I/O (io), D9 I/O (io), D10 I/O (io), D11 I/O (io), D12 I/O (io), D14 I/O (io), D15 I/O (A5) (io), D16 I/O (io), D17 I/O (A7) (io), E3 I/O (io), E4 I/O (D0, DIN) (io), E7 I/O (io), E8 I/O (A3) (io), E9 I/O (io), E11 I/O (io), E12 I/O (io), E14 I/O (io), E15 I/O (A4) (io), E16 I/O (A20) (io), E17 I/O (A6) (io), F1 I/O (io), F2 I/O (io), F3 I/O (D1) (io), F4 I/O (io), F5 I/O (io), G1 I/O (io), G3 I/O (io), G4 I/O (~{RCK}, RDY_~{BUSY}) (io), G5 I/O (io), H2 I/O (io), H4 I/O (io), J1 I/O (io), J2 I/O (io), J3 I/O (io), J5 I/O (io), K2 I/O (io), K3 I/O (io), K4 I/O (io), K5 I/O (io), L1 I/O (io), L4 I/O, FCLK4 (io), L5 I/O (io), M3 I/O (io), M4 I/O (D2) (io), N1 I/O (io), N2 I/O (io), N3 I/O (io), N5 I/O (io), P2 I/O (io), P3 I/O (io), P4 I/O (io), P5 I/O (io), R1 I/O (io), R3 I/O (io), R4 I/O (io), R5 I/O (io), T2 I/O (~{RS}) (io), T3 I/O (io), T4 I/O (io), T5 I/O (io), U1 I/O (io), U2 I/O (io), U3 I/O (D3) (io), U4 I/O (io), U5 I/O (D4) (io), V2 I/O (io), V3 I/O (io), V4 I/O (io), V5 I/O (io), W1 I/O (io), W3 I/O (io), W4 I/O (io), W5 I/O (io), Y2 I/O (io), Y3 I/O (io), Y5 I/O (io)
part C pins: A4 VCC (power), A7 GND (power), A10 VCC (power), A12 GND (power), A14 GND (power), A16 VCC (power), A18 GND (power), A20 GND (power), A22 VCC (power), A24 GND (power), A26 VCC (power), A29 GND (power), A30 VCC (power), A32 GND (power), AA2 VCC (power), AB1 GND (power), AB33 VCC (power), AC32 GND (power), AD1 VCC (power), AD33 GND (power), AE2 GND (power), AF33 VCC (power), AG1 GND (power), AG32 GND (power), AH2 GND (power), AJ5 DONE (io), AJ29 I (M0) (in), AJ33 GND (power), AK1 VCC (power), AK4 VCC (power), AK30 O (M1), AK33 VCC (power), AL2 VCC (power), AL3 VCC (power), AL31 VCC (power), AL32 GND (power), AM1 ~{PROGRAM} (in), AM2 VCC (power), AM3 GND (power), AM7 GND (power), AM11 GND (power), AM15 VCC (power), AM19 GND (power), AM21 VCC (power), AM25 GND (power), AM28 GND (power), AM32 VCC (power), AM33 GND (power), AN2 GND (power), AN4 VCC (power), AN5 GND (power), AN8 VCC (power), AN10 GND (power), AN12 VCC (power), AN14 GND (power), AN16 GND (power), AN18 VCC (power), AN20 GND (power), AN22 GND (power), AN24 VCC (power), AN27 GND (power), AN30 VCC (power), AN32 I (M2) (in), B1 GND (power), B2 VCC (power), B6 GND (power), B9 GND (power), B13 VCC (power), B15 GND (power), B19 VCC (power), B23 GND (power), B27 GND (power), B31 GND (power), B32 VCC (power), C2 GND (power), C3 VCC (power), C4 CCLK (io), C31 VCC (power), C32 VCC (power), C33 I/O (TCK) (io), D1 VCC (power), D33 VCC (power), E1 GND (power), E5 VCC (power), E6 O, TDO (out), F30 I/O (TDI) (io), F32 GND (power), G2 GND (power), G33 GND (power), H1 VCC (power), J32 GND (power), J33 I/O (TMS) (io), K1 GND (power), K33 VCC (power), L2 GND (power), M1 VCC (power), M33 GND (power), N32 VCC (power), P1 GND (power), P33 GND (power), R2 VCC (power), R32 GND (power), T1 GND (power), T33 VCC (power), V1 VCC (power), V33 GND (power), W2 GND (power), W32 VCC (power), Y1 GND (power), Y33 GND (power)
part D pins: A1 NC, A8 NC, A23 NC, A27 NC, A28 NC, A33 NC, AA1 NC, AA33 NC, AB4 NC, AB30 NC, AC1 NC, AC2 NC, AC33 NC, AD5 NC, AD29 NC, AE4 NC, AE30 NC, AF2 NC, AF31 NC, AF32 NC, AG2 NC, AJ10 NC, AJ13 NC, AJ21 NC, AJ24 NC, AK9 NC, AK13 NC, AK25 NC, AL8 NC, AL12 NC, AL22 NC, AL26 NC, AM8 NC, AM12 NC, AM23 NC, AM27 NC, AN1 NC, AN23 NC, AN33 NC, B8 NC, B12 NC, C8 NC, C12 NC, C22 NC, C26 NC, D13 NC, D22 NC, D25 NC, E2 NC, E10 NC, E13 NC, E21 NC, E32 NC, E33 NC, H3 NC, H5 NC, H31 NC, J4 NC, K29 NC, L3 NC, L31 NC, M2 NC, M5 NC, M30 NC, N4 NC, N30 NC, N31 NC, Y4 NC, Y29 NC



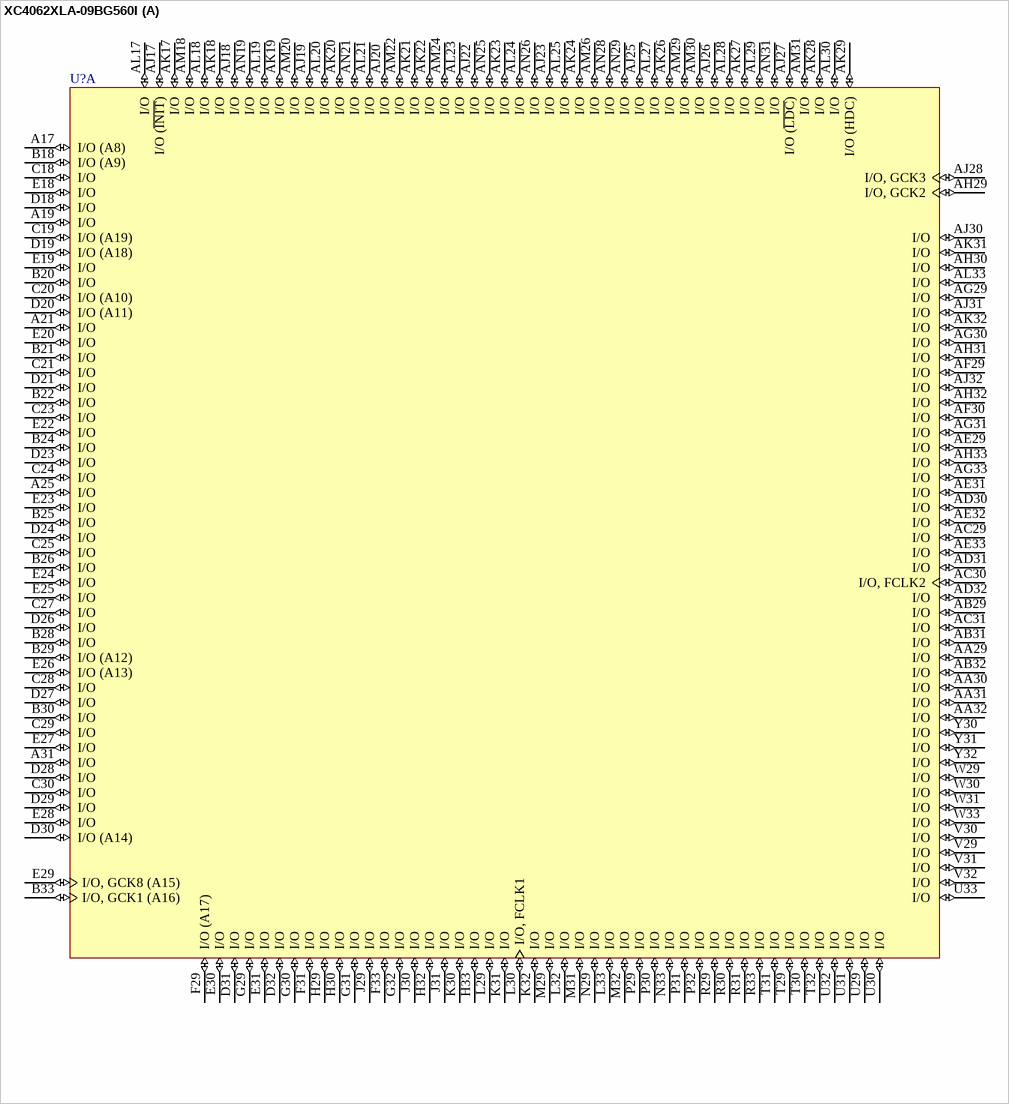
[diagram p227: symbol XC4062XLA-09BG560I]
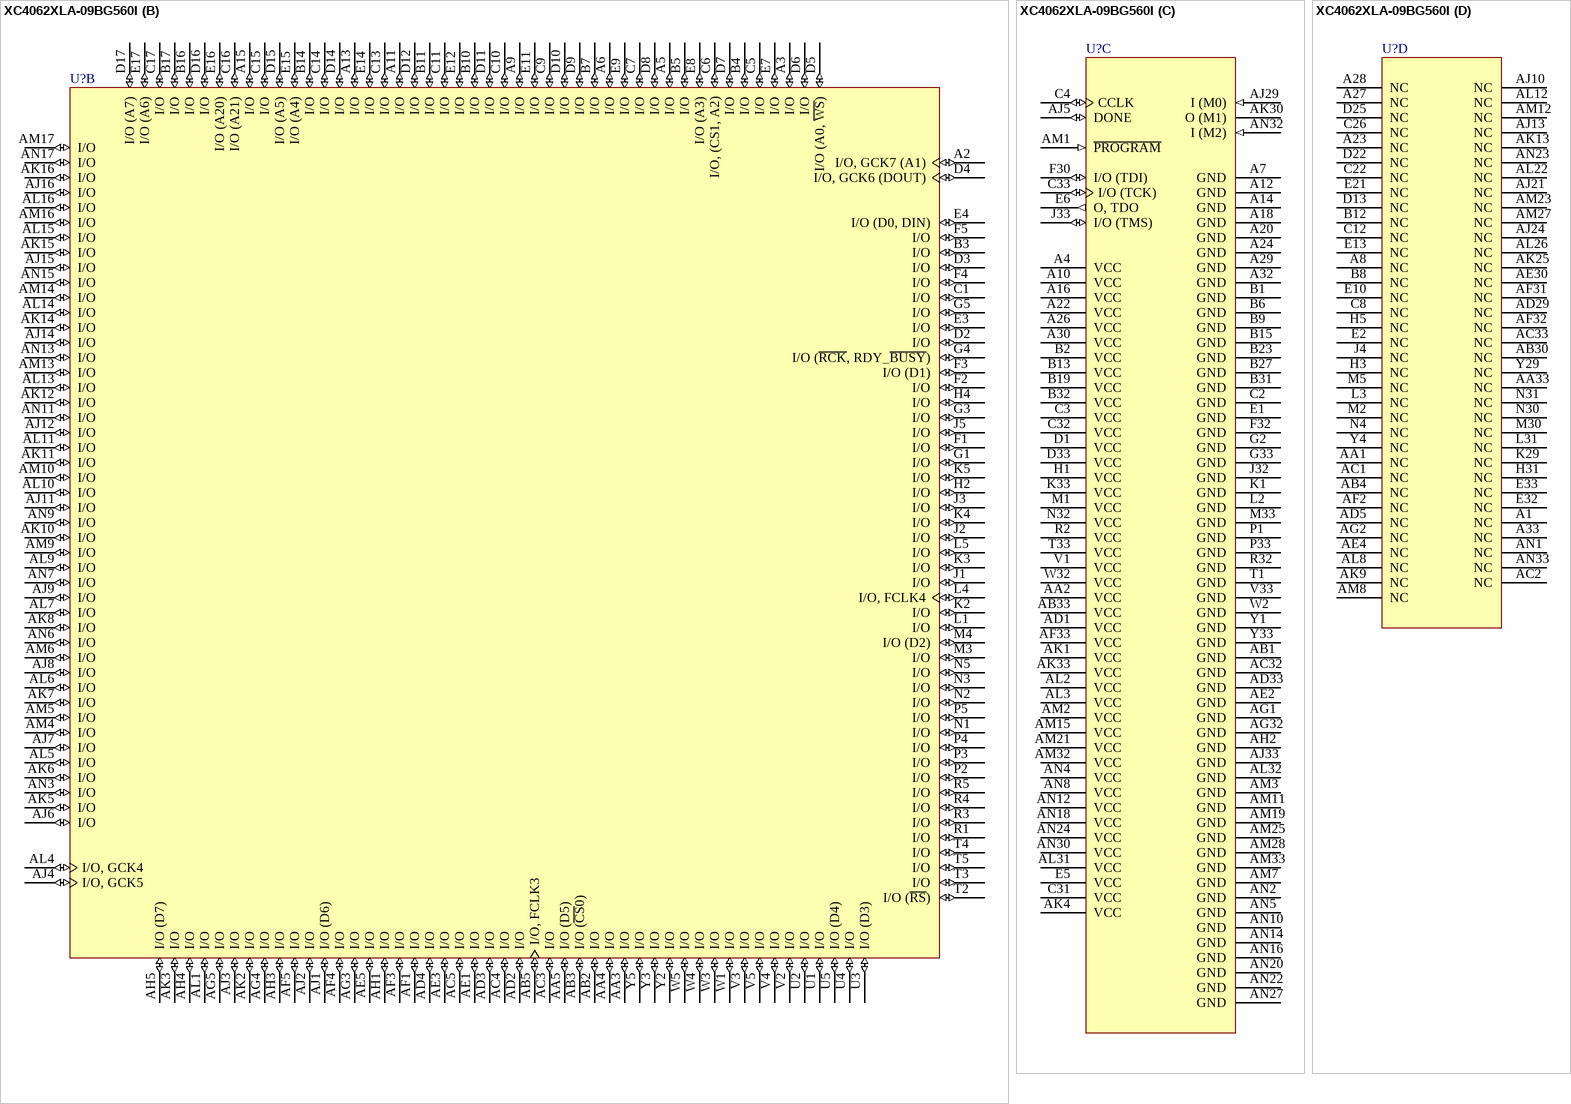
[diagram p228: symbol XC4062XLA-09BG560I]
## XC4062XLA-09BG560I
designator U?
XC4000XLA FPGA, 384 I/Os, 560-Ball BGA, Speed Grade 9, Industrial Grade
footprint BG560 (BGA, 560-Leads, Body 42.5x42.5mm, Pitch 1.27mm)
part A pins: A17 I/O (A8) (io), A19 I/O (io), A21 I/O (io), A25 I/O (io), A31 I/O (io), AA29 I/O (io), AA30 I/O (io), AA31 I/O (io), AA32 I/O (io), AB29 I/O (io), AB31 I/O (io), AB32 I/O (io), AC29 I/O (io), AC30 I/O, FCLK2 (io), AC31 I/O (io), AD30 I/O (io), AD31 I/O (io), AD32 I/O (io), AE29 I/O (io), AE31 I/O (io), AE32 I/O (io), AE33 I/O (io), AF29 I/O (io), AF30 I/O (io), AG29 I/O (io), AG30 I/O (io), AG31 I/O (io), AG33 I/O (io), AH29 I/O, GCK2 (io), AH30 I/O (io), AH31 I/O (io), AH32 I/O (io), AH33 I/O (io), AJ17 I/O (~{INIT}) (io), AJ18 I/O (io), AJ19 I/O (io), AJ20 I/O (io), AJ22 I/O (io), AJ23 I/O (io), AJ25 I/O (io), AJ26 I/O (io), AJ27 I/O (~{LDC}) (io), AJ28 I/O, GCK3 (io), AJ30 I/O (io), AJ31 I/O (io), AJ32 I/O (io), AK17 I/O (io), AK18 I/O (io), AK19 I/O (io), AK20 I/O (io), AK21 I/O (io), AK22 I/O (io), AK23 I/O (io), AK24 I/O (io), AK26 I/O (io), AK27 I/O (io), AK28 I/O (io), AK29 I/O (HDC) (io), AK31 I/O (io), AK32 I/O (io), AL17 I/O (io), AL18 I/O (io), AL19 I/O (io), AL20 I/O (io), AL21 I/O (io), AL23 I/O (io), AL24 I/O (io), AL25 I/O (io), AL27 I/O (io), AL28 I/O (io), AL29 I/O (io), AL30 I/O (io), AL33 I/O (io), AM18 I/O (io), AM20 I/O (io), AM22 I/O (io), AM24 I/O (io), AM26 I/O (io), AM29 I/O (io), AM30 I/O (io), AM31 I/O (io), AN19 I/O (io), AN21 I/O (io), AN25 I/O (io), AN26 I/O (io), AN28 I/O (io), AN29 I/O (io), AN31 I/O (io), B18 I/O (A9) (io), B20 I/O (io), B21 I/O (io), B22 I/O (io), B24 I/O (io), B25 I/O (io), B26 I/O (io), B28 I/O (io), B29 I/O (A12) (io), B30 I/O (io), B33 I/O, GCK1 (A16) (io), C18 I/O (io), C19 I/O (A19) (io), C20 I/O (A10) (io), C21 I/O (io), C23 I/O (io), C24 I/O (io), C25 I/O (io), C27 I/O (io), C28 I/O (io), C29 I/O (io), C30 I/O (io), D18 I/O (io), D19 I/O (A18) (io), D20 I/O (A11) (io), D21 I/O (io), D23 I/O (io), D24 I/O (io), D26 I/O (io), D27 I/O (io), D28 I/O (io), D29 I/O (io), D30 I/O (A14) (io), D31 I/O (io), D32 I/O (io), E18 I/O (io), E19 I/O (io), E20 I/O (io), E22 I/O (io), E23 I/O (io), E24 I/O (io), E25 I/O (io), E26 I/O (A13) (io), E27 I/O (io), E28 I/O (io), E29 I/O, GCK8 (A15) (io), E30 I/O (io), E31 I/O (io), F29 I/O (A17) (io), F31 I/O (io), F33 I/O (io), G29 I/O (io), G30 I/O (io), G31 I/O (io), G32 I/O (io), H29 I/O (io), H30 I/O (io), H32 I/O (io), H33 I/O (io), J29 I/O (io), J30 I/O (io), J31 I/O (io), K30 I/O (io), K31 I/O (io), K32 I/O (io), L29 I/O (io), L30 I/O, FCLK1 (io), L32 I/O (io), L33 I/O (io), M29 I/O (io), M31 I/O (io), M32 I/O (io), N29 I/O (io), N33 I/O (io), P29 I/O (io), P30 I/O (io), P31 I/O (io), P32 I/O (io), R29 I/O (io), R30 I/O (io), R31 I/O (io), R33 I/O (io), T29 I/O (io), T30 I/O (io), T31 I/O (io), T32 I/O (io), U29 I/O (io), U30 I/O (io), U31 I/O (io), U32 I/O (io), U33 I/O (io), V29 I/O (io), V30 I/O (io), V31 I/O (io), V32 I/O (io), W29 I/O (io), W30 I/O (io), W31 I/O (io), W33 I/O (io), Y30 I/O (io), Y31 I/O (io), Y32 I/O (io)
part B pins: A2 I/O, GCK7 (A1) (io), A3 I/O (io), A5 I/O (io), A6 I/O (io), A9 I/O (io), A11 I/O (io), A13 I/O (io), A15 I/O (io), AA3 I/O (io), AA4 I/O (io), AA5 I/O (D5) (io), AB2 I/O (io), AB3 I/O (~{CS}0) (io), AB5 I/O, FCLK3 (io), AC3 I/O (io), AC4 I/O (io), AC5 I/O (io), AD2 I/O (io), AD3 I/O (io), AD4 I/O (io), AE1 I/O (io), AE3 I/O (io), AE5 I/O (io), AF1 I/O (io), AF3 I/O (io), AF4 I/O (io), AF5 I/O (io), AG3 I/O (io), AG4 I/O (io), AG5 I/O (io), AH1 I/O (io), AH3 I/O (io), AH4 I/O (io), AH5 I/O (D7) (io), AJ1 I/O (D6) (io), AJ2 I/O (io), AJ3 I/O (io), AJ4 I/O, GCK5 (io), AJ6 I/O (io), AJ7 I/O (io), AJ8 I/O (io), AJ9 I/O (io), AJ11 I/O (io), AJ12 I/O (io), AJ14 I/O (io), AJ15 I/O (io), AJ16 I/O (io), AK2 I/O (io), AK3 I/O (io), AK5 I/O (io), AK6 I/O (io), AK7 I/O (io), AK8 I/O (io), AK10 I/O (io), AK11 I/O (io), AK12 I/O (io), AK14 I/O (io), AK15 I/O (io), AK16 I/O (io), AL1 I/O (io), AL4 I/O, GCK4 (io), AL5 I/O (io), AL6 I/O (io), AL7 I/O (io), AL9 I/O (io), AL10 I/O (io), AL11 I/O (io), AL13 I/O (io), AL14 I/O (io), AL15 I/O (io), AL16 I/O (io), AM4 I/O (io), AM5 I/O (io), AM6 I/O (io), AM9 I/O (io), AM10 I/O (io), AM13 I/O (io), AM14 I/O (io), AM16 I/O (io), AM17 I/O (io), AN3 I/O (io), AN6 I/O (io), AN7 I/O (io), AN9 I/O (io), AN11 I/O (io), AN13 I/O (io), AN15 I/O (io), AN17 I/O (io), B3 I/O (io), B4 I/O (io), B5 I/O (io), B7 I/O (io), B10 I/O (io), B11 I/O (io), B14 I/O (io), B16 I/O (io), B17 I/O (io), C1 I/O (io), C5 I/O (io), C6 I/O, (CS1, A2) (io), C7 I/O (io), C9 I/O (io), C10 I/O (io), C11 I/O (io), C13 I/O (io), C14 I/O (io), C15 I/O (io), C16 I/O (A21) (io), C17 I/O (io), D2 I/O (io), D3 I/O (io), D4 I/O, GCK6 (DOUT) (io), D5 I/O (A0, ~{WS}) (io), D6 I/O (io), D7 I/O (io), D8 I/O (io), D9 I/O (io), D10 I/O (io), D11 I/O (io), D12 I/O (io), D14 I/O (io), D15 I/O (A5) (io), D16 I/O (io), D17 I/O (A7) (io), E3 I/O (io), E4 I/O (D0, DIN) (io), E7 I/O (io), E8 I/O (A3) (io), E9 I/O (io), E11 I/O (io), E12 I/O (io), E14 I/O (io), E15 I/O (A4) (io), E16 I/O (A20) (io), E17 I/O (A6) (io), F1 I/O (io), F2 I/O (io), F3 I/O (D1) (io), F4 I/O (io), F5 I/O (io), G1 I/O (io), G3 I/O (io), G4 I/O (~{RCK}, RDY_~{BUSY}) (io), G5 I/O (io), H2 I/O (io), H4 I/O (io), J1 I/O (io), J2 I/O (io), J3 I/O (io), J5 I/O (io), K2 I/O (io), K3 I/O (io), K4 I/O (io), K5 I/O (io), L1 I/O (io), L4 I/O, FCLK4 (io), L5 I/O (io), M3 I/O (io), M4 I/O (D2) (io), N1 I/O (io), N2 I/O (io), N3 I/O (io), N5 I/O (io), P2 I/O (io), P3 I/O (io), P4 I/O (io), P5 I/O (io), R1 I/O (io), R3 I/O (io), R4 I/O (io), R5 I/O (io), T2 I/O (~{RS}) (io), T3 I/O (io), T4 I/O (io), T5 I/O (io), U1 I/O (io), U2 I/O (io), U3 I/O (D3) (io), U4 I/O (io), U5 I/O (D4) (io), V2 I/O (io), V3 I/O (io), V4 I/O (io), V5 I/O (io), W1 I/O (io), W3 I/O (io), W4 I/O (io), W5 I/O (io), Y2 I/O (io), Y3 I/O (io), Y5 I/O (io)
part C pins: A4 VCC (power), A7 GND (power), A10 VCC (power), A12 GND (power), A14 GND (power), A16 VCC (power), A18 GND (power), A20 GND (power), A22 VCC (power), A24 GND (power), A26 VCC (power), A29 GND (power), A30 VCC (power), A32 GND (power), AA2 VCC (power), AB1 GND (power), AB33 VCC (power), AC32 GND (power), AD1 VCC (power), AD33 GND (power), AE2 GND (power), AF33 VCC (power), AG1 GND (power), AG32 GND (power), AH2 GND (power), AJ5 DONE (io), AJ29 I (M0) (in), AJ33 GND (power), AK1 VCC (power), AK4 VCC (power), AK30 O (M1), AK33 VCC (power), AL2 VCC (power), AL3 VCC (power), AL31 VCC (power), AL32 GND (power), AM1 ~{PROGRAM} (in), AM2 VCC (power), AM3 GND (power), AM7 GND (power), AM11 GND (power), AM15 VCC (power), AM19 GND (power), AM21 VCC (power), AM25 GND (power), AM28 GND (power), AM32 VCC (power), AM33 GND (power), AN2 GND (power), AN4 VCC (power), AN5 GND (power), AN8 VCC (power), AN10 GND (power), AN12 VCC (power), AN14 GND (power), AN16 GND (power), AN18 VCC (power), AN20 GND (power), AN22 GND (power), AN24 VCC (power), AN27 GND (power), AN30 VCC (power), AN32 I (M2) (in), B1 GND (power), B2 VCC (power), B6 GND (power), B9 GND (power), B13 VCC (power), B15 GND (power), B19 VCC (power), B23 GND (power), B27 GND (power), B31 GND (power), B32 VCC (power), C2 GND (power), C3 VCC (power), C4 CCLK (io), C31 VCC (power), C32 VCC (power), C33 I/O (TCK) (io), D1 VCC (power), D33 VCC (power), E1 GND (power), E5 VCC (power), E6 O, TDO (out), F30 I/O (TDI) (io), F32 GND (power), G2 GND (power), G33 GND (power), H1 VCC (power), J32 GND (power), J33 I/O (TMS) (io), K1 GND (power), K33 VCC (power), L2 GND (power), M1 VCC (power), M33 GND (power), N32 VCC (power), P1 GND (power), P33 GND (power), R2 VCC (power), R32 GND (power), T1 GND (power), T33 VCC (power), V1 VCC (power), V33 GND (power), W2 GND (power), W32 VCC (power), Y1 GND (power), Y33 GND (power)
part D pins: A1 NC, A8 NC, A23 NC, A27 NC, A28 NC, A33 NC, AA1 NC, AA33 NC, AB4 NC, AB30 NC, AC1 NC, AC2 NC, AC33 NC, AD5 NC, AD29 NC, AE4 NC, AE30 NC, AF2 NC, AF31 NC, AF32 NC, AG2 NC, AJ10 NC, AJ13 NC, AJ21 NC, AJ24 NC, AK9 NC, AK13 NC, AK25 NC, AL8 NC, AL12 NC, AL22 NC, AL26 NC, AM8 NC, AM12 NC, AM23 NC, AM27 NC, AN1 NC, AN23 NC, AN33 NC, B8 NC, B12 NC, C8 NC, C12 NC, C22 NC, C26 NC, D13 NC, D22 NC, D25 NC, E2 NC, E10 NC, E13 NC, E21 NC, E32 NC, E33 NC, H3 NC, H5 NC, H31 NC, J4 NC, K29 NC, L3 NC, L31 NC, M2 NC, M5 NC, M30 NC, N4 NC, N30 NC, N31 NC, Y4 NC, Y29 NC


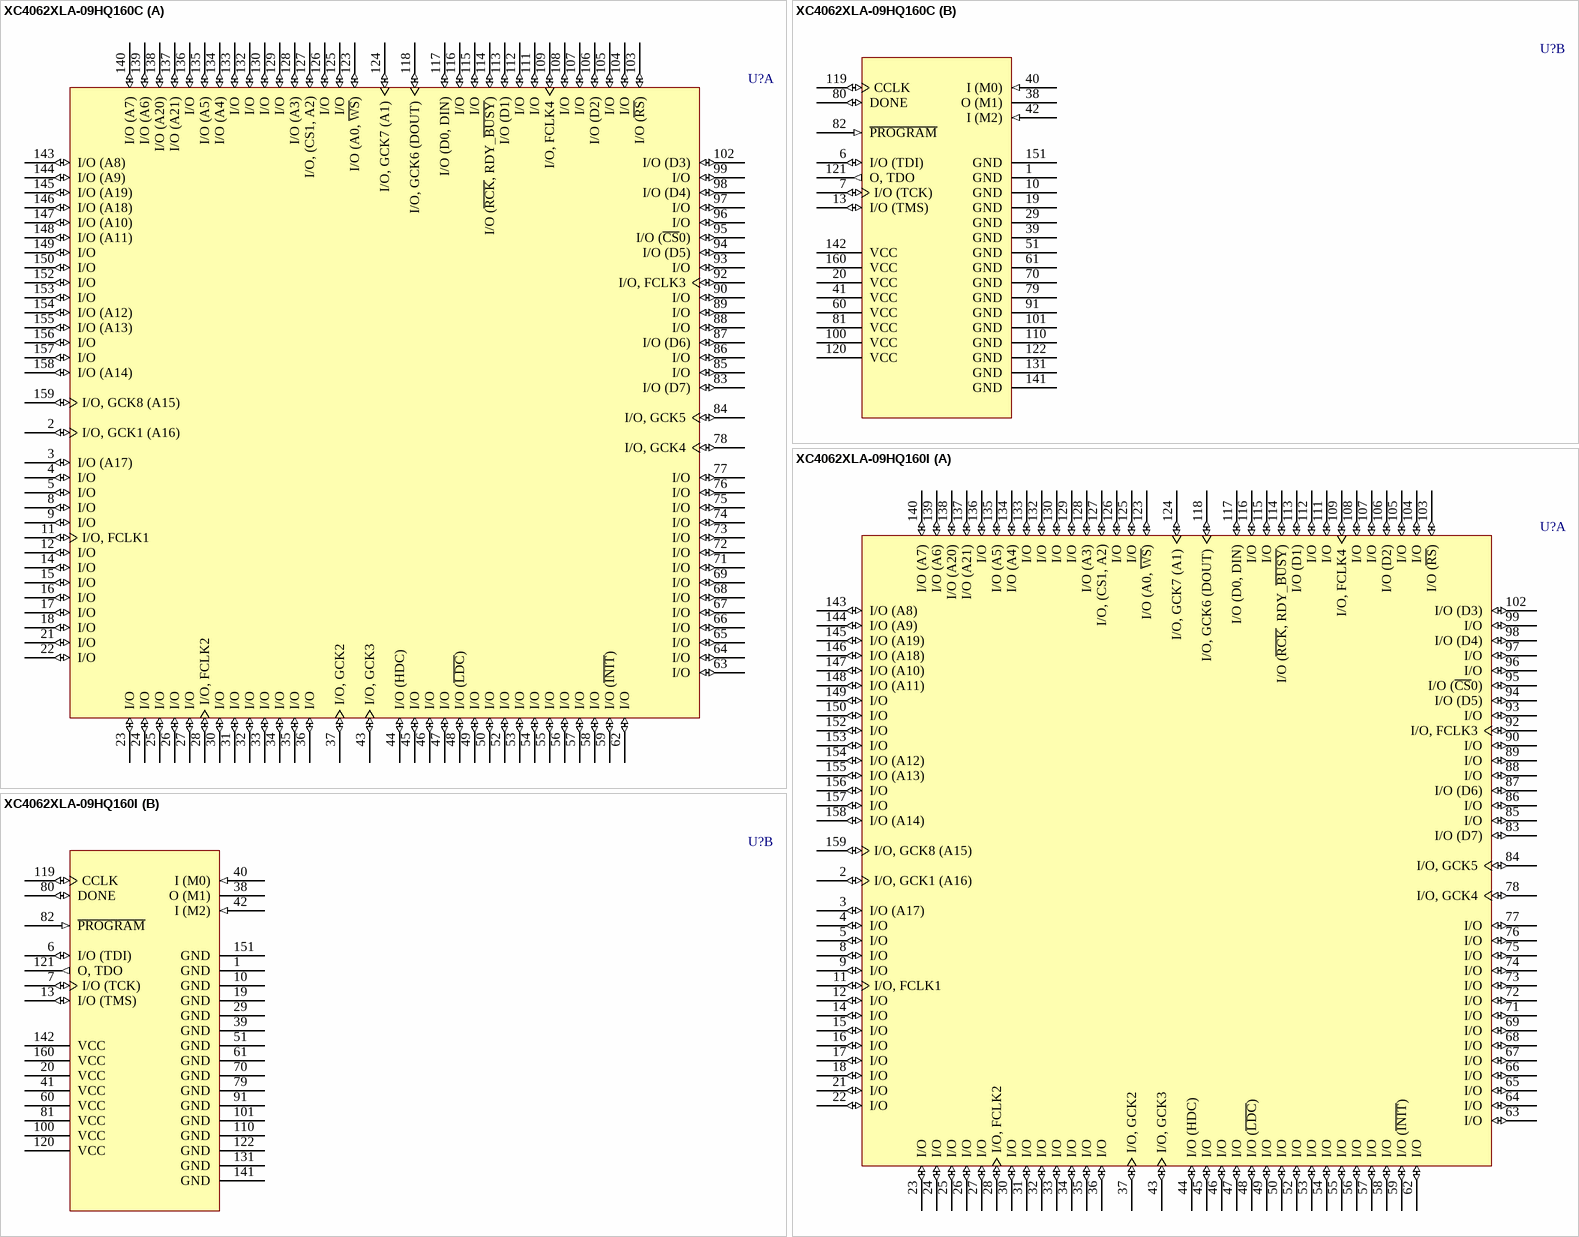
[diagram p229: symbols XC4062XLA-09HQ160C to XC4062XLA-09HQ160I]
## XC4062XLA-09HQ160C
designator U?
XC4000XLA FPGA, 129 I/Os, 160-Pin HQFP, Speed Grade 9, Commercial Grade
footprint HQ160_N (QFP, 160-Leads, Body 28x28mm, Pitch 0.65mm, IPC Medium Density)
footprint HQ160_L (QFP, 160-Leads, Body 28x28mm, Pitch 0.65mm, IPC High Density)
footprint HQ160_M (QFP, 160-Leads, Body 28x28mm, Pitch 0.65mm, IPC Low Density)
part A pins: 2 I/O, GCK1 (A16) (io), 3 I/O (A17) (io), 4 I/O (io), 5 I/O (io), 8 I/O (io), 9 I/O (io), 11 I/O, FCLK1 (io), 12 I/O (io), 14 I/O (io), 15 I/O (io), 16 I/O (io), 17 I/O (io), 18 I/O (io), 21 I/O (io), 22 I/O (io), 23 I/O (io), 24 I/O (io), 25 I/O (io), 26 I/O (io), 27 I/O (io), 28 I/O, FCLK2 (io), 30 I/O (io), 31 I/O (io), 32 I/O (io), 33 I/O (io), 34 I/O (io), 35 I/O (io), 36 I/O (io), 37 I/O, GCK2 (io), 43 I/O, GCK3 (io), 44 I/O (HDC) (io), 45 I/O (io), 46 I/O (io), 47 I/O (io), 48 I/O (~{LDC}) (io), 49 I/O (io), 50 I/O (io), 52 I/O (io), 53 I/O (io), 54 I/O (io), 55 I/O (io), 56 I/O (io), 57 I/O (io), 58 I/O (io), 59 I/O (~{INIT}) (io), 62 I/O (io), 63 I/O (io), 64 I/O (io), 65 I/O (io), 66 I/O (io), 67 I/O (io), 68 I/O (io), 69 I/O (io), 71 I/O (io), 72 I/O (io), 73 I/O (io), 74 I/O (io), 75 I/O (io), 76 I/O (io), 77 I/O (io), 78 I/O, GCK4 (io), 83 I/O (D7) (io), 84 I/O, GCK5 (io), 85 I/O (io), 86 I/O (io), 87 I/O (D6) (io), 88 I/O (io), 89 I/O (io), 90 I/O (io), 92 I/O, FCLK3 (io), 93 I/O (io), 94 I/O (D5) (io), 95 I/O (~{CS}0) (io), 96 I/O (io), 97 I/O (io), 98 I/O (D4) (io), 99 I/O (io), 102 I/O (D3) (io), 103 I/O (~{RS}) (io), 104 I/O (io), 105 I/O (io), 106 I/O (D2) (io), 107 I/O (io), 108 I/O (io), 109 I/O, FCLK4 (io), 111 I/O (io), 112 I/O (io), 113 I/O (D1) (io), 114 I/O (~{RCK}, RDY_~{BUSY}) (io), 115 I/O (io), 116 I/O (io), 117 I/O (D0, DIN) (io), 118 I/O, GCK6 (DOUT) (io), 123 I/O (A0, ~{WS}) (io), 124 I/O, GCK7 (A1) (io), 125 I/O (io), 126 I/O (io), 127 I/O, (CS1, A2) (io), 128 I/O (A3) (io), 129 I/O (io), 130 I/O (io), 132 I/O (io), 133 I/O (io), 134 I/O (A4) (io), 135 I/O (A5) (io), 136 I/O (io), 137 I/O (A21) (io), 138 I/O (A20) (io), 139 I/O (A6) (io), 140 I/O (A7) (io), 143 I/O (A8) (io), 144 I/O (A9) (io), 145 I/O (A19) (io), 146 I/O (A18) (io), 147 I/O (A10) (io), 148 I/O (A11) (io), 149 I/O (io), 150 I/O (io), 152 I/O (io), 153 I/O (io), 154 I/O (A12) (io), 155 I/O (A13) (io), 156 I/O (io), 157 I/O (io), 158 I/O (A14) (io), 159 I/O, GCK8 (A15) (io)
part B pins: 1 GND (power), 6 I/O (TDI) (io), 7 I/O (TCK) (io), 10 GND (power), 13 I/O (TMS) (io), 19 GND (power), 20 VCC (power), 29 GND (power), 38 O (M1), 39 GND (power), 40 I (M0) (in), 41 VCC (power), 42 I (M2) (in), 51 GND (power), 60 VCC (power), 61 GND (power), 70 GND (power), 79 GND (power), 80 DONE (io), 81 VCC (power), 82 ~{PROGRAM} (in), 91 GND (power), 100 VCC (power), 101 GND (power), 110 GND (power), 119 CCLK (io), 120 VCC (power), 121 O, TDO (out), 122 GND (power), 131 GND (power), 141 GND (power), 142 VCC (power), 151 GND (power), 160 VCC (power)

## XC4062XLA-09HQ160I
designator U?
XC4000XLA FPGA, 129 I/Os, 160-Pin HQFP, Speed Grade 9, Industrial Grade
footprint HQ160_N (QFP, 160-Leads, Body 28x28mm, Pitch 0.65mm, IPC Medium Density)
footprint HQ160_L (QFP, 160-Leads, Body 28x28mm, Pitch 0.65mm, IPC High Density)
footprint HQ160_M (QFP, 160-Leads, Body 28x28mm, Pitch 0.65mm, IPC Low Density)
part A pins: 2 I/O, GCK1 (A16) (io), 3 I/O (A17) (io), 4 I/O (io), 5 I/O (io), 8 I/O (io), 9 I/O (io), 11 I/O, FCLK1 (io), 12 I/O (io), 14 I/O (io), 15 I/O (io), 16 I/O (io), 17 I/O (io), 18 I/O (io), 21 I/O (io), 22 I/O (io), 23 I/O (io), 24 I/O (io), 25 I/O (io), 26 I/O (io), 27 I/O (io), 28 I/O, FCLK2 (io), 30 I/O (io), 31 I/O (io), 32 I/O (io), 33 I/O (io), 34 I/O (io), 35 I/O (io), 36 I/O (io), 37 I/O, GCK2 (io), 43 I/O, GCK3 (io), 44 I/O (HDC) (io), 45 I/O (io), 46 I/O (io), 47 I/O (io), 48 I/O (~{LDC}) (io), 49 I/O (io), 50 I/O (io), 52 I/O (io), 53 I/O (io), 54 I/O (io), 55 I/O (io), 56 I/O (io), 57 I/O (io), 58 I/O (io), 59 I/O (~{INIT}) (io), 62 I/O (io), 63 I/O (io), 64 I/O (io), 65 I/O (io), 66 I/O (io), 67 I/O (io), 68 I/O (io), 69 I/O (io), 71 I/O (io), 72 I/O (io), 73 I/O (io), 74 I/O (io), 75 I/O (io), 76 I/O (io), 77 I/O (io), 78 I/O, GCK4 (io), 83 I/O (D7) (io), 84 I/O, GCK5 (io), 85 I/O (io), 86 I/O (io), 87 I/O (D6) (io), 88 I/O (io), 89 I/O (io), 90 I/O (io), 92 I/O, FCLK3 (io), 93 I/O (io), 94 I/O (D5) (io), 95 I/O (~{CS}0) (io), 96 I/O (io), 97 I/O (io), 98 I/O (D4) (io), 99 I/O (io), 102 I/O (D3) (io), 103 I/O (~{RS}) (io), 104 I/O (io), 105 I/O (io), 106 I/O (D2) (io), 107 I/O (io), 108 I/O (io), 109 I/O, FCLK4 (io), 111 I/O (io), 112 I/O (io), 113 I/O (D1) (io), 114 I/O (~{RCK}, RDY_~{BUSY}) (io), 115 I/O (io), 116 I/O (io), 117 I/O (D0, DIN) (io), 118 I/O, GCK6 (DOUT) (io), 123 I/O (A0, ~{WS}) (io), 124 I/O, GCK7 (A1) (io), 125 I/O (io), 126 I/O (io), 127 I/O, (CS1, A2) (io), 128 I/O (A3) (io), 129 I/O (io), 130 I/O (io), 132 I/O (io), 133 I/O (io), 134 I/O (A4) (io), 135 I/O (A5) (io), 136 I/O (io), 137 I/O (A21) (io), 138 I/O (A20) (io), 139 I/O (A6) (io), 140 I/O (A7) (io), 143 I/O (A8) (io), 144 I/O (A9) (io), 145 I/O (A19) (io), 146 I/O (A18) (io), 147 I/O (A10) (io), 148 I/O (A11) (io), 149 I/O (io), 150 I/O (io), 152 I/O (io), 153 I/O (io), 154 I/O (A12) (io), 155 I/O (A13) (io), 156 I/O (io), 157 I/O (io), 158 I/O (A14) (io), 159 I/O, GCK8 (A15) (io)
part B pins: 1 GND (power), 6 I/O (TDI) (io), 7 I/O (TCK) (io), 10 GND (power), 13 I/O (TMS) (io), 19 GND (power), 20 VCC (power), 29 GND (power), 38 O (M1), 39 GND (power), 40 I (M0) (in), 41 VCC (power), 42 I (M2) (in), 51 GND (power), 60 VCC (power), 61 GND (power), 70 GND (power), 79 GND (power), 80 DONE (io), 81 VCC (power), 82 ~{PROGRAM} (in), 91 GND (power), 100 VCC (power), 101 GND (power), 110 GND (power), 119 CCLK (io), 120 VCC (power), 121 O, TDO (out), 122 GND (power), 131 GND (power), 141 GND (power), 142 VCC (power), 151 GND (power), 160 VCC (power)


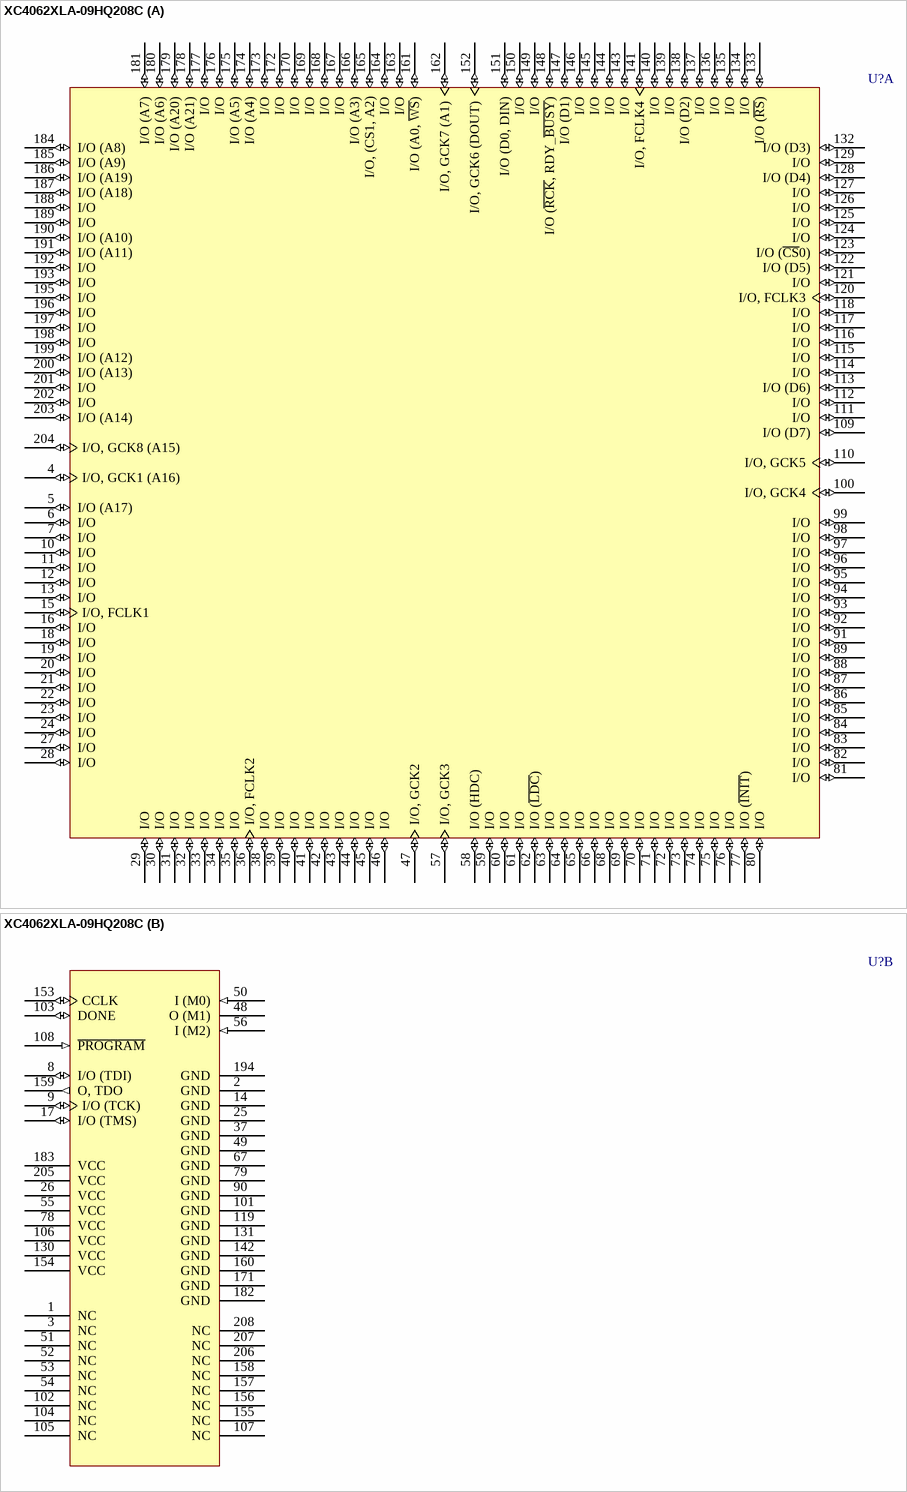
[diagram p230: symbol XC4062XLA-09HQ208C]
## XC4062XLA-09HQ208C
designator U?
XC4000XLA FPGA, 160 I/Os, 208-Pin HQFP, Speed Grade 9, Commercial Grade
footprint HQ208_N (Shrink QFP, 208-Leads, Body 28x28mm, Pitch 0.5mm, IPC Medium Density)
footprint HQ208_L (Shrink QFP, 208-Leads, Body 28x28mm, Pitch 0.5mm, IPC High Density)
footprint HQ208_M (Shrink QFP, 208-Leads, Body 28x28mm, Pitch 0.5mm, IPC Low Density)
part A pins: 4 I/O, GCK1 (A16) (io), 5 I/O (A17) (io), 6 I/O (io), 7 I/O (io), 10 I/O (io), 11 I/O (io), 12 I/O (io), 13 I/O (io), 15 I/O, FCLK1 (io), 16 I/O (io), 18 I/O (io), 19 I/O (io), 20 I/O (io), 21 I/O (io), 22 I/O (io), 23 I/O (io), 24 I/O (io), 27 I/O (io), 28 I/O (io), 29 I/O (io), 30 I/O (io), 31 I/O (io), 32 I/O (io), 33 I/O (io), 34 I/O (io), 35 I/O (io), 36 I/O, FCLK2 (io), 38 I/O (io), 39 I/O (io), 40 I/O (io), 41 I/O (io), 42 I/O (io), 43 I/O (io), 44 I/O (io), 45 I/O (io), 46 I/O (io), 47 I/O, GCK2 (io), 57 I/O, GCK3 (io), 58 I/O (HDC) (io), 59 I/O (io), 60 I/O (io), 61 I/O (io), 62 I/O (~{LDC}) (io), 63 I/O (io), 64 I/O (io), 65 I/O (io), 66 I/O (io), 68 I/O (io), 69 I/O (io), 70 I/O (io), 71 I/O (io), 72 I/O (io), 73 I/O (io), 74 I/O (io), 75 I/O (io), 76 I/O (io), 77 I/O (~{INIT}) (io), 80 I/O (io), 81 I/O (io), 82 I/O (io), 83 I/O (io), 84 I/O (io), 85 I/O (io), 86 I/O (io), 87 I/O (io), 88 I/O (io), 89 I/O (io), 91 I/O (io), 92 I/O (io), 93 I/O (io), 94 I/O (io), 95 I/O (io), 96 I/O (io), 97 I/O (io), 98 I/O (io), 99 I/O (io), 100 I/O, GCK4 (io), 109 I/O (D7) (io), 110 I/O, GCK5 (io), 111 I/O (io), 112 I/O (io), 113 I/O (D6) (io), 114 I/O (io), 115 I/O (io), 116 I/O (io), 117 I/O (io), 118 I/O (io), 120 I/O, FCLK3 (io), 121 I/O (io), 122 I/O (D5) (io), 123 I/O (~{CS}0) (io), 124 I/O (io), 125 I/O (io), 126 I/O (io), 127 I/O (io), 128 I/O (D4) (io), 129 I/O (io), 132 I/O (D3) (io), 133 I/O (~{RS}) (io), 134 I/O (io), 135 I/O (io), 136 I/O (io), 137 I/O (io), 138 I/O (D2) (io), 139 I/O (io), 140 I/O (io), 141 I/O, FCLK4 (io), 143 I/O (io), 144 I/O (io), 145 I/O (io), 146 I/O (io), 147 I/O (D1) (io), 148 I/O (~{RCK}, RDY_~{BUSY}) (io), 149 I/O (io), 150 I/O (io), 151 I/O (D0, DIN) (io), 152 I/O, GCK6 (DOUT) (io), 161 I/O (A0, ~{WS}) (io), 162 I/O, GCK7 (A1) (io), 163 I/O (io), 164 I/O (io), 165 I/O, (CS1, A2) (io), 166 I/O (A3) (io), 167 I/O (io), 168 I/O (io), 169 I/O (io), 170 I/O (io), 172 I/O (io), 173 I/O (io), 174 I/O (A4) (io), 175 I/O (A5) (io), 176 I/O (io), 177 I/O (io), 178 I/O (A21) (io), 179 I/O (A20) (io), 180 I/O (A6) (io), 181 I/O (A7) (io), 184 I/O (A8) (io), 185 I/O (A9) (io), 186 I/O (A19) (io), 187 I/O (A18) (io), 188 I/O (io), 189 I/O (io), 190 I/O (A10) (io), 191 I/O (A11) (io), 192 I/O (io), 193 I/O (io), 195 I/O (io), 196 I/O (io), 197 I/O (io), 198 I/O (io), 199 I/O (A12) (io), 200 I/O (A13) (io), 201 I/O (io), 202 I/O (io), 203 I/O (A14) (io), 204 I/O, GCK8 (A15) (io)
part B pins: 1 NC, 2 GND (power), 3 NC, 8 I/O (TDI) (io), 9 I/O (TCK) (io), 14 GND (power), 17 I/O (TMS) (io), 25 GND (power), 26 VCC (power), 37 GND (power), 48 O (M1), 49 GND (power), 50 I (M0) (in), 51 NC, 52 NC, 53 NC, 54 NC, 55 VCC (power), 56 I (M2) (in), 67 GND (power), 78 VCC (power), 79 GND (power), 90 GND (power), 101 GND (power), 102 NC, 103 DONE (io), 104 NC, 105 NC, 106 VCC (power), 107 NC, 108 ~{PROGRAM} (in), 119 GND (power), 130 VCC (power), 131 GND (power), 142 GND (power), 153 CCLK (io), 154 VCC (power), 155 NC, 156 NC, 157 NC, 158 NC, 159 O, TDO (out), 160 GND (power), 171 GND (power), 182 GND (power), 183 VCC (power), 194 GND (power), 205 VCC (power), 206 NC, 207 NC, 208 NC


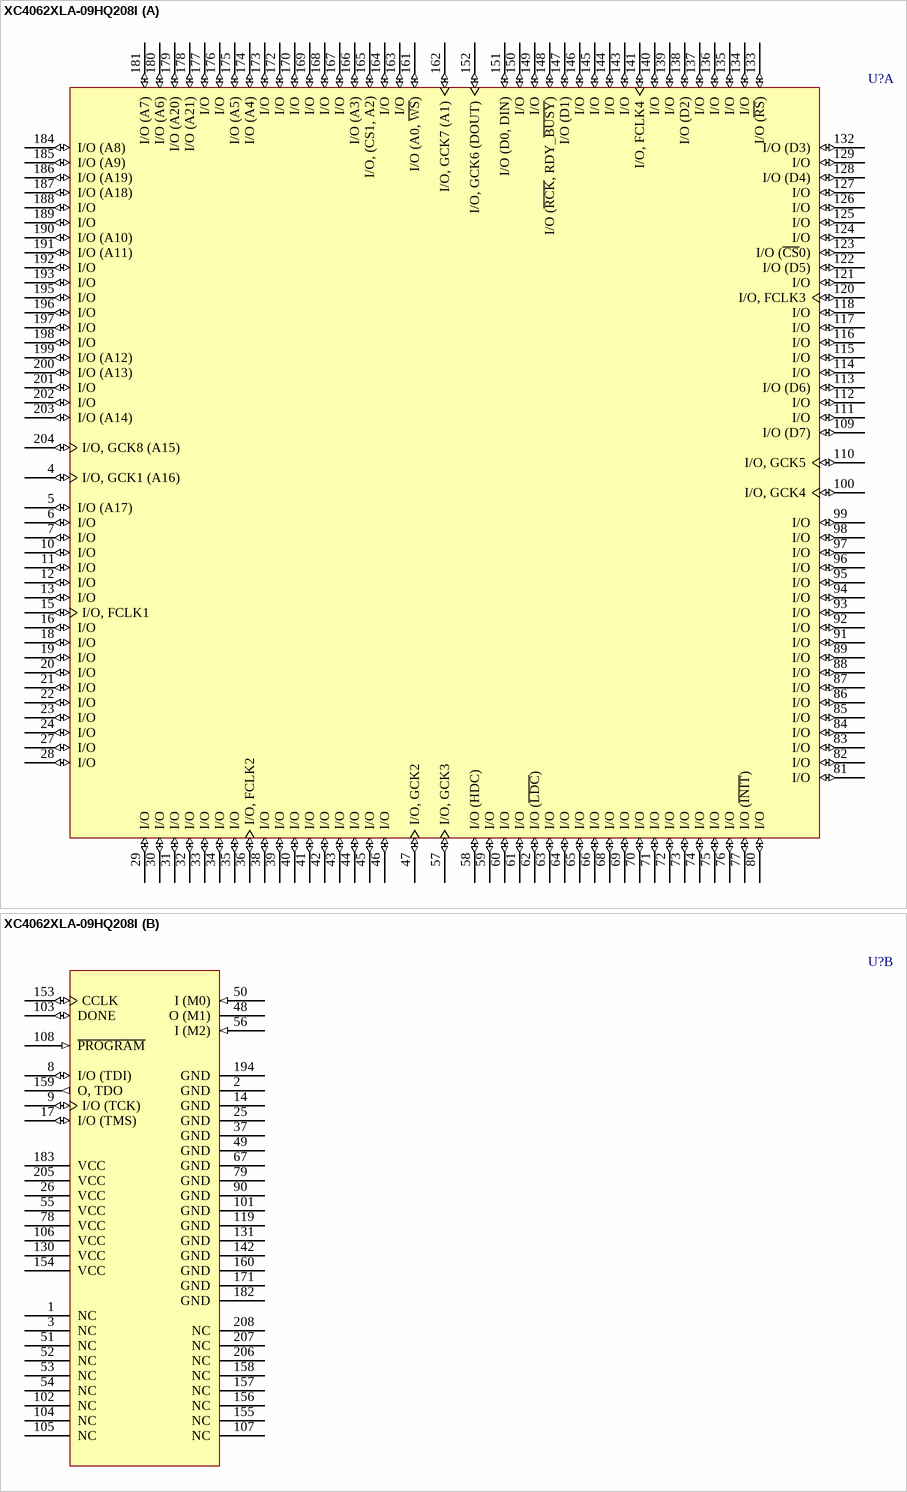
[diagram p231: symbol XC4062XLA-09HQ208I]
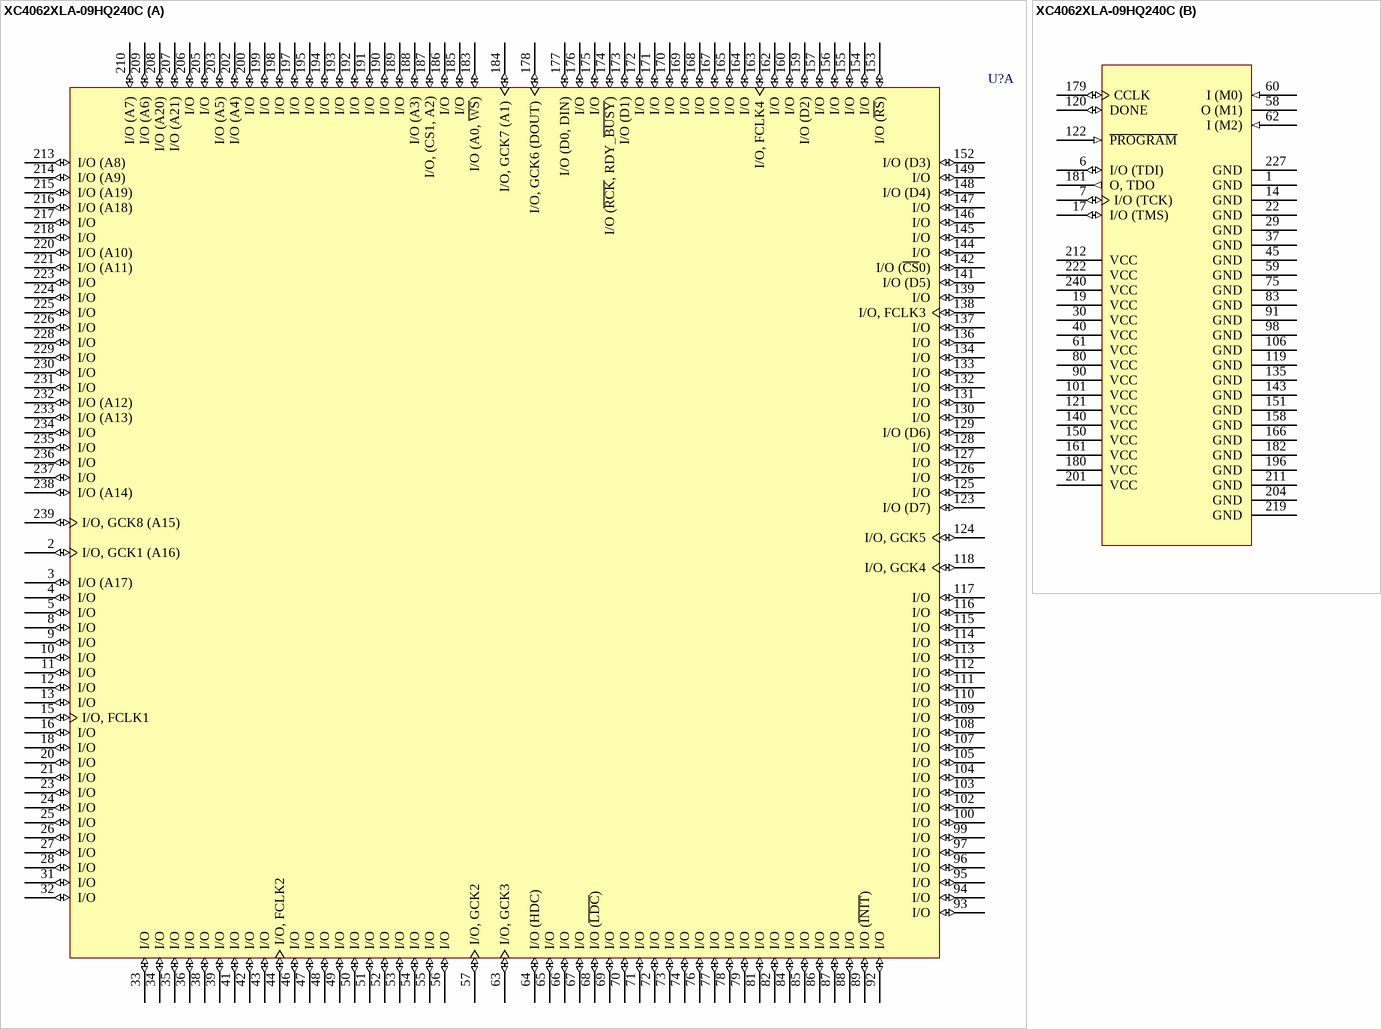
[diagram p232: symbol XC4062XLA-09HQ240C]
## XC4062XLA-09HQ208I
designator U?
XC4000XLA FPGA, 160 I/Os, 208-Pin HQFP, Speed Grade 9, Industrial Grade
footprint HQ208_N (Shrink QFP, 208-Leads, Body 28x28mm, Pitch 0.5mm, IPC Medium Density)
footprint HQ208_L (Shrink QFP, 208-Leads, Body 28x28mm, Pitch 0.5mm, IPC High Density)
footprint HQ208_M (Shrink QFP, 208-Leads, Body 28x28mm, Pitch 0.5mm, IPC Low Density)
part A pins: 4 I/O, GCK1 (A16) (io), 5 I/O (A17) (io), 6 I/O (io), 7 I/O (io), 10 I/O (io), 11 I/O (io), 12 I/O (io), 13 I/O (io), 15 I/O, FCLK1 (io), 16 I/O (io), 18 I/O (io), 19 I/O (io), 20 I/O (io), 21 I/O (io), 22 I/O (io), 23 I/O (io), 24 I/O (io), 27 I/O (io), 28 I/O (io), 29 I/O (io), 30 I/O (io), 31 I/O (io), 32 I/O (io), 33 I/O (io), 34 I/O (io), 35 I/O (io), 36 I/O, FCLK2 (io), 38 I/O (io), 39 I/O (io), 40 I/O (io), 41 I/O (io), 42 I/O (io), 43 I/O (io), 44 I/O (io), 45 I/O (io), 46 I/O (io), 47 I/O, GCK2 (io), 57 I/O, GCK3 (io), 58 I/O (HDC) (io), 59 I/O (io), 60 I/O (io), 61 I/O (io), 62 I/O (~{LDC}) (io), 63 I/O (io), 64 I/O (io), 65 I/O (io), 66 I/O (io), 68 I/O (io), 69 I/O (io), 70 I/O (io), 71 I/O (io), 72 I/O (io), 73 I/O (io), 74 I/O (io), 75 I/O (io), 76 I/O (io), 77 I/O (~{INIT}) (io), 80 I/O (io), 81 I/O (io), 82 I/O (io), 83 I/O (io), 84 I/O (io), 85 I/O (io), 86 I/O (io), 87 I/O (io), 88 I/O (io), 89 I/O (io), 91 I/O (io), 92 I/O (io), 93 I/O (io), 94 I/O (io), 95 I/O (io), 96 I/O (io), 97 I/O (io), 98 I/O (io), 99 I/O (io), 100 I/O, GCK4 (io), 109 I/O (D7) (io), 110 I/O, GCK5 (io), 111 I/O (io), 112 I/O (io), 113 I/O (D6) (io), 114 I/O (io), 115 I/O (io), 116 I/O (io), 117 I/O (io), 118 I/O (io), 120 I/O, FCLK3 (io), 121 I/O (io), 122 I/O (D5) (io), 123 I/O (~{CS}0) (io), 124 I/O (io), 125 I/O (io), 126 I/O (io), 127 I/O (io), 128 I/O (D4) (io), 129 I/O (io), 132 I/O (D3) (io), 133 I/O (~{RS}) (io), 134 I/O (io), 135 I/O (io), 136 I/O (io), 137 I/O (io), 138 I/O (D2) (io), 139 I/O (io), 140 I/O (io), 141 I/O, FCLK4 (io), 143 I/O (io), 144 I/O (io), 145 I/O (io), 146 I/O (io), 147 I/O (D1) (io), 148 I/O (~{RCK}, RDY_~{BUSY}) (io), 149 I/O (io), 150 I/O (io), 151 I/O (D0, DIN) (io), 152 I/O, GCK6 (DOUT) (io), 161 I/O (A0, ~{WS}) (io), 162 I/O, GCK7 (A1) (io), 163 I/O (io), 164 I/O (io), 165 I/O, (CS1, A2) (io), 166 I/O (A3) (io), 167 I/O (io), 168 I/O (io), 169 I/O (io), 170 I/O (io), 172 I/O (io), 173 I/O (io), 174 I/O (A4) (io), 175 I/O (A5) (io), 176 I/O (io), 177 I/O (io), 178 I/O (A21) (io), 179 I/O (A20) (io), 180 I/O (A6) (io), 181 I/O (A7) (io), 184 I/O (A8) (io), 185 I/O (A9) (io), 186 I/O (A19) (io), 187 I/O (A18) (io), 188 I/O (io), 189 I/O (io), 190 I/O (A10) (io), 191 I/O (A11) (io), 192 I/O (io), 193 I/O (io), 195 I/O (io), 196 I/O (io), 197 I/O (io), 198 I/O (io), 199 I/O (A12) (io), 200 I/O (A13) (io), 201 I/O (io), 202 I/O (io), 203 I/O (A14) (io), 204 I/O, GCK8 (A15) (io)
part B pins: 1 NC, 2 GND (power), 3 NC, 8 I/O (TDI) (io), 9 I/O (TCK) (io), 14 GND (power), 17 I/O (TMS) (io), 25 GND (power), 26 VCC (power), 37 GND (power), 48 O (M1), 49 GND (power), 50 I (M0) (in), 51 NC, 52 NC, 53 NC, 54 NC, 55 VCC (power), 56 I (M2) (in), 67 GND (power), 78 VCC (power), 79 GND (power), 90 GND (power), 101 GND (power), 102 NC, 103 DONE (io), 104 NC, 105 NC, 106 VCC (power), 107 NC, 108 ~{PROGRAM} (in), 119 GND (power), 130 VCC (power), 131 GND (power), 142 GND (power), 153 CCLK (io), 154 VCC (power), 155 NC, 156 NC, 157 NC, 158 NC, 159 O, TDO (out), 160 GND (power), 171 GND (power), 182 GND (power), 183 VCC (power), 194 GND (power), 205 VCC (power), 206 NC, 207 NC, 208 NC

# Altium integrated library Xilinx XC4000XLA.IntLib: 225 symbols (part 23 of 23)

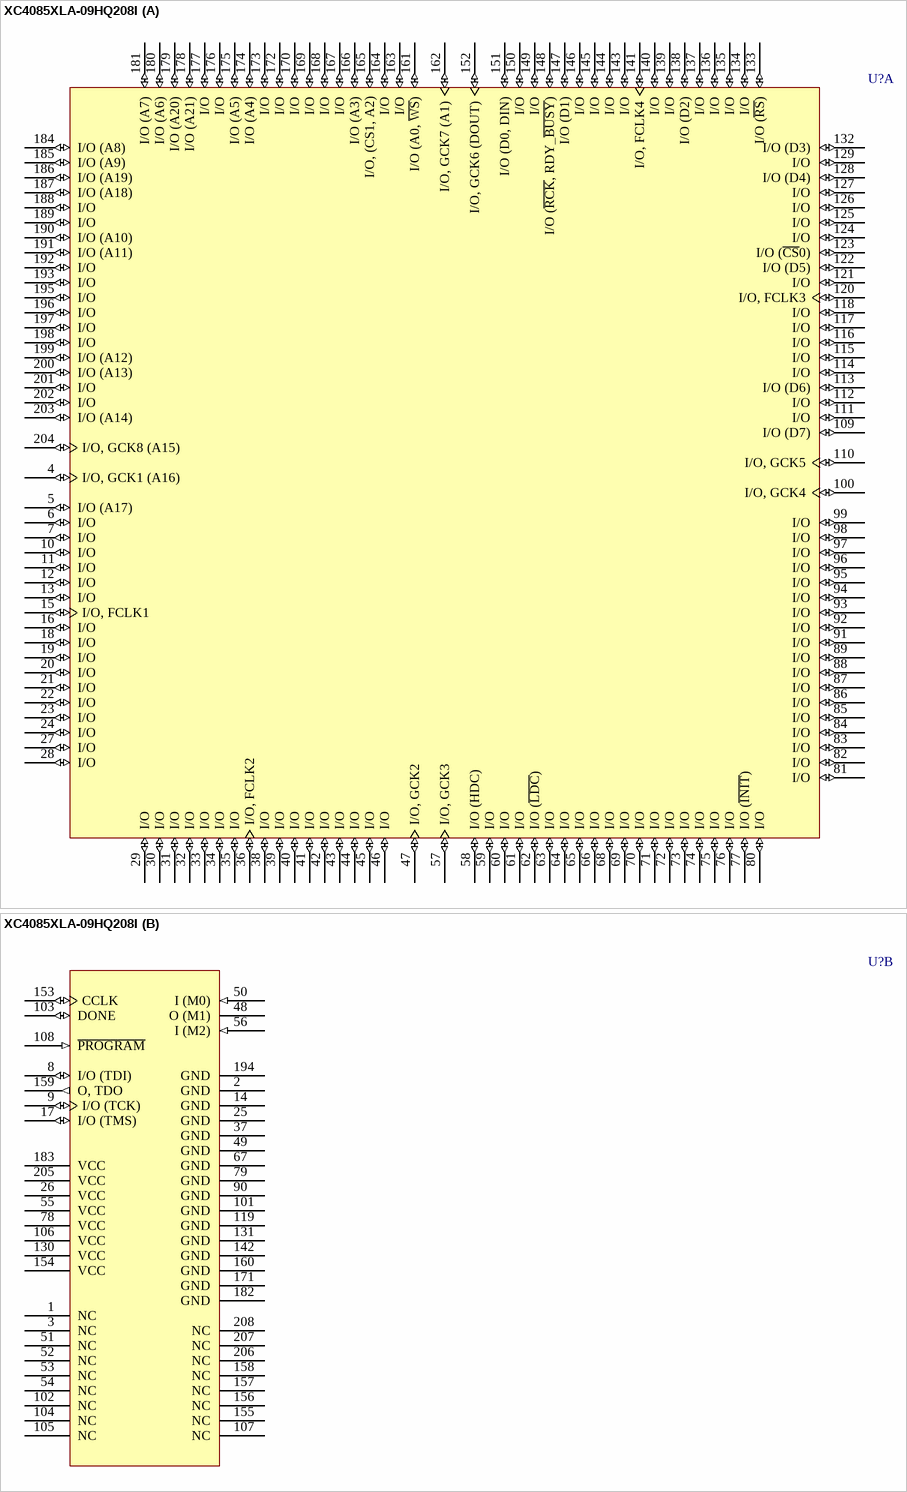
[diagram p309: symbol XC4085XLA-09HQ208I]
## XC4085XLA-09HQ208I
designator U?
XC4000XLA FPGA, 160 I/Os, 208-Pin HQFP, Speed Grade 9, Industrial Grade
footprint HQ208_N (Shrink QFP, 208-Leads, Body 28x28mm, Pitch 0.5mm, IPC Medium Density)
footprint HQ208_L (Shrink QFP, 208-Leads, Body 28x28mm, Pitch 0.5mm, IPC High Density)
footprint HQ208_M (Shrink QFP, 208-Leads, Body 28x28mm, Pitch 0.5mm, IPC Low Density)
part A pins: 4 I/O, GCK1 (A16) (io), 5 I/O (A17) (io), 6 I/O (io), 7 I/O (io), 10 I/O (io), 11 I/O (io), 12 I/O (io), 13 I/O (io), 15 I/O, FCLK1 (io), 16 I/O (io), 18 I/O (io), 19 I/O (io), 20 I/O (io), 21 I/O (io), 22 I/O (io), 23 I/O (io), 24 I/O (io), 27 I/O (io), 28 I/O (io), 29 I/O (io), 30 I/O (io), 31 I/O (io), 32 I/O (io), 33 I/O (io), 34 I/O (io), 35 I/O (io), 36 I/O, FCLK2 (io), 38 I/O (io), 39 I/O (io), 40 I/O (io), 41 I/O (io), 42 I/O (io), 43 I/O (io), 44 I/O (io), 45 I/O (io), 46 I/O (io), 47 I/O, GCK2 (io), 57 I/O, GCK3 (io), 58 I/O (HDC) (io), 59 I/O (io), 60 I/O (io), 61 I/O (io), 62 I/O (~{LDC}) (io), 63 I/O (io), 64 I/O (io), 65 I/O (io), 66 I/O (io), 68 I/O (io), 69 I/O (io), 70 I/O (io), 71 I/O (io), 72 I/O (io), 73 I/O (io), 74 I/O (io), 75 I/O (io), 76 I/O (io), 77 I/O (~{INIT}) (io), 80 I/O (io), 81 I/O (io), 82 I/O (io), 83 I/O (io), 84 I/O (io), 85 I/O (io), 86 I/O (io), 87 I/O (io), 88 I/O (io), 89 I/O (io), 91 I/O (io), 92 I/O (io), 93 I/O (io), 94 I/O (io), 95 I/O (io), 96 I/O (io), 97 I/O (io), 98 I/O (io), 99 I/O (io), 100 I/O, GCK4 (io), 109 I/O (D7) (io), 110 I/O, GCK5 (io), 111 I/O (io), 112 I/O (io), 113 I/O (D6) (io), 114 I/O (io), 115 I/O (io), 116 I/O (io), 117 I/O (io), 118 I/O (io), 120 I/O, FCLK3 (io), 121 I/O (io), 122 I/O (D5) (io), 123 I/O (~{CS}0) (io), 124 I/O (io), 125 I/O (io), 126 I/O (io), 127 I/O (io), 128 I/O (D4) (io), 129 I/O (io), 132 I/O (D3) (io), 133 I/O (~{RS}) (io), 134 I/O (io), 135 I/O (io), 136 I/O (io), 137 I/O (io), 138 I/O (D2) (io), 139 I/O (io), 140 I/O (io), 141 I/O, FCLK4 (io), 143 I/O (io), 144 I/O (io), 145 I/O (io), 146 I/O (io), 147 I/O (D1) (io), 148 I/O (~{RCK}, RDY_~{BUSY}) (io), 149 I/O (io), 150 I/O (io), 151 I/O (D0, DIN) (io), 152 I/O, GCK6 (DOUT) (io), 161 I/O (A0, ~{WS}) (io), 162 I/O, GCK7 (A1) (io), 163 I/O (io), 164 I/O (io), 165 I/O, (CS1, A2) (io), 166 I/O (A3) (io), 167 I/O (io), 168 I/O (io), 169 I/O (io), 170 I/O (io), 172 I/O (io), 173 I/O (io), 174 I/O (A4) (io), 175 I/O (A5) (io), 176 I/O (io), 177 I/O (io), 178 I/O (A21) (io), 179 I/O (A20) (io), 180 I/O (A6) (io), 181 I/O (A7) (io), 184 I/O (A8) (io), 185 I/O (A9) (io), 186 I/O (A19) (io), 187 I/O (A18) (io), 188 I/O (io), 189 I/O (io), 190 I/O (A10) (io), 191 I/O (A11) (io), 192 I/O (io), 193 I/O (io), 195 I/O (io), 196 I/O (io), 197 I/O (io), 198 I/O (io), 199 I/O (A12) (io), 200 I/O (A13) (io), 201 I/O (io), 202 I/O (io), 203 I/O (A14) (io), 204 I/O, GCK8 (A15) (io)
part B pins: 1 NC, 2 GND (power), 3 NC, 8 I/O (TDI) (io), 9 I/O (TCK) (io), 14 GND (power), 17 I/O (TMS) (io), 25 GND (power), 26 VCC (power), 37 GND (power), 48 O (M1), 49 GND (power), 50 I (M0) (in), 51 NC, 52 NC, 53 NC, 54 NC, 55 VCC (power), 56 I (M2) (in), 67 GND (power), 78 VCC (power), 79 GND (power), 90 GND (power), 101 GND (power), 102 NC, 103 DONE (io), 104 NC, 105 NC, 106 VCC (power), 107 NC, 108 ~{PROGRAM} (in), 119 GND (power), 130 VCC (power), 131 GND (power), 142 GND (power), 153 CCLK (io), 154 VCC (power), 155 NC, 156 NC, 157 NC, 158 NC, 159 O, TDO (out), 160 GND (power), 171 GND (power), 182 GND (power), 183 VCC (power), 194 GND (power), 205 VCC (power), 206 NC, 207 NC, 208 NC


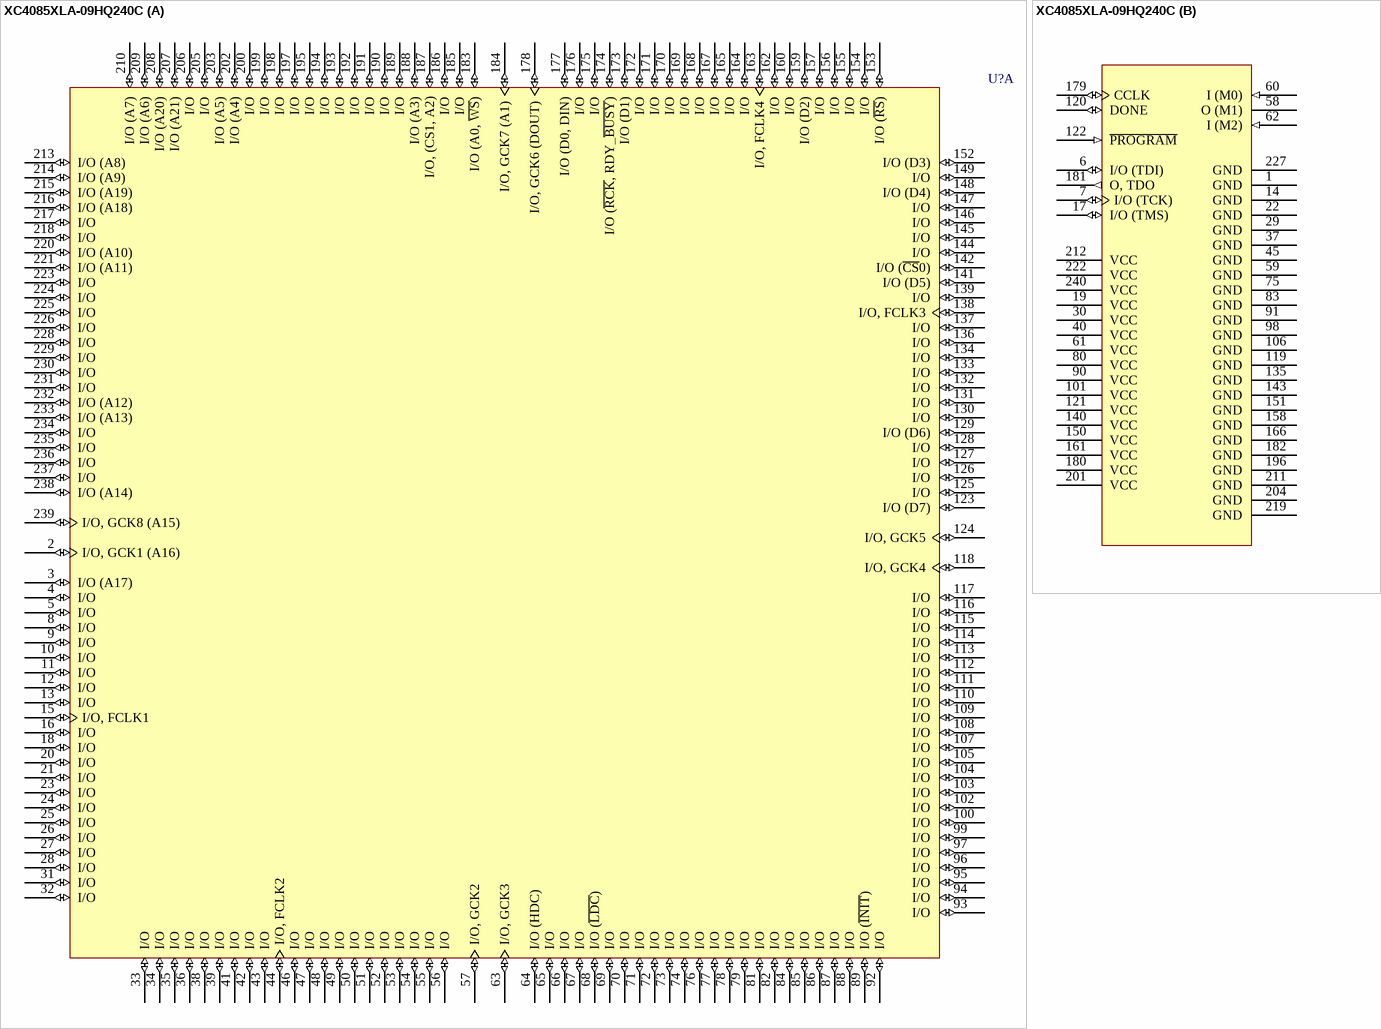
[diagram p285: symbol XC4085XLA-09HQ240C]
## XC4085XLA-09HQ240C
designator U?
XC4000XLA FPGA, 193 I/Os, 240-Pin HQFP, Speed Grade 9, Commercial Grade
footprint HQ240_N (Shrink QFP, 240-Leads, Body 32x32mm, Pitch 0.5mm, IPC Medium Density)
footprint HQ240_L (Shrink QFP, 240-Leads, Body 32x32mm, Pitch 0.5mm, IPC High Density)
footprint HQ240_M (Shrink QFP, 240-Leads, Body 32x32mm, Pitch 0.5mm, IPC Low Density)
part A pins: 2 I/O, GCK1 (A16) (io), 3 I/O (A17) (io), 4 I/O (io), 5 I/O (io), 8 I/O (io), 9 I/O (io), 10 I/O (io), 11 I/O (io), 12 I/O (io), 13 I/O (io), 15 I/O, FCLK1 (io), 16 I/O (io), 18 I/O (io), 20 I/O (io), 21 I/O (io), 23 I/O (io), 24 I/O (io), 25 I/O (io), 26 I/O (io), 27 I/O (io), 28 I/O (io), 31 I/O (io), 32 I/O (io), 33 I/O (io), 34 I/O (io), 35 I/O (io), 36 I/O (io), 38 I/O (io), 39 I/O (io), 41 I/O (io), 42 I/O (io), 43 I/O (io), 44 I/O, FCLK2 (io), 46 I/O (io), 47 I/O (io), 48 I/O (io), 49 I/O (io), 50 I/O (io), 51 I/O (io), 52 I/O (io), 53 I/O (io), 54 I/O (io), 55 I/O (io), 56 I/O (io), 57 I/O, GCK2 (io), 63 I/O, GCK3 (io), 64 I/O (HDC) (io), 65 I/O (io), 66 I/O (io), 67 I/O (io), 68 I/O (~{LDC}) (io), 69 I/O (io), 70 I/O (io), 71 I/O (io), 72 I/O (io), 73 I/O (io), 74 I/O (io), 76 I/O (io), 77 I/O (io), 78 I/O (io), 79 I/O (io), 81 I/O (io), 82 I/O (io), 84 I/O (io), 85 I/O (io), 86 I/O (io), 87 I/O (io), 88 I/O (io), 89 I/O (~{INIT}) (io), 92 I/O (io), 93 I/O (io), 94 I/O (io), 95 I/O (io), 96 I/O (io), 97 I/O (io), 99 I/O (io), 100 I/O (io), 102 I/O (io), 103 I/O (io), 104 I/O (io), 105 I/O (io), 107 I/O (io), 108 I/O (io), 109 I/O (io), 110 I/O (io), 111 I/O (io), 112 I/O (io), 113 I/O (io), 114 I/O (io), 115 I/O (io), 116 I/O (io), 117 I/O (io), 118 I/O, GCK4 (io), 123 I/O (D7) (io), 124 I/O, GCK5 (io), 125 I/O (io), 126 I/O (io), 127 I/O (io), 128 I/O (io), 129 I/O (D6) (io), 130 I/O (io), 131 I/O (io), 132 I/O (io), 133 I/O (io), 134 I/O (io), 136 I/O (io), 137 I/O (io), 138 I/O, FCLK3 (io), 139 I/O (io), 141 I/O (D5) (io), 142 I/O (~{CS}0) (io), 144 I/O (io), 145 I/O (io), 146 I/O (io), 147 I/O (io), 148 I/O (D4) (io), 149 I/O (io), 152 I/O (D3) (io), 153 I/O (~{RS}) (io), 154 I/O (io), 155 I/O (io), 156 I/O (io), 157 I/O (io), 159 I/O (D2) (io), 160 I/O (io), 162 I/O (io), 163 I/O, FCLK4 (io), 164 I/O (io), 165 I/O (io), 167 I/O (io), 168 I/O (io), 169 I/O (io), 170 I/O (io), 171 I/O (io), 172 I/O (io), 173 I/O (D1) (io), 174 I/O (~{RCK}, RDY_~{BUSY}) (io), 175 I/O (io), 176 I/O (io), 177 I/O (D0, DIN) (io), 178 I/O, GCK6 (DOUT) (io), 183 I/O (A0, ~{WS}) (io), 184 I/O, GCK7 (A1) (io), 185 I/O (io), 186 I/O (io), 187 I/O, (CS1, A2) (io), 188 I/O (A3) (io), 189 I/O (io), 190 I/O (io), 191 I/O (io), 192 I/O (io), 193 I/O (io), 194 I/O (io), 195 I/O (io), 197 I/O (io), 198 I/O (io), 199 I/O (io), 200 I/O (io), 202 I/O (A4) (io), 203 I/O (A5) (io), 205 I/O (io), 206 I/O (io), 207 I/O (A21) (io), 208 I/O (A20) (io), 209 I/O (A6) (io), 210 I/O (A7) (io), 213 I/O (A8) (io), 214 I/O (A9) (io), 215 I/O (A19) (io), 216 I/O (A18) (io), 217 I/O (io), 218 I/O (io), 220 I/O (A10) (io), 221 I/O (A11) (io), 223 I/O (io), 224 I/O (io), 225 I/O (io), 226 I/O (io), 228 I/O (io), 229 I/O (io), 230 I/O (io), 231 I/O (io), 232 I/O (A12) (io), 233 I/O (A13) (io), 234 I/O (io), 235 I/O (io), 236 I/O (io), 237 I/O (io), 238 I/O (A14) (io), 239 I/O, GCK8 (A15) (io)
part B pins: 1 GND (power), 6 I/O (TDI) (io), 7 I/O (TCK) (io), 14 GND (power), 17 I/O (TMS) (io), 19 VCC (power), 22 GND (power), 29 GND (power), 30 VCC (power), 37 GND (power), 40 VCC (power), 45 GND (power), 58 O (M1), 59 GND (power), 60 I (M0) (in), 61 VCC (power), 62 I (M2) (in), 75 GND (power), 80 VCC (power), 83 GND (power), 90 VCC (power), 91 GND (power), 98 GND (power), 101 VCC (power), 106 GND (power), 119 GND (power), 120 DONE (io), 121 VCC (power), 122 ~{PROGRAM} (in), 135 GND (power), 140 VCC (power), 143 GND (power), 150 VCC (power), 151 GND (power), 158 GND (power), 161 VCC (power), 166 GND (power), 179 CCLK (io), 180 VCC (power), 181 O, TDO (out), 182 GND (power), 196 GND (power), 201 VCC (power), 204 GND (power), 211 GND (power), 212 VCC (power), 219 GND (power), 222 VCC (power), 227 GND (power), 240 VCC (power)


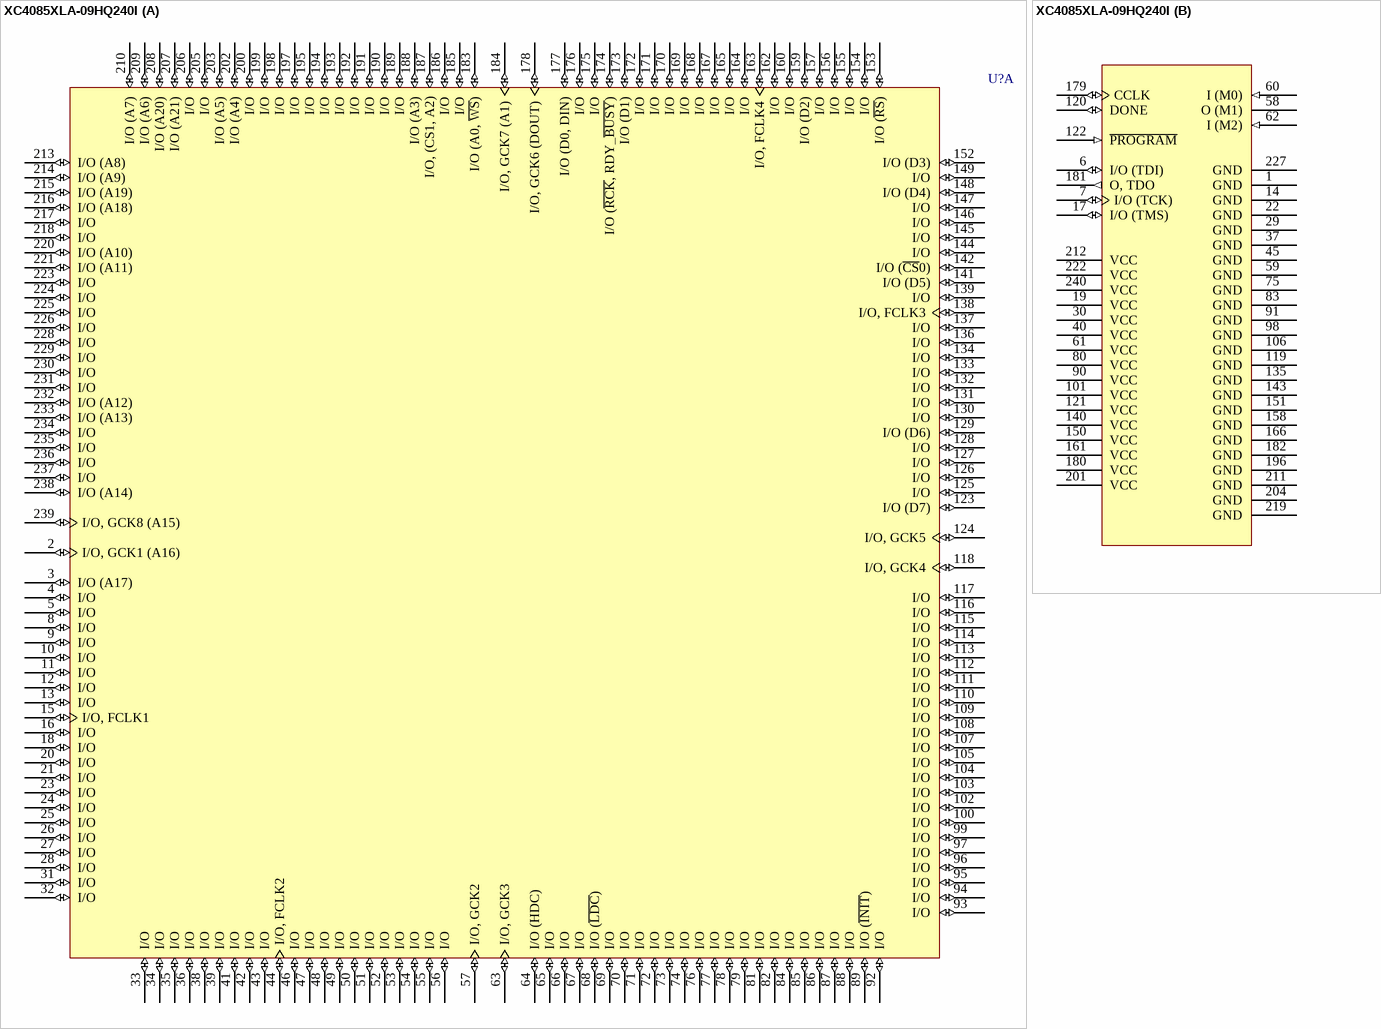
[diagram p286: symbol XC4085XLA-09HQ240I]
## XC4085XLA-09HQ240I
designator U?
XC4000XLA FPGA, 193 I/Os, 240-Pin HQFP, Speed Grade 9, Industrial Grade
footprint HQ240_N (Shrink QFP, 240-Leads, Body 32x32mm, Pitch 0.5mm, IPC Medium Density)
footprint HQ240_L (Shrink QFP, 240-Leads, Body 32x32mm, Pitch 0.5mm, IPC High Density)
footprint HQ240_M (Shrink QFP, 240-Leads, Body 32x32mm, Pitch 0.5mm, IPC Low Density)
part A pins: 2 I/O, GCK1 (A16) (io), 3 I/O (A17) (io), 4 I/O (io), 5 I/O (io), 8 I/O (io), 9 I/O (io), 10 I/O (io), 11 I/O (io), 12 I/O (io), 13 I/O (io), 15 I/O, FCLK1 (io), 16 I/O (io), 18 I/O (io), 20 I/O (io), 21 I/O (io), 23 I/O (io), 24 I/O (io), 25 I/O (io), 26 I/O (io), 27 I/O (io), 28 I/O (io), 31 I/O (io), 32 I/O (io), 33 I/O (io), 34 I/O (io), 35 I/O (io), 36 I/O (io), 38 I/O (io), 39 I/O (io), 41 I/O (io), 42 I/O (io), 43 I/O (io), 44 I/O, FCLK2 (io), 46 I/O (io), 47 I/O (io), 48 I/O (io), 49 I/O (io), 50 I/O (io), 51 I/O (io), 52 I/O (io), 53 I/O (io), 54 I/O (io), 55 I/O (io), 56 I/O (io), 57 I/O, GCK2 (io), 63 I/O, GCK3 (io), 64 I/O (HDC) (io), 65 I/O (io), 66 I/O (io), 67 I/O (io), 68 I/O (~{LDC}) (io), 69 I/O (io), 70 I/O (io), 71 I/O (io), 72 I/O (io), 73 I/O (io), 74 I/O (io), 76 I/O (io), 77 I/O (io), 78 I/O (io), 79 I/O (io), 81 I/O (io), 82 I/O (io), 84 I/O (io), 85 I/O (io), 86 I/O (io), 87 I/O (io), 88 I/O (io), 89 I/O (~{INIT}) (io), 92 I/O (io), 93 I/O (io), 94 I/O (io), 95 I/O (io), 96 I/O (io), 97 I/O (io), 99 I/O (io), 100 I/O (io), 102 I/O (io), 103 I/O (io), 104 I/O (io), 105 I/O (io), 107 I/O (io), 108 I/O (io), 109 I/O (io), 110 I/O (io), 111 I/O (io), 112 I/O (io), 113 I/O (io), 114 I/O (io), 115 I/O (io), 116 I/O (io), 117 I/O (io), 118 I/O, GCK4 (io), 123 I/O (D7) (io), 124 I/O, GCK5 (io), 125 I/O (io), 126 I/O (io), 127 I/O (io), 128 I/O (io), 129 I/O (D6) (io), 130 I/O (io), 131 I/O (io), 132 I/O (io), 133 I/O (io), 134 I/O (io), 136 I/O (io), 137 I/O (io), 138 I/O, FCLK3 (io), 139 I/O (io), 141 I/O (D5) (io), 142 I/O (~{CS}0) (io), 144 I/O (io), 145 I/O (io), 146 I/O (io), 147 I/O (io), 148 I/O (D4) (io), 149 I/O (io), 152 I/O (D3) (io), 153 I/O (~{RS}) (io), 154 I/O (io), 155 I/O (io), 156 I/O (io), 157 I/O (io), 159 I/O (D2) (io), 160 I/O (io), 162 I/O (io), 163 I/O, FCLK4 (io), 164 I/O (io), 165 I/O (io), 167 I/O (io), 168 I/O (io), 169 I/O (io), 170 I/O (io), 171 I/O (io), 172 I/O (io), 173 I/O (D1) (io), 174 I/O (~{RCK}, RDY_~{BUSY}) (io), 175 I/O (io), 176 I/O (io), 177 I/O (D0, DIN) (io), 178 I/O, GCK6 (DOUT) (io), 183 I/O (A0, ~{WS}) (io), 184 I/O, GCK7 (A1) (io), 185 I/O (io), 186 I/O (io), 187 I/O, (CS1, A2) (io), 188 I/O (A3) (io), 189 I/O (io), 190 I/O (io), 191 I/O (io), 192 I/O (io), 193 I/O (io), 194 I/O (io), 195 I/O (io), 197 I/O (io), 198 I/O (io), 199 I/O (io), 200 I/O (io), 202 I/O (A4) (io), 203 I/O (A5) (io), 205 I/O (io), 206 I/O (io), 207 I/O (A21) (io), 208 I/O (A20) (io), 209 I/O (A6) (io), 210 I/O (A7) (io), 213 I/O (A8) (io), 214 I/O (A9) (io), 215 I/O (A19) (io), 216 I/O (A18) (io), 217 I/O (io), 218 I/O (io), 220 I/O (A10) (io), 221 I/O (A11) (io), 223 I/O (io), 224 I/O (io), 225 I/O (io), 226 I/O (io), 228 I/O (io), 229 I/O (io), 230 I/O (io), 231 I/O (io), 232 I/O (A12) (io), 233 I/O (A13) (io), 234 I/O (io), 235 I/O (io), 236 I/O (io), 237 I/O (io), 238 I/O (A14) (io), 239 I/O, GCK8 (A15) (io)
part B pins: 1 GND (power), 6 I/O (TDI) (io), 7 I/O (TCK) (io), 14 GND (power), 17 I/O (TMS) (io), 19 VCC (power), 22 GND (power), 29 GND (power), 30 VCC (power), 37 GND (power), 40 VCC (power), 45 GND (power), 58 O (M1), 59 GND (power), 60 I (M0) (in), 61 VCC (power), 62 I (M2) (in), 75 GND (power), 80 VCC (power), 83 GND (power), 90 VCC (power), 91 GND (power), 98 GND (power), 101 VCC (power), 106 GND (power), 119 GND (power), 120 DONE (io), 121 VCC (power), 122 ~{PROGRAM} (in), 135 GND (power), 140 VCC (power), 143 GND (power), 150 VCC (power), 151 GND (power), 158 GND (power), 161 VCC (power), 166 GND (power), 179 CCLK (io), 180 VCC (power), 181 O, TDO (out), 182 GND (power), 196 GND (power), 201 VCC (power), 204 GND (power), 211 GND (power), 212 VCC (power), 219 GND (power), 222 VCC (power), 227 GND (power), 240 VCC (power)


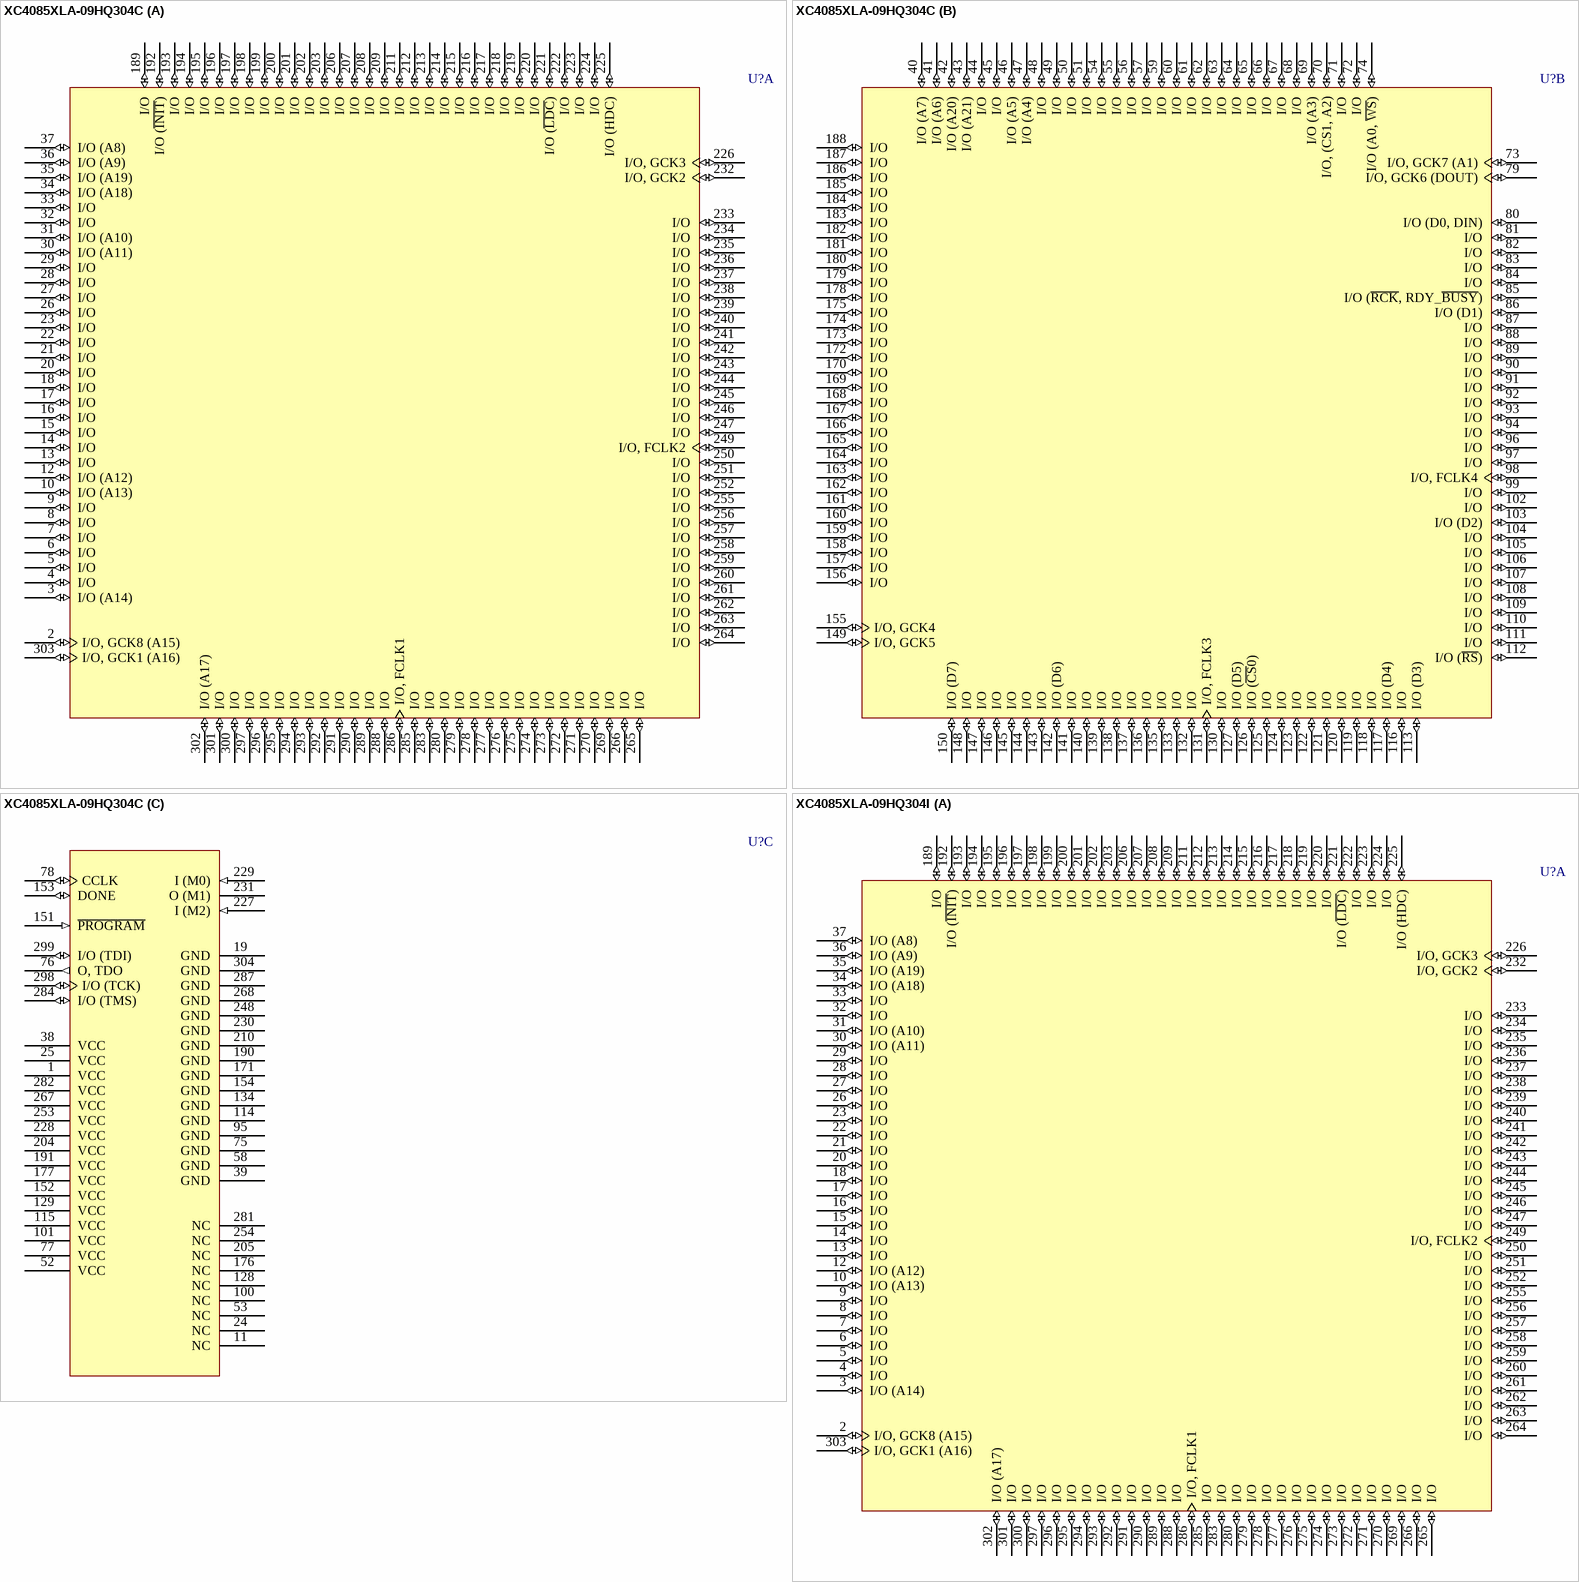
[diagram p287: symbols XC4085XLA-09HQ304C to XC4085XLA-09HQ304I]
## XC4085XLA-09HQ304C
designator U?
XC4000XLA FPGA, 256 I/Os, 304-Pin HQFP, Speed Grade 9, Commercial Grade
footprint HQ304_N (Shrink QFP, 304-Leads, Body 40x40mm, Pitch 0.5mm, IPC Medium Density)
footprint HQ304_L (Shrink QFP, 304-Leads, Body 40x40mm, Pitch 0.5mm, IPC High Density)
footprint HQ304_M (Shrink QFP, 304-Leads, Body 40x40mm, Pitch 0.5mm, IPC Low Density)
part A pins: 2 I/O, GCK8 (A15) (io), 3 I/O (A14) (io), 4 I/O (io), 5 I/O (io), 6 I/O (io), 7 I/O (io), 8 I/O (io), 9 I/O (io), 10 I/O (A13) (io), 12 I/O (A12) (io), 13 I/O (io), 14 I/O (io), 15 I/O (io), 16 I/O (io), 17 I/O (io), 18 I/O (io), 20 I/O (io), 21 I/O (io), 22 I/O (io), 23 I/O (io), 26 I/O (io), 27 I/O (io), 28 I/O (io), 29 I/O (io), 30 I/O (A11) (io), 31 I/O (A10) (io), 32 I/O (io), 33 I/O (io), 34 I/O (A18) (io), 35 I/O (A19) (io), 36 I/O (A9) (io), 37 I/O (A8) (io), 189 I/O (io), 192 I/O (~{INIT}) (io), 193 I/O (io), 194 I/O (io), 195 I/O (io), 196 I/O (io), 197 I/O (io), 198 I/O (io), 199 I/O (io), 200 I/O (io), 201 I/O (io), 202 I/O (io), 203 I/O (io), 206 I/O (io), 207 I/O (io), 208 I/O (io), 209 I/O (io), 211 I/O (io), 212 I/O (io), 213 I/O (io), 214 I/O (io), 215 I/O (io), 216 I/O (io), 217 I/O (io), 218 I/O (io), 219 I/O (io), 220 I/O (io), 221 I/O (~{LDC}) (io), 222 I/O (io), 223 I/O (io), 224 I/O (io), 225 I/O (HDC) (io), 226 I/O, GCK3 (io), 232 I/O, GCK2 (io), 233 I/O (io), 234 I/O (io), 235 I/O (io), 236 I/O (io), 237 I/O (io), 238 I/O (io), 239 I/O (io), 240 I/O (io), 241 I/O (io), 242 I/O (io), 243 I/O (io), 244 I/O (io), 245 I/O (io), 246 I/O (io), 247 I/O (io), 249 I/O, FCLK2 (io), 250 I/O (io), 251 I/O (io), 252 I/O (io), 255 I/O (io), 256 I/O (io), 257 I/O (io), 258 I/O (io), 259 I/O (io), 260 I/O (io), 261 I/O (io), 262 I/O (io), 263 I/O (io), 264 I/O (io), 265 I/O (io), 266 I/O (io), 269 I/O (io), 270 I/O (io), 271 I/O (io), 272 I/O (io), 273 I/O (io), 274 I/O (io), 275 I/O (io), 276 I/O (io), 277 I/O (io), 278 I/O (io), 279 I/O (io), 280 I/O (io), 283 I/O (io), 285 I/O (io), 286 I/O, FCLK1 (io), 288 I/O (io), 289 I/O (io), 290 I/O (io), 291 I/O (io), 292 I/O (io), 293 I/O (io), 294 I/O (io), 295 I/O (io), 296 I/O (io), 297 I/O (io), 300 I/O (io), 301 I/O (io), 302 I/O (A17) (io), 303 I/O, GCK1 (A16) (io)
part B pins: 40 I/O (A7) (io), 41 I/O (A6) (io), 42 I/O (A20) (io), 43 I/O (A21) (io), 44 I/O (io), 45 I/O (io), 46 I/O (A5) (io), 47 I/O (A4) (io), 48 I/O (io), 49 I/O (io), 50 I/O (io), 51 I/O (io), 54 I/O (io), 55 I/O (io), 56 I/O (io), 57 I/O (io), 59 I/O (io), 60 I/O (io), 61 I/O (io), 62 I/O (io), 63 I/O (io), 64 I/O (io), 65 I/O (io), 66 I/O (io), 67 I/O (io), 68 I/O (io), 69 I/O (A3) (io), 70 I/O, (CS1, A2) (io), 71 I/O (io), 72 I/O (io), 73 I/O, GCK7 (A1) (io), 74 I/O (A0, ~{WS}) (io), 79 I/O, GCK6 (DOUT) (io), 80 I/O (D0, DIN) (io), 81 I/O (io), 82 I/O (io), 83 I/O (io), 84 I/O (io), 85 I/O (~{RCK}, RDY_~{BUSY}) (io), 86 I/O (D1) (io), 87 I/O (io), 88 I/O (io), 89 I/O (io), 90 I/O (io), 91 I/O (io), 92 I/O (io), 93 I/O (io), 94 I/O (io), 96 I/O (io), 97 I/O (io), 98 I/O, FCLK4 (io), 99 I/O (io), 102 I/O (io), 103 I/O (D2) (io), 104 I/O (io), 105 I/O (io), 106 I/O (io), 107 I/O (io), 108 I/O (io), 109 I/O (io), 110 I/O (io), 111 I/O (io), 112 I/O (~{RS}) (io), 113 I/O (D3) (io), 116 I/O (io), 117 I/O (D4) (io), 118 I/O (io), 119 I/O (io), 120 I/O (io), 121 I/O (io), 122 I/O (io), 123 I/O (io), 124 I/O (io), 125 I/O (io), 126 I/O (~{CS}0) (io), 127 I/O (D5) (io), 130 I/O (io), 131 I/O, FCLK3 (io), 132 I/O (io), 133 I/O (io), 135 I/O (io), 136 I/O (io), 137 I/O (io), 138 I/O (io), 139 I/O (io), 140 I/O (io), 141 I/O (io), 142 I/O (D6) (io), 143 I/O (io), 144 I/O (io), 145 I/O (io), 146 I/O (io), 147 I/O (io), 148 I/O (io), 149 I/O, GCK5 (io), 150 I/O (D7) (io), 155 I/O, GCK4 (io), 156 I/O (io), 157 I/O (io), 158 I/O (io), 159 I/O (io), 160 I/O (io), 161 I/O (io), 162 I/O (io), 163 I/O (io), 164 I/O (io), 165 I/O (io), 166 I/O (io), 167 I/O (io), 168 I/O (io), 169 I/O (io), 170 I/O (io), 172 I/O (io), 173 I/O (io), 174 I/O (io), 175 I/O (io), 178 I/O (io), 179 I/O (io), 180 I/O (io), 181 I/O (io), 182 I/O (io), 183 I/O (io), 184 I/O (io), 185 I/O (io), 186 I/O (io), 187 I/O (io), 188 I/O (io)
part C pins: 1 VCC (power), 11 NC, 19 GND (power), 24 NC, 25 VCC (power), 38 VCC (power), 39 GND (power), 52 VCC (power), 53 NC, 58 GND (power), 75 GND (power), 76 O, TDO (out), 77 VCC (power), 78 CCLK (io), 95 GND (power), 100 NC, 101 VCC (power), 114 GND (power), 115 VCC (power), 128 NC, 129 VCC (power), 134 GND (power), 151 ~{PROGRAM} (in), 152 VCC (power), 153 DONE (io), 154 GND (power), 171 GND (power), 176 NC, 177 VCC (power), 190 GND (power), 191 VCC (power), 204 VCC (power), 205 NC, 210 GND (power), 227 I (M2) (in), 228 VCC (power), 229 I (M0) (in), 230 GND (power), 231 O (M1), 248 GND (power), 253 VCC (power), 254 NC, 267 VCC (power), 268 GND (power), 281 NC, 282 VCC (power), 284 I/O (TMS) (io), 287 GND (power), 298 I/O (TCK) (io), 299 I/O (TDI) (io), 304 GND (power)


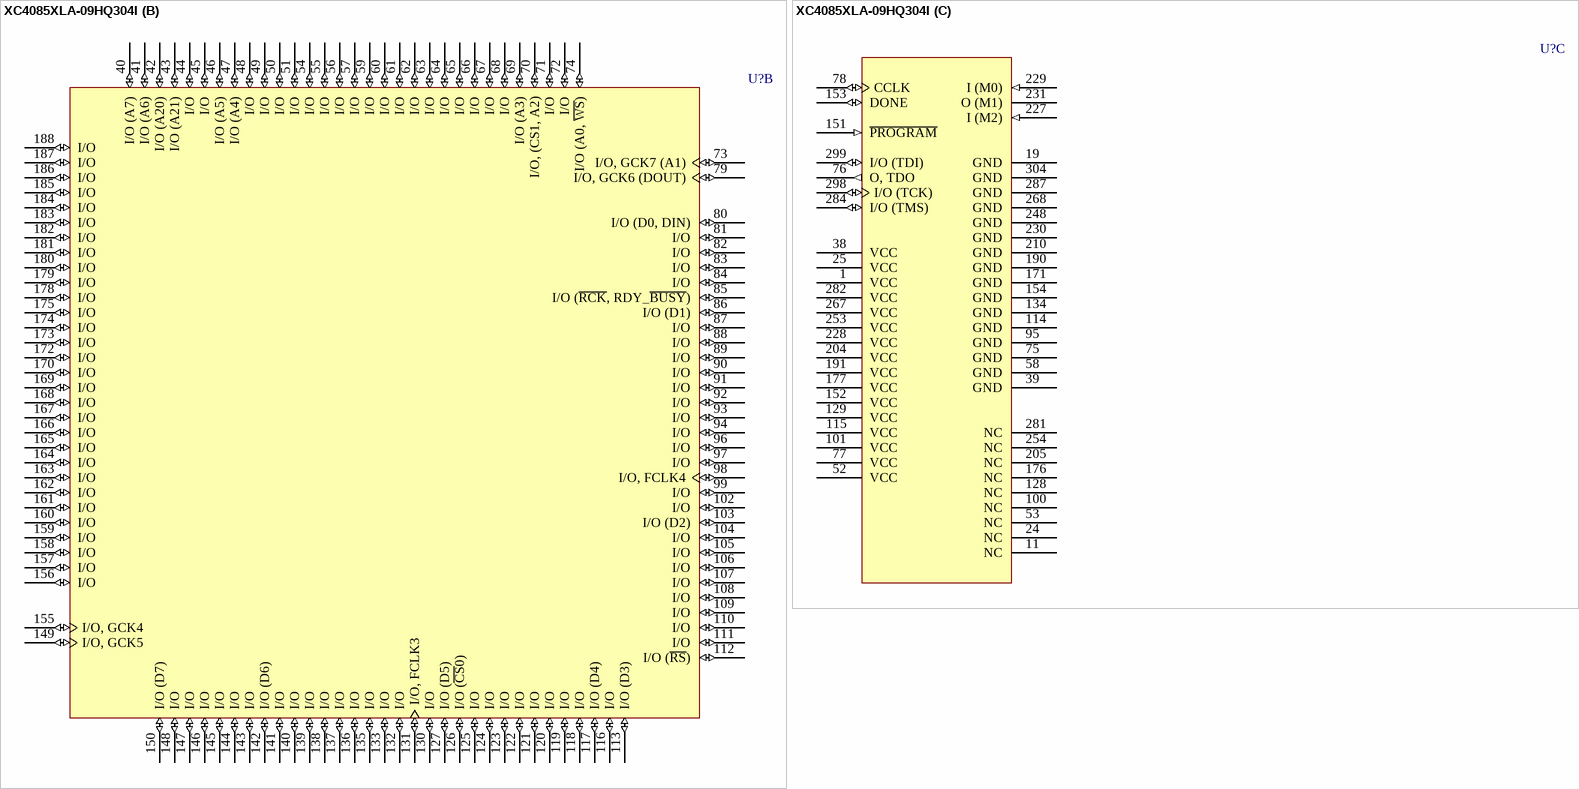
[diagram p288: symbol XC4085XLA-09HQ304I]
## XC4085XLA-09HQ304I
designator U?
XC4000XLA FPGA, 256 I/Os, 304-Pin HQFP, Speed Grade 9, Industrial Grade
footprint HQ304_N (Shrink QFP, 304-Leads, Body 40x40mm, Pitch 0.5mm, IPC Medium Density)
footprint HQ304_L (Shrink QFP, 304-Leads, Body 40x40mm, Pitch 0.5mm, IPC High Density)
footprint HQ304_M (Shrink QFP, 304-Leads, Body 40x40mm, Pitch 0.5mm, IPC Low Density)
part A pins: 2 I/O, GCK8 (A15) (io), 3 I/O (A14) (io), 4 I/O (io), 5 I/O (io), 6 I/O (io), 7 I/O (io), 8 I/O (io), 9 I/O (io), 10 I/O (A13) (io), 12 I/O (A12) (io), 13 I/O (io), 14 I/O (io), 15 I/O (io), 16 I/O (io), 17 I/O (io), 18 I/O (io), 20 I/O (io), 21 I/O (io), 22 I/O (io), 23 I/O (io), 26 I/O (io), 27 I/O (io), 28 I/O (io), 29 I/O (io), 30 I/O (A11) (io), 31 I/O (A10) (io), 32 I/O (io), 33 I/O (io), 34 I/O (A18) (io), 35 I/O (A19) (io), 36 I/O (A9) (io), 37 I/O (A8) (io), 189 I/O (io), 192 I/O (~{INIT}) (io), 193 I/O (io), 194 I/O (io), 195 I/O (io), 196 I/O (io), 197 I/O (io), 198 I/O (io), 199 I/O (io), 200 I/O (io), 201 I/O (io), 202 I/O (io), 203 I/O (io), 206 I/O (io), 207 I/O (io), 208 I/O (io), 209 I/O (io), 211 I/O (io), 212 I/O (io), 213 I/O (io), 214 I/O (io), 215 I/O (io), 216 I/O (io), 217 I/O (io), 218 I/O (io), 219 I/O (io), 220 I/O (io), 221 I/O (~{LDC}) (io), 222 I/O (io), 223 I/O (io), 224 I/O (io), 225 I/O (HDC) (io), 226 I/O, GCK3 (io), 232 I/O, GCK2 (io), 233 I/O (io), 234 I/O (io), 235 I/O (io), 236 I/O (io), 237 I/O (io), 238 I/O (io), 239 I/O (io), 240 I/O (io), 241 I/O (io), 242 I/O (io), 243 I/O (io), 244 I/O (io), 245 I/O (io), 246 I/O (io), 247 I/O (io), 249 I/O, FCLK2 (io), 250 I/O (io), 251 I/O (io), 252 I/O (io), 255 I/O (io), 256 I/O (io), 257 I/O (io), 258 I/O (io), 259 I/O (io), 260 I/O (io), 261 I/O (io), 262 I/O (io), 263 I/O (io), 264 I/O (io), 265 I/O (io), 266 I/O (io), 269 I/O (io), 270 I/O (io), 271 I/O (io), 272 I/O (io), 273 I/O (io), 274 I/O (io), 275 I/O (io), 276 I/O (io), 277 I/O (io), 278 I/O (io), 279 I/O (io), 280 I/O (io), 283 I/O (io), 285 I/O (io), 286 I/O, FCLK1 (io), 288 I/O (io), 289 I/O (io), 290 I/O (io), 291 I/O (io), 292 I/O (io), 293 I/O (io), 294 I/O (io), 295 I/O (io), 296 I/O (io), 297 I/O (io), 300 I/O (io), 301 I/O (io), 302 I/O (A17) (io), 303 I/O, GCK1 (A16) (io)
part B pins: 40 I/O (A7) (io), 41 I/O (A6) (io), 42 I/O (A20) (io), 43 I/O (A21) (io), 44 I/O (io), 45 I/O (io), 46 I/O (A5) (io), 47 I/O (A4) (io), 48 I/O (io), 49 I/O (io), 50 I/O (io), 51 I/O (io), 54 I/O (io), 55 I/O (io), 56 I/O (io), 57 I/O (io), 59 I/O (io), 60 I/O (io), 61 I/O (io), 62 I/O (io), 63 I/O (io), 64 I/O (io), 65 I/O (io), 66 I/O (io), 67 I/O (io), 68 I/O (io), 69 I/O (A3) (io), 70 I/O, (CS1, A2) (io), 71 I/O (io), 72 I/O (io), 73 I/O, GCK7 (A1) (io), 74 I/O (A0, ~{WS}) (io), 79 I/O, GCK6 (DOUT) (io), 80 I/O (D0, DIN) (io), 81 I/O (io), 82 I/O (io), 83 I/O (io), 84 I/O (io), 85 I/O (~{RCK}, RDY_~{BUSY}) (io), 86 I/O (D1) (io), 87 I/O (io), 88 I/O (io), 89 I/O (io), 90 I/O (io), 91 I/O (io), 92 I/O (io), 93 I/O (io), 94 I/O (io), 96 I/O (io), 97 I/O (io), 98 I/O, FCLK4 (io), 99 I/O (io), 102 I/O (io), 103 I/O (D2) (io), 104 I/O (io), 105 I/O (io), 106 I/O (io), 107 I/O (io), 108 I/O (io), 109 I/O (io), 110 I/O (io), 111 I/O (io), 112 I/O (~{RS}) (io), 113 I/O (D3) (io), 116 I/O (io), 117 I/O (D4) (io), 118 I/O (io), 119 I/O (io), 120 I/O (io), 121 I/O (io), 122 I/O (io), 123 I/O (io), 124 I/O (io), 125 I/O (io), 126 I/O (~{CS}0) (io), 127 I/O (D5) (io), 130 I/O (io), 131 I/O, FCLK3 (io), 132 I/O (io), 133 I/O (io), 135 I/O (io), 136 I/O (io), 137 I/O (io), 138 I/O (io), 139 I/O (io), 140 I/O (io), 141 I/O (io), 142 I/O (D6) (io), 143 I/O (io), 144 I/O (io), 145 I/O (io), 146 I/O (io), 147 I/O (io), 148 I/O (io), 149 I/O, GCK5 (io), 150 I/O (D7) (io), 155 I/O, GCK4 (io), 156 I/O (io), 157 I/O (io), 158 I/O (io), 159 I/O (io), 160 I/O (io), 161 I/O (io), 162 I/O (io), 163 I/O (io), 164 I/O (io), 165 I/O (io), 166 I/O (io), 167 I/O (io), 168 I/O (io), 169 I/O (io), 170 I/O (io), 172 I/O (io), 173 I/O (io), 174 I/O (io), 175 I/O (io), 178 I/O (io), 179 I/O (io), 180 I/O (io), 181 I/O (io), 182 I/O (io), 183 I/O (io), 184 I/O (io), 185 I/O (io), 186 I/O (io), 187 I/O (io), 188 I/O (io)
part C pins: 1 VCC (power), 11 NC, 19 GND (power), 24 NC, 25 VCC (power), 38 VCC (power), 39 GND (power), 52 VCC (power), 53 NC, 58 GND (power), 75 GND (power), 76 O, TDO (out), 77 VCC (power), 78 CCLK (io), 95 GND (power), 100 NC, 101 VCC (power), 114 GND (power), 115 VCC (power), 128 NC, 129 VCC (power), 134 GND (power), 151 ~{PROGRAM} (in), 152 VCC (power), 153 DONE (io), 154 GND (power), 171 GND (power), 176 NC, 177 VCC (power), 190 GND (power), 191 VCC (power), 204 VCC (power), 205 NC, 210 GND (power), 227 I (M2) (in), 228 VCC (power), 229 I (M0) (in), 230 GND (power), 231 O (M1), 248 GND (power), 253 VCC (power), 254 NC, 267 VCC (power), 268 GND (power), 281 NC, 282 VCC (power), 284 I/O (TMS) (io), 287 GND (power), 298 I/O (TCK) (io), 299 I/O (TDI) (io), 304 GND (power)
